VERSION 5.7 ;
  NOWIREEXTENSIONATPIN ON ;
  DIVIDERCHAR "/" ;
  BUSBITCHARS "[]" ;
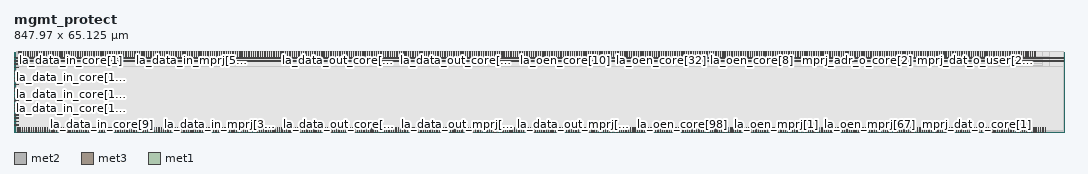
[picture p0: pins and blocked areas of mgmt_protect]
MACRO mgmt_protect
  CLASS BLOCK ;
  FOREIGN mgmt_protect ;
  ORIGIN 0.000 0.000 ;
  SIZE 847.970 BY 65.125 ;
  PIN caravel_clk
    DIRECTION INPUT ;
    PORT
      LAYER met2 ;
        RECT 2.850 0.000 3.130 4.000 ;
    END
  END caravel_clk
  PIN caravel_clk2
    DIRECTION INPUT ;
    PORT
      LAYER met2 ;
        RECT 4.690 0.000 4.970 4.000 ;
    END
  END caravel_clk2
  PIN caravel_rstn
    DIRECTION INPUT ;
    PORT
      LAYER met3 ;
        RECT 0.000 5.480 4.000 6.080 ;
    END
  END caravel_rstn
  PIN la_data_in_core[0]
    DIRECTION OUTPUT TRISTATE ;
    PORT
      LAYER met2 ;
        RECT 3.770 61.000 4.050 65.000 ;
    END
  END la_data_in_core[0]
  PIN la_data_in_core[100]
    DIRECTION OUTPUT TRISTATE ;
    PORT
      LAYER met3 ;
        RECT 0.000 59.880 4.000 60.480 ;
    END
  END la_data_in_core[100]
  PIN la_data_in_core[101]
    DIRECTION OUTPUT TRISTATE ;
    PORT
      LAYER met2 ;
        RECT 5.610 61.000 5.890 65.000 ;
    END
  END la_data_in_core[101]
  PIN la_data_in_core[102]
    DIRECTION OUTPUT TRISTATE ;
    PORT
      LAYER met3 ;
        RECT 0.000 57.160 4.000 57.760 ;
    END
  END la_data_in_core[102]
  PIN la_data_in_core[103]
    DIRECTION OUTPUT TRISTATE ;
    PORT
      LAYER met2 ;
        RECT 7.450 61.000 7.730 65.000 ;
    END
  END la_data_in_core[103]
  PIN la_data_in_core[104]
    DIRECTION OUTPUT TRISTATE ;
    PORT
      LAYER met2 ;
        RECT 9.290 61.000 9.570 65.000 ;
    END
  END la_data_in_core[104]
  PIN la_data_in_core[105]
    DIRECTION OUTPUT TRISTATE ;
    PORT
      LAYER met3 ;
        RECT 0.000 54.440 4.000 55.040 ;
    END
  END la_data_in_core[105]
  PIN la_data_in_core[106]
    DIRECTION OUTPUT TRISTATE ;
    PORT
      LAYER met2 ;
        RECT 11.130 61.000 11.410 65.000 ;
    END
  END la_data_in_core[106]
  PIN la_data_in_core[107]
    DIRECTION OUTPUT TRISTATE ;
    PORT
      LAYER met3 ;
        RECT 0.000 51.720 4.000 52.320 ;
    END
  END la_data_in_core[107]
  PIN la_data_in_core[108]
    DIRECTION OUTPUT TRISTATE ;
    PORT
      LAYER met2 ;
        RECT 12.970 61.000 13.250 65.000 ;
    END
  END la_data_in_core[108]
  PIN la_data_in_core[109]
    DIRECTION OUTPUT TRISTATE ;
    PORT
      LAYER met2 ;
        RECT 14.810 61.000 15.090 65.000 ;
    END
  END la_data_in_core[109]
  PIN la_data_in_core[10]
    DIRECTION OUTPUT TRISTATE ;
    PORT
      LAYER met3 ;
        RECT 0.000 49.000 4.000 49.600 ;
    END
  END la_data_in_core[10]
  PIN la_data_in_core[110]
    DIRECTION OUTPUT TRISTATE ;
    PORT
      LAYER met2 ;
        RECT 16.650 61.000 16.930 65.000 ;
    END
  END la_data_in_core[110]
  PIN la_data_in_core[111]
    DIRECTION OUTPUT TRISTATE ;
    PORT
      LAYER met3 ;
        RECT 0.000 46.280 4.000 46.880 ;
    END
  END la_data_in_core[111]
  PIN la_data_in_core[112]
    DIRECTION OUTPUT TRISTATE ;
    PORT
      LAYER met2 ;
        RECT 18.490 61.000 18.770 65.000 ;
    END
  END la_data_in_core[112]
  PIN la_data_in_core[113]
    DIRECTION OUTPUT TRISTATE ;
    PORT
      LAYER met2 ;
        RECT 20.330 61.000 20.610 65.000 ;
    END
  END la_data_in_core[113]
  PIN la_data_in_core[114]
    DIRECTION OUTPUT TRISTATE ;
    PORT
      LAYER met3 ;
        RECT 0.000 43.560 4.000 44.160 ;
    END
  END la_data_in_core[114]
  PIN la_data_in_core[115]
    DIRECTION OUTPUT TRISTATE ;
    PORT
      LAYER met2 ;
        RECT 22.170 61.000 22.450 65.000 ;
    END
  END la_data_in_core[115]
  PIN la_data_in_core[116]
    DIRECTION OUTPUT TRISTATE ;
    PORT
      LAYER met3 ;
        RECT 0.000 40.840 4.000 41.440 ;
    END
  END la_data_in_core[116]
  PIN la_data_in_core[117]
    DIRECTION OUTPUT TRISTATE ;
    PORT
      LAYER met2 ;
        RECT 24.010 61.000 24.290 65.000 ;
    END
  END la_data_in_core[117]
  PIN la_data_in_core[118]
    DIRECTION OUTPUT TRISTATE ;
    PORT
      LAYER met2 ;
        RECT 25.850 61.000 26.130 65.000 ;
    END
  END la_data_in_core[118]
  PIN la_data_in_core[119]
    DIRECTION OUTPUT TRISTATE ;
    PORT
      LAYER met3 ;
        RECT 0.000 38.120 4.000 38.720 ;
    END
  END la_data_in_core[119]
  PIN la_data_in_core[11]
    DIRECTION OUTPUT TRISTATE ;
    PORT
      LAYER met2 ;
        RECT 27.690 61.000 27.970 65.000 ;
    END
  END la_data_in_core[11]
  PIN la_data_in_core[120]
    DIRECTION OUTPUT TRISTATE ;
    PORT
      LAYER met3 ;
        RECT 0.000 35.400 4.000 36.000 ;
    END
  END la_data_in_core[120]
  PIN la_data_in_core[121]
    DIRECTION OUTPUT TRISTATE ;
    PORT
      LAYER met2 ;
        RECT 29.530 61.000 29.810 65.000 ;
    END
  END la_data_in_core[121]
  PIN la_data_in_core[122]
    DIRECTION OUTPUT TRISTATE ;
    PORT
      LAYER met2 ;
        RECT 31.370 61.000 31.650 65.000 ;
    END
  END la_data_in_core[122]
  PIN la_data_in_core[123]
    DIRECTION OUTPUT TRISTATE ;
    PORT
      LAYER met3 ;
        RECT 0.000 32.680 4.000 33.280 ;
    END
  END la_data_in_core[123]
  PIN la_data_in_core[124]
    DIRECTION OUTPUT TRISTATE ;
    PORT
      LAYER met2 ;
        RECT 33.210 61.000 33.490 65.000 ;
    END
  END la_data_in_core[124]
  PIN la_data_in_core[125]
    DIRECTION OUTPUT TRISTATE ;
    PORT
      LAYER met3 ;
        RECT 0.000 29.960 4.000 30.560 ;
    END
  END la_data_in_core[125]
  PIN la_data_in_core[126]
    DIRECTION OUTPUT TRISTATE ;
    PORT
      LAYER met2 ;
        RECT 35.050 61.000 35.330 65.000 ;
    END
  END la_data_in_core[126]
  PIN la_data_in_core[127]
    DIRECTION OUTPUT TRISTATE ;
    PORT
      LAYER met2 ;
        RECT 36.890 61.000 37.170 65.000 ;
    END
  END la_data_in_core[127]
  PIN la_data_in_core[12]
    DIRECTION OUTPUT TRISTATE ;
    PORT
      LAYER met3 ;
        RECT 0.000 27.240 4.000 27.840 ;
    END
  END la_data_in_core[12]
  PIN la_data_in_core[13]
    DIRECTION OUTPUT TRISTATE ;
    PORT
      LAYER met2 ;
        RECT 38.730 61.000 39.010 65.000 ;
    END
  END la_data_in_core[13]
  PIN la_data_in_core[14]
    DIRECTION OUTPUT TRISTATE ;
    PORT
      LAYER met3 ;
        RECT 0.000 24.520 4.000 25.120 ;
    END
  END la_data_in_core[14]
  PIN la_data_in_core[15]
    DIRECTION OUTPUT TRISTATE ;
    PORT
      LAYER met2 ;
        RECT 40.570 61.000 40.850 65.000 ;
    END
  END la_data_in_core[15]
  PIN la_data_in_core[16]
    DIRECTION OUTPUT TRISTATE ;
    PORT
      LAYER met2 ;
        RECT 42.410 61.000 42.690 65.000 ;
    END
  END la_data_in_core[16]
  PIN la_data_in_core[17]
    DIRECTION OUTPUT TRISTATE ;
    PORT
      LAYER met3 ;
        RECT 0.000 21.800 4.000 22.400 ;
    END
  END la_data_in_core[17]
  PIN la_data_in_core[18]
    DIRECTION OUTPUT TRISTATE ;
    PORT
      LAYER met2 ;
        RECT 44.250 61.000 44.530 65.000 ;
    END
  END la_data_in_core[18]
  PIN la_data_in_core[19]
    DIRECTION OUTPUT TRISTATE ;
    PORT
      LAYER met3 ;
        RECT 0.000 19.080 4.000 19.680 ;
    END
  END la_data_in_core[19]
  PIN la_data_in_core[1]
    DIRECTION OUTPUT TRISTATE ;
    PORT
      LAYER met2 ;
        RECT 46.090 61.000 46.370 65.000 ;
    END
  END la_data_in_core[1]
  PIN la_data_in_core[20]
    DIRECTION OUTPUT TRISTATE ;
    PORT
      LAYER met2 ;
        RECT 47.930 61.000 48.210 65.000 ;
    END
  END la_data_in_core[20]
  PIN la_data_in_core[21]
    DIRECTION OUTPUT TRISTATE ;
    PORT
      LAYER met3 ;
        RECT 0.000 16.360 4.000 16.960 ;
    END
  END la_data_in_core[21]
  PIN la_data_in_core[22]
    DIRECTION OUTPUT TRISTATE ;
    PORT
      LAYER met2 ;
        RECT 49.770 61.000 50.050 65.000 ;
    END
  END la_data_in_core[22]
  PIN la_data_in_core[23]
    DIRECTION OUTPUT TRISTATE ;
    PORT
      LAYER met3 ;
        RECT 0.000 13.640 4.000 14.240 ;
    END
  END la_data_in_core[23]
  PIN la_data_in_core[24]
    DIRECTION OUTPUT TRISTATE ;
    PORT
      LAYER met2 ;
        RECT 51.610 61.000 51.890 65.000 ;
    END
  END la_data_in_core[24]
  PIN la_data_in_core[25]
    DIRECTION OUTPUT TRISTATE ;
    PORT
      LAYER met2 ;
        RECT 53.450 61.000 53.730 65.000 ;
    END
  END la_data_in_core[25]
  PIN la_data_in_core[26]
    DIRECTION OUTPUT TRISTATE ;
    PORT
      LAYER met3 ;
        RECT 0.000 10.920 4.000 11.520 ;
    END
  END la_data_in_core[26]
  PIN la_data_in_core[27]
    DIRECTION OUTPUT TRISTATE ;
    PORT
      LAYER met2 ;
        RECT 55.290 61.000 55.570 65.000 ;
    END
  END la_data_in_core[27]
  PIN la_data_in_core[28]
    DIRECTION OUTPUT TRISTATE ;
    PORT
      LAYER met3 ;
        RECT 0.000 8.200 4.000 8.800 ;
    END
  END la_data_in_core[28]
  PIN la_data_in_core[29]
    DIRECTION OUTPUT TRISTATE ;
    PORT
      LAYER met2 ;
        RECT 57.130 61.000 57.410 65.000 ;
    END
  END la_data_in_core[29]
  PIN la_data_in_core[2]
    DIRECTION OUTPUT TRISTATE ;
    PORT
      LAYER met2 ;
        RECT 58.970 61.000 59.250 65.000 ;
    END
  END la_data_in_core[2]
  PIN la_data_in_core[30]
    DIRECTION OUTPUT TRISTATE ;
    PORT
      LAYER met2 ;
        RECT 60.810 61.000 61.090 65.000 ;
    END
  END la_data_in_core[30]
  PIN la_data_in_core[31]
    DIRECTION OUTPUT TRISTATE ;
    PORT
      LAYER met2 ;
        RECT 62.650 61.000 62.930 65.000 ;
    END
  END la_data_in_core[31]
  PIN la_data_in_core[32]
    DIRECTION OUTPUT TRISTATE ;
    PORT
      LAYER met2 ;
        RECT 64.490 61.000 64.770 65.000 ;
    END
  END la_data_in_core[32]
  PIN la_data_in_core[33]
    DIRECTION OUTPUT TRISTATE ;
    PORT
      LAYER met2 ;
        RECT 66.330 61.000 66.610 65.000 ;
    END
  END la_data_in_core[33]
  PIN la_data_in_core[34]
    DIRECTION OUTPUT TRISTATE ;
    PORT
      LAYER met2 ;
        RECT 68.170 61.000 68.450 65.000 ;
    END
  END la_data_in_core[34]
  PIN la_data_in_core[35]
    DIRECTION OUTPUT TRISTATE ;
    PORT
      LAYER met2 ;
        RECT 70.010 61.000 70.290 65.000 ;
    END
  END la_data_in_core[35]
  PIN la_data_in_core[36]
    DIRECTION OUTPUT TRISTATE ;
    PORT
      LAYER met2 ;
        RECT 6.530 0.000 6.810 4.000 ;
    END
  END la_data_in_core[36]
  PIN la_data_in_core[37]
    DIRECTION OUTPUT TRISTATE ;
    PORT
      LAYER met2 ;
        RECT 71.850 61.000 72.130 65.000 ;
    END
  END la_data_in_core[37]
  PIN la_data_in_core[38]
    DIRECTION OUTPUT TRISTATE ;
    PORT
      LAYER met2 ;
        RECT 8.370 0.000 8.650 4.000 ;
    END
  END la_data_in_core[38]
  PIN la_data_in_core[39]
    DIRECTION OUTPUT TRISTATE ;
    PORT
      LAYER met2 ;
        RECT 73.690 61.000 73.970 65.000 ;
    END
  END la_data_in_core[39]
  PIN la_data_in_core[3]
    DIRECTION OUTPUT TRISTATE ;
    PORT
      LAYER met2 ;
        RECT 10.210 0.000 10.490 4.000 ;
    END
  END la_data_in_core[3]
  PIN la_data_in_core[40]
    DIRECTION OUTPUT TRISTATE ;
    PORT
      LAYER met2 ;
        RECT 75.530 61.000 75.810 65.000 ;
    END
  END la_data_in_core[40]
  PIN la_data_in_core[41]
    DIRECTION OUTPUT TRISTATE ;
    PORT
      LAYER met2 ;
        RECT 12.050 0.000 12.330 4.000 ;
    END
  END la_data_in_core[41]
  PIN la_data_in_core[42]
    DIRECTION OUTPUT TRISTATE ;
    PORT
      LAYER met2 ;
        RECT 77.370 61.000 77.650 65.000 ;
    END
  END la_data_in_core[42]
  PIN la_data_in_core[43]
    DIRECTION OUTPUT TRISTATE ;
    PORT
      LAYER met2 ;
        RECT 13.890 0.000 14.170 4.000 ;
    END
  END la_data_in_core[43]
  PIN la_data_in_core[44]
    DIRECTION OUTPUT TRISTATE ;
    PORT
      LAYER met2 ;
        RECT 79.210 61.000 79.490 65.000 ;
    END
  END la_data_in_core[44]
  PIN la_data_in_core[45]
    DIRECTION OUTPUT TRISTATE ;
    PORT
      LAYER met2 ;
        RECT 15.730 0.000 16.010 4.000 ;
    END
  END la_data_in_core[45]
  PIN la_data_in_core[46]
    DIRECTION OUTPUT TRISTATE ;
    PORT
      LAYER met2 ;
        RECT 81.050 61.000 81.330 65.000 ;
    END
  END la_data_in_core[46]
  PIN la_data_in_core[47]
    DIRECTION OUTPUT TRISTATE ;
    PORT
      LAYER met2 ;
        RECT 17.570 0.000 17.850 4.000 ;
    END
  END la_data_in_core[47]
  PIN la_data_in_core[48]
    DIRECTION OUTPUT TRISTATE ;
    PORT
      LAYER met2 ;
        RECT 82.890 61.000 83.170 65.000 ;
    END
  END la_data_in_core[48]
  PIN la_data_in_core[49]
    DIRECTION OUTPUT TRISTATE ;
    PORT
      LAYER met2 ;
        RECT 19.410 0.000 19.690 4.000 ;
    END
  END la_data_in_core[49]
  PIN la_data_in_core[4]
    DIRECTION OUTPUT TRISTATE ;
    PORT
      LAYER met2 ;
        RECT 84.730 61.000 85.010 65.000 ;
    END
  END la_data_in_core[4]
  PIN la_data_in_core[50]
    DIRECTION OUTPUT TRISTATE ;
    PORT
      LAYER met2 ;
        RECT 21.250 0.000 21.530 4.000 ;
    END
  END la_data_in_core[50]
  PIN la_data_in_core[51]
    DIRECTION OUTPUT TRISTATE ;
    PORT
      LAYER met2 ;
        RECT 86.570 61.000 86.850 65.000 ;
    END
  END la_data_in_core[51]
  PIN la_data_in_core[52]
    DIRECTION OUTPUT TRISTATE ;
    PORT
      LAYER met2 ;
        RECT 23.090 0.000 23.370 4.000 ;
    END
  END la_data_in_core[52]
  PIN la_data_in_core[53]
    DIRECTION OUTPUT TRISTATE ;
    PORT
      LAYER met2 ;
        RECT 88.410 61.000 88.690 65.000 ;
    END
  END la_data_in_core[53]
  PIN la_data_in_core[54]
    DIRECTION OUTPUT TRISTATE ;
    PORT
      LAYER met2 ;
        RECT 24.930 0.000 25.210 4.000 ;
    END
  END la_data_in_core[54]
  PIN la_data_in_core[55]
    DIRECTION OUTPUT TRISTATE ;
    PORT
      LAYER met2 ;
        RECT 90.250 61.000 90.530 65.000 ;
    END
  END la_data_in_core[55]
  PIN la_data_in_core[56]
    DIRECTION OUTPUT TRISTATE ;
    PORT
      LAYER met2 ;
        RECT 26.770 0.000 27.050 4.000 ;
    END
  END la_data_in_core[56]
  PIN la_data_in_core[57]
    DIRECTION OUTPUT TRISTATE ;
    PORT
      LAYER met2 ;
        RECT 92.090 61.000 92.370 65.000 ;
    END
  END la_data_in_core[57]
  PIN la_data_in_core[58]
    DIRECTION OUTPUT TRISTATE ;
    PORT
      LAYER met2 ;
        RECT 28.610 0.000 28.890 4.000 ;
    END
  END la_data_in_core[58]
  PIN la_data_in_core[59]
    DIRECTION OUTPUT TRISTATE ;
    PORT
      LAYER met2 ;
        RECT 93.930 61.000 94.210 65.000 ;
    END
  END la_data_in_core[59]
  PIN la_data_in_core[5]
    DIRECTION OUTPUT TRISTATE ;
    PORT
      LAYER met2 ;
        RECT 30.450 0.000 30.730 4.000 ;
    END
  END la_data_in_core[5]
  PIN la_data_in_core[60]
    DIRECTION OUTPUT TRISTATE ;
    PORT
      LAYER met2 ;
        RECT 95.770 61.000 96.050 65.000 ;
    END
  END la_data_in_core[60]
  PIN la_data_in_core[61]
    DIRECTION OUTPUT TRISTATE ;
    PORT
      LAYER met2 ;
        RECT 32.290 0.000 32.570 4.000 ;
    END
  END la_data_in_core[61]
  PIN la_data_in_core[62]
    DIRECTION OUTPUT TRISTATE ;
    PORT
      LAYER met2 ;
        RECT 97.610 61.000 97.890 65.000 ;
    END
  END la_data_in_core[62]
  PIN la_data_in_core[63]
    DIRECTION OUTPUT TRISTATE ;
    PORT
      LAYER met2 ;
        RECT 34.130 0.000 34.410 4.000 ;
    END
  END la_data_in_core[63]
  PIN la_data_in_core[64]
    DIRECTION OUTPUT TRISTATE ;
    PORT
      LAYER met2 ;
        RECT 99.450 61.000 99.730 65.000 ;
    END
  END la_data_in_core[64]
  PIN la_data_in_core[65]
    DIRECTION OUTPUT TRISTATE ;
    PORT
      LAYER met2 ;
        RECT 35.970 0.000 36.250 4.000 ;
    END
  END la_data_in_core[65]
  PIN la_data_in_core[66]
    DIRECTION OUTPUT TRISTATE ;
    PORT
      LAYER met2 ;
        RECT 101.290 61.000 101.570 65.000 ;
    END
  END la_data_in_core[66]
  PIN la_data_in_core[67]
    DIRECTION OUTPUT TRISTATE ;
    PORT
      LAYER met2 ;
        RECT 37.810 0.000 38.090 4.000 ;
    END
  END la_data_in_core[67]
  PIN la_data_in_core[68]
    DIRECTION OUTPUT TRISTATE ;
    PORT
      LAYER met2 ;
        RECT 103.130 61.000 103.410 65.000 ;
    END
  END la_data_in_core[68]
  PIN la_data_in_core[69]
    DIRECTION OUTPUT TRISTATE ;
    PORT
      LAYER met2 ;
        RECT 39.650 0.000 39.930 4.000 ;
    END
  END la_data_in_core[69]
  PIN la_data_in_core[6]
    DIRECTION OUTPUT TRISTATE ;
    PORT
      LAYER met2 ;
        RECT 104.970 61.000 105.250 65.000 ;
    END
  END la_data_in_core[6]
  PIN la_data_in_core[70]
    DIRECTION OUTPUT TRISTATE ;
    PORT
      LAYER met2 ;
        RECT 41.490 0.000 41.770 4.000 ;
    END
  END la_data_in_core[70]
  PIN la_data_in_core[71]
    DIRECTION OUTPUT TRISTATE ;
    PORT
      LAYER met2 ;
        RECT 106.810 61.000 107.090 65.000 ;
    END
  END la_data_in_core[71]
  PIN la_data_in_core[72]
    DIRECTION OUTPUT TRISTATE ;
    PORT
      LAYER met2 ;
        RECT 43.330 0.000 43.610 4.000 ;
    END
  END la_data_in_core[72]
  PIN la_data_in_core[73]
    DIRECTION OUTPUT TRISTATE ;
    PORT
      LAYER met2 ;
        RECT 108.650 61.000 108.930 65.000 ;
    END
  END la_data_in_core[73]
  PIN la_data_in_core[74]
    DIRECTION OUTPUT TRISTATE ;
    PORT
      LAYER met2 ;
        RECT 45.170 0.000 45.450 4.000 ;
    END
  END la_data_in_core[74]
  PIN la_data_in_core[75]
    DIRECTION OUTPUT TRISTATE ;
    PORT
      LAYER met2 ;
        RECT 110.490 61.000 110.770 65.000 ;
    END
  END la_data_in_core[75]
  PIN la_data_in_core[76]
    DIRECTION OUTPUT TRISTATE ;
    PORT
      LAYER met2 ;
        RECT 47.010 0.000 47.290 4.000 ;
    END
  END la_data_in_core[76]
  PIN la_data_in_core[77]
    DIRECTION OUTPUT TRISTATE ;
    PORT
      LAYER met2 ;
        RECT 112.330 61.000 112.610 65.000 ;
    END
  END la_data_in_core[77]
  PIN la_data_in_core[78]
    DIRECTION OUTPUT TRISTATE ;
    PORT
      LAYER met2 ;
        RECT 48.850 0.000 49.130 4.000 ;
    END
  END la_data_in_core[78]
  PIN la_data_in_core[79]
    DIRECTION OUTPUT TRISTATE ;
    PORT
      LAYER met2 ;
        RECT 114.170 61.000 114.450 65.000 ;
    END
  END la_data_in_core[79]
  PIN la_data_in_core[7]
    DIRECTION OUTPUT TRISTATE ;
    PORT
      LAYER met2 ;
        RECT 50.690 0.000 50.970 4.000 ;
    END
  END la_data_in_core[7]
  PIN la_data_in_core[80]
    DIRECTION OUTPUT TRISTATE ;
    PORT
      LAYER met2 ;
        RECT 116.010 61.000 116.290 65.000 ;
    END
  END la_data_in_core[80]
  PIN la_data_in_core[81]
    DIRECTION OUTPUT TRISTATE ;
    PORT
      LAYER met2 ;
        RECT 52.530 0.000 52.810 4.000 ;
    END
  END la_data_in_core[81]
  PIN la_data_in_core[82]
    DIRECTION OUTPUT TRISTATE ;
    PORT
      LAYER met2 ;
        RECT 117.850 61.000 118.130 65.000 ;
    END
  END la_data_in_core[82]
  PIN la_data_in_core[83]
    DIRECTION OUTPUT TRISTATE ;
    PORT
      LAYER met2 ;
        RECT 54.370 0.000 54.650 4.000 ;
    END
  END la_data_in_core[83]
  PIN la_data_in_core[84]
    DIRECTION OUTPUT TRISTATE ;
    PORT
      LAYER met2 ;
        RECT 119.690 61.000 119.970 65.000 ;
    END
  END la_data_in_core[84]
  PIN la_data_in_core[85]
    DIRECTION OUTPUT TRISTATE ;
    PORT
      LAYER met2 ;
        RECT 56.210 0.000 56.490 4.000 ;
    END
  END la_data_in_core[85]
  PIN la_data_in_core[86]
    DIRECTION OUTPUT TRISTATE ;
    PORT
      LAYER met2 ;
        RECT 121.530 61.000 121.810 65.000 ;
    END
  END la_data_in_core[86]
  PIN la_data_in_core[87]
    DIRECTION OUTPUT TRISTATE ;
    PORT
      LAYER met2 ;
        RECT 58.050 0.000 58.330 4.000 ;
    END
  END la_data_in_core[87]
  PIN la_data_in_core[88]
    DIRECTION OUTPUT TRISTATE ;
    PORT
      LAYER met2 ;
        RECT 123.370 61.000 123.650 65.000 ;
    END
  END la_data_in_core[88]
  PIN la_data_in_core[89]
    DIRECTION OUTPUT TRISTATE ;
    PORT
      LAYER met2 ;
        RECT 59.890 0.000 60.170 4.000 ;
    END
  END la_data_in_core[89]
  PIN la_data_in_core[8]
    DIRECTION OUTPUT TRISTATE ;
    PORT
      LAYER met2 ;
        RECT 125.210 61.000 125.490 65.000 ;
    END
  END la_data_in_core[8]
  PIN la_data_in_core[90]
    DIRECTION OUTPUT TRISTATE ;
    PORT
      LAYER met2 ;
        RECT 61.730 0.000 62.010 4.000 ;
    END
  END la_data_in_core[90]
  PIN la_data_in_core[91]
    DIRECTION OUTPUT TRISTATE ;
    PORT
      LAYER met2 ;
        RECT 127.050 61.000 127.330 65.000 ;
    END
  END la_data_in_core[91]
  PIN la_data_in_core[92]
    DIRECTION OUTPUT TRISTATE ;
    PORT
      LAYER met2 ;
        RECT 63.570 0.000 63.850 4.000 ;
    END
  END la_data_in_core[92]
  PIN la_data_in_core[93]
    DIRECTION OUTPUT TRISTATE ;
    PORT
      LAYER met2 ;
        RECT 128.890 61.000 129.170 65.000 ;
    END
  END la_data_in_core[93]
  PIN la_data_in_core[94]
    DIRECTION OUTPUT TRISTATE ;
    PORT
      LAYER met2 ;
        RECT 65.410 0.000 65.690 4.000 ;
    END
  END la_data_in_core[94]
  PIN la_data_in_core[95]
    DIRECTION OUTPUT TRISTATE ;
    PORT
      LAYER met2 ;
        RECT 130.730 61.000 131.010 65.000 ;
    END
  END la_data_in_core[95]
  PIN la_data_in_core[96]
    DIRECTION OUTPUT TRISTATE ;
    PORT
      LAYER met2 ;
        RECT 67.250 0.000 67.530 4.000 ;
    END
  END la_data_in_core[96]
  PIN la_data_in_core[97]
    DIRECTION OUTPUT TRISTATE ;
    PORT
      LAYER met2 ;
        RECT 132.570 61.000 132.850 65.000 ;
    END
  END la_data_in_core[97]
  PIN la_data_in_core[98]
    DIRECTION OUTPUT TRISTATE ;
    PORT
      LAYER met2 ;
        RECT 69.090 0.000 69.370 4.000 ;
    END
  END la_data_in_core[98]
  PIN la_data_in_core[99]
    DIRECTION OUTPUT TRISTATE ;
    PORT
      LAYER met2 ;
        RECT 134.410 61.000 134.690 65.000 ;
    END
  END la_data_in_core[99]
  PIN la_data_in_core[9]
    DIRECTION OUTPUT TRISTATE ;
    PORT
      LAYER met2 ;
        RECT 70.930 0.000 71.210 4.000 ;
    END
  END la_data_in_core[9]
  PIN la_data_in_mprj[0]
    DIRECTION OUTPUT TRISTATE ;
    PORT
      LAYER met2 ;
        RECT 72.770 0.000 73.050 4.000 ;
    END
  END la_data_in_mprj[0]
  PIN la_data_in_mprj[100]
    DIRECTION OUTPUT TRISTATE ;
    PORT
      LAYER met2 ;
        RECT 74.610 0.000 74.890 4.000 ;
    END
  END la_data_in_mprj[100]
  PIN la_data_in_mprj[101]
    DIRECTION OUTPUT TRISTATE ;
    PORT
      LAYER met2 ;
        RECT 76.450 0.000 76.730 4.000 ;
    END
  END la_data_in_mprj[101]
  PIN la_data_in_mprj[102]
    DIRECTION OUTPUT TRISTATE ;
    PORT
      LAYER met2 ;
        RECT 78.290 0.000 78.570 4.000 ;
    END
  END la_data_in_mprj[102]
  PIN la_data_in_mprj[103]
    DIRECTION OUTPUT TRISTATE ;
    PORT
      LAYER met2 ;
        RECT 80.130 0.000 80.410 4.000 ;
    END
  END la_data_in_mprj[103]
  PIN la_data_in_mprj[104]
    DIRECTION OUTPUT TRISTATE ;
    PORT
      LAYER met2 ;
        RECT 81.970 0.000 82.250 4.000 ;
    END
  END la_data_in_mprj[104]
  PIN la_data_in_mprj[105]
    DIRECTION OUTPUT TRISTATE ;
    PORT
      LAYER met2 ;
        RECT 83.810 0.000 84.090 4.000 ;
    END
  END la_data_in_mprj[105]
  PIN la_data_in_mprj[106]
    DIRECTION OUTPUT TRISTATE ;
    PORT
      LAYER met2 ;
        RECT 85.650 0.000 85.930 4.000 ;
    END
  END la_data_in_mprj[106]
  PIN la_data_in_mprj[107]
    DIRECTION OUTPUT TRISTATE ;
    PORT
      LAYER met2 ;
        RECT 87.490 0.000 87.770 4.000 ;
    END
  END la_data_in_mprj[107]
  PIN la_data_in_mprj[108]
    DIRECTION OUTPUT TRISTATE ;
    PORT
      LAYER met2 ;
        RECT 89.330 0.000 89.610 4.000 ;
    END
  END la_data_in_mprj[108]
  PIN la_data_in_mprj[109]
    DIRECTION OUTPUT TRISTATE ;
    PORT
      LAYER met2 ;
        RECT 91.170 0.000 91.450 4.000 ;
    END
  END la_data_in_mprj[109]
  PIN la_data_in_mprj[10]
    DIRECTION OUTPUT TRISTATE ;
    PORT
      LAYER met2 ;
        RECT 93.010 0.000 93.290 4.000 ;
    END
  END la_data_in_mprj[10]
  PIN la_data_in_mprj[110]
    DIRECTION OUTPUT TRISTATE ;
    PORT
      LAYER met2 ;
        RECT 94.850 0.000 95.130 4.000 ;
    END
  END la_data_in_mprj[110]
  PIN la_data_in_mprj[111]
    DIRECTION OUTPUT TRISTATE ;
    PORT
      LAYER met2 ;
        RECT 96.690 0.000 96.970 4.000 ;
    END
  END la_data_in_mprj[111]
  PIN la_data_in_mprj[112]
    DIRECTION OUTPUT TRISTATE ;
    PORT
      LAYER met2 ;
        RECT 98.530 0.000 98.810 4.000 ;
    END
  END la_data_in_mprj[112]
  PIN la_data_in_mprj[113]
    DIRECTION OUTPUT TRISTATE ;
    PORT
      LAYER met2 ;
        RECT 100.370 0.000 100.650 4.000 ;
    END
  END la_data_in_mprj[113]
  PIN la_data_in_mprj[114]
    DIRECTION OUTPUT TRISTATE ;
    PORT
      LAYER met2 ;
        RECT 102.210 0.000 102.490 4.000 ;
    END
  END la_data_in_mprj[114]
  PIN la_data_in_mprj[115]
    DIRECTION OUTPUT TRISTATE ;
    PORT
      LAYER met2 ;
        RECT 104.050 0.000 104.330 4.000 ;
    END
  END la_data_in_mprj[115]
  PIN la_data_in_mprj[116]
    DIRECTION OUTPUT TRISTATE ;
    PORT
      LAYER met2 ;
        RECT 105.890 0.000 106.170 4.000 ;
    END
  END la_data_in_mprj[116]
  PIN la_data_in_mprj[117]
    DIRECTION OUTPUT TRISTATE ;
    PORT
      LAYER met2 ;
        RECT 107.730 0.000 108.010 4.000 ;
    END
  END la_data_in_mprj[117]
  PIN la_data_in_mprj[118]
    DIRECTION OUTPUT TRISTATE ;
    PORT
      LAYER met2 ;
        RECT 109.570 0.000 109.850 4.000 ;
    END
  END la_data_in_mprj[118]
  PIN la_data_in_mprj[119]
    DIRECTION OUTPUT TRISTATE ;
    PORT
      LAYER met2 ;
        RECT 111.410 0.000 111.690 4.000 ;
    END
  END la_data_in_mprj[119]
  PIN la_data_in_mprj[11]
    DIRECTION OUTPUT TRISTATE ;
    PORT
      LAYER met2 ;
        RECT 113.250 0.000 113.530 4.000 ;
    END
  END la_data_in_mprj[11]
  PIN la_data_in_mprj[120]
    DIRECTION OUTPUT TRISTATE ;
    PORT
      LAYER met2 ;
        RECT 115.090 0.000 115.370 4.000 ;
    END
  END la_data_in_mprj[120]
  PIN la_data_in_mprj[121]
    DIRECTION OUTPUT TRISTATE ;
    PORT
      LAYER met2 ;
        RECT 116.930 0.000 117.210 4.000 ;
    END
  END la_data_in_mprj[121]
  PIN la_data_in_mprj[122]
    DIRECTION OUTPUT TRISTATE ;
    PORT
      LAYER met2 ;
        RECT 118.770 0.000 119.050 4.000 ;
    END
  END la_data_in_mprj[122]
  PIN la_data_in_mprj[123]
    DIRECTION OUTPUT TRISTATE ;
    PORT
      LAYER met2 ;
        RECT 120.610 0.000 120.890 4.000 ;
    END
  END la_data_in_mprj[123]
  PIN la_data_in_mprj[124]
    DIRECTION OUTPUT TRISTATE ;
    PORT
      LAYER met2 ;
        RECT 122.450 0.000 122.730 4.000 ;
    END
  END la_data_in_mprj[124]
  PIN la_data_in_mprj[125]
    DIRECTION OUTPUT TRISTATE ;
    PORT
      LAYER met2 ;
        RECT 124.290 0.000 124.570 4.000 ;
    END
  END la_data_in_mprj[125]
  PIN la_data_in_mprj[126]
    DIRECTION OUTPUT TRISTATE ;
    PORT
      LAYER met2 ;
        RECT 126.130 0.000 126.410 4.000 ;
    END
  END la_data_in_mprj[126]
  PIN la_data_in_mprj[127]
    DIRECTION OUTPUT TRISTATE ;
    PORT
      LAYER met2 ;
        RECT 127.970 0.000 128.250 4.000 ;
    END
  END la_data_in_mprj[127]
  PIN la_data_in_mprj[12]
    DIRECTION OUTPUT TRISTATE ;
    PORT
      LAYER met2 ;
        RECT 129.810 0.000 130.090 4.000 ;
    END
  END la_data_in_mprj[12]
  PIN la_data_in_mprj[13]
    DIRECTION OUTPUT TRISTATE ;
    PORT
      LAYER met2 ;
        RECT 131.650 0.000 131.930 4.000 ;
    END
  END la_data_in_mprj[13]
  PIN la_data_in_mprj[14]
    DIRECTION OUTPUT TRISTATE ;
    PORT
      LAYER met2 ;
        RECT 133.490 0.000 133.770 4.000 ;
    END
  END la_data_in_mprj[14]
  PIN la_data_in_mprj[15]
    DIRECTION OUTPUT TRISTATE ;
    PORT
      LAYER met2 ;
        RECT 135.330 0.000 135.610 4.000 ;
    END
  END la_data_in_mprj[15]
  PIN la_data_in_mprj[16]
    DIRECTION OUTPUT TRISTATE ;
    PORT
      LAYER met2 ;
        RECT 137.170 0.000 137.450 4.000 ;
    END
  END la_data_in_mprj[16]
  PIN la_data_in_mprj[17]
    DIRECTION OUTPUT TRISTATE ;
    PORT
      LAYER met2 ;
        RECT 139.010 0.000 139.290 4.000 ;
    END
  END la_data_in_mprj[17]
  PIN la_data_in_mprj[18]
    DIRECTION OUTPUT TRISTATE ;
    PORT
      LAYER met2 ;
        RECT 140.850 0.000 141.130 4.000 ;
    END
  END la_data_in_mprj[18]
  PIN la_data_in_mprj[19]
    DIRECTION OUTPUT TRISTATE ;
    PORT
      LAYER met2 ;
        RECT 142.690 0.000 142.970 4.000 ;
    END
  END la_data_in_mprj[19]
  PIN la_data_in_mprj[1]
    DIRECTION OUTPUT TRISTATE ;
    PORT
      LAYER met2 ;
        RECT 144.530 0.000 144.810 4.000 ;
    END
  END la_data_in_mprj[1]
  PIN la_data_in_mprj[20]
    DIRECTION OUTPUT TRISTATE ;
    PORT
      LAYER met2 ;
        RECT 146.370 0.000 146.650 4.000 ;
    END
  END la_data_in_mprj[20]
  PIN la_data_in_mprj[21]
    DIRECTION OUTPUT TRISTATE ;
    PORT
      LAYER met2 ;
        RECT 148.210 0.000 148.490 4.000 ;
    END
  END la_data_in_mprj[21]
  PIN la_data_in_mprj[22]
    DIRECTION OUTPUT TRISTATE ;
    PORT
      LAYER met2 ;
        RECT 150.050 0.000 150.330 4.000 ;
    END
  END la_data_in_mprj[22]
  PIN la_data_in_mprj[23]
    DIRECTION OUTPUT TRISTATE ;
    PORT
      LAYER met2 ;
        RECT 151.890 0.000 152.170 4.000 ;
    END
  END la_data_in_mprj[23]
  PIN la_data_in_mprj[24]
    DIRECTION OUTPUT TRISTATE ;
    PORT
      LAYER met2 ;
        RECT 153.730 0.000 154.010 4.000 ;
    END
  END la_data_in_mprj[24]
  PIN la_data_in_mprj[25]
    DIRECTION OUTPUT TRISTATE ;
    PORT
      LAYER met2 ;
        RECT 155.570 0.000 155.850 4.000 ;
    END
  END la_data_in_mprj[25]
  PIN la_data_in_mprj[26]
    DIRECTION OUTPUT TRISTATE ;
    PORT
      LAYER met2 ;
        RECT 157.410 0.000 157.690 4.000 ;
    END
  END la_data_in_mprj[26]
  PIN la_data_in_mprj[27]
    DIRECTION OUTPUT TRISTATE ;
    PORT
      LAYER met2 ;
        RECT 159.250 0.000 159.530 4.000 ;
    END
  END la_data_in_mprj[27]
  PIN la_data_in_mprj[28]
    DIRECTION OUTPUT TRISTATE ;
    PORT
      LAYER met2 ;
        RECT 161.090 0.000 161.370 4.000 ;
    END
  END la_data_in_mprj[28]
  PIN la_data_in_mprj[29]
    DIRECTION OUTPUT TRISTATE ;
    PORT
      LAYER met2 ;
        RECT 162.930 0.000 163.210 4.000 ;
    END
  END la_data_in_mprj[29]
  PIN la_data_in_mprj[2]
    DIRECTION OUTPUT TRISTATE ;
    PORT
      LAYER met2 ;
        RECT 164.770 0.000 165.050 4.000 ;
    END
  END la_data_in_mprj[2]
  PIN la_data_in_mprj[30]
    DIRECTION OUTPUT TRISTATE ;
    PORT
      LAYER met2 ;
        RECT 166.610 0.000 166.890 4.000 ;
    END
  END la_data_in_mprj[30]
  PIN la_data_in_mprj[31]
    DIRECTION OUTPUT TRISTATE ;
    PORT
      LAYER met2 ;
        RECT 168.450 0.000 168.730 4.000 ;
    END
  END la_data_in_mprj[31]
  PIN la_data_in_mprj[32]
    DIRECTION OUTPUT TRISTATE ;
    PORT
      LAYER met2 ;
        RECT 170.290 0.000 170.570 4.000 ;
    END
  END la_data_in_mprj[32]
  PIN la_data_in_mprj[33]
    DIRECTION OUTPUT TRISTATE ;
    PORT
      LAYER met2 ;
        RECT 172.130 0.000 172.410 4.000 ;
    END
  END la_data_in_mprj[33]
  PIN la_data_in_mprj[34]
    DIRECTION OUTPUT TRISTATE ;
    PORT
      LAYER met2 ;
        RECT 173.970 0.000 174.250 4.000 ;
    END
  END la_data_in_mprj[34]
  PIN la_data_in_mprj[35]
    DIRECTION OUTPUT TRISTATE ;
    PORT
      LAYER met2 ;
        RECT 175.810 0.000 176.090 4.000 ;
    END
  END la_data_in_mprj[35]
  PIN la_data_in_mprj[36]
    DIRECTION OUTPUT TRISTATE ;
    PORT
      LAYER met2 ;
        RECT 177.650 0.000 177.930 4.000 ;
    END
  END la_data_in_mprj[36]
  PIN la_data_in_mprj[37]
    DIRECTION OUTPUT TRISTATE ;
    PORT
      LAYER met2 ;
        RECT 179.490 0.000 179.770 4.000 ;
    END
  END la_data_in_mprj[37]
  PIN la_data_in_mprj[38]
    DIRECTION OUTPUT TRISTATE ;
    PORT
      LAYER met2 ;
        RECT 181.330 0.000 181.610 4.000 ;
    END
  END la_data_in_mprj[38]
  PIN la_data_in_mprj[39]
    DIRECTION OUTPUT TRISTATE ;
    PORT
      LAYER met2 ;
        RECT 183.170 0.000 183.450 4.000 ;
    END
  END la_data_in_mprj[39]
  PIN la_data_in_mprj[3]
    DIRECTION OUTPUT TRISTATE ;
    PORT
      LAYER met2 ;
        RECT 185.010 0.000 185.290 4.000 ;
    END
  END la_data_in_mprj[3]
  PIN la_data_in_mprj[40]
    DIRECTION OUTPUT TRISTATE ;
    PORT
      LAYER met2 ;
        RECT 186.850 0.000 187.130 4.000 ;
    END
  END la_data_in_mprj[40]
  PIN la_data_in_mprj[41]
    DIRECTION OUTPUT TRISTATE ;
    PORT
      LAYER met2 ;
        RECT 188.690 0.000 188.970 4.000 ;
    END
  END la_data_in_mprj[41]
  PIN la_data_in_mprj[42]
    DIRECTION OUTPUT TRISTATE ;
    PORT
      LAYER met2 ;
        RECT 190.530 0.000 190.810 4.000 ;
    END
  END la_data_in_mprj[42]
  PIN la_data_in_mprj[43]
    DIRECTION OUTPUT TRISTATE ;
    PORT
      LAYER met2 ;
        RECT 192.370 0.000 192.650 4.000 ;
    END
  END la_data_in_mprj[43]
  PIN la_data_in_mprj[44]
    DIRECTION OUTPUT TRISTATE ;
    PORT
      LAYER met2 ;
        RECT 194.210 0.000 194.490 4.000 ;
    END
  END la_data_in_mprj[44]
  PIN la_data_in_mprj[45]
    DIRECTION OUTPUT TRISTATE ;
    PORT
      LAYER met2 ;
        RECT 196.050 0.000 196.330 4.000 ;
    END
  END la_data_in_mprj[45]
  PIN la_data_in_mprj[46]
    DIRECTION OUTPUT TRISTATE ;
    PORT
      LAYER met2 ;
        RECT 197.890 0.000 198.170 4.000 ;
    END
  END la_data_in_mprj[46]
  PIN la_data_in_mprj[47]
    DIRECTION OUTPUT TRISTATE ;
    PORT
      LAYER met2 ;
        RECT 199.730 0.000 200.010 4.000 ;
    END
  END la_data_in_mprj[47]
  PIN la_data_in_mprj[48]
    DIRECTION OUTPUT TRISTATE ;
    PORT
      LAYER met2 ;
        RECT 136.250 61.000 136.530 65.000 ;
    END
  END la_data_in_mprj[48]
  PIN la_data_in_mprj[49]
    DIRECTION OUTPUT TRISTATE ;
    PORT
      LAYER met2 ;
        RECT 201.570 0.000 201.850 4.000 ;
    END
  END la_data_in_mprj[49]
  PIN la_data_in_mprj[4]
    DIRECTION OUTPUT TRISTATE ;
    PORT
      LAYER met2 ;
        RECT 138.090 61.000 138.370 65.000 ;
    END
  END la_data_in_mprj[4]
  PIN la_data_in_mprj[50]
    DIRECTION OUTPUT TRISTATE ;
    PORT
      LAYER met2 ;
        RECT 203.410 0.000 203.690 4.000 ;
    END
  END la_data_in_mprj[50]
  PIN la_data_in_mprj[51]
    DIRECTION OUTPUT TRISTATE ;
    PORT
      LAYER met2 ;
        RECT 139.930 61.000 140.210 65.000 ;
    END
  END la_data_in_mprj[51]
  PIN la_data_in_mprj[52]
    DIRECTION OUTPUT TRISTATE ;
    PORT
      LAYER met2 ;
        RECT 205.250 0.000 205.530 4.000 ;
    END
  END la_data_in_mprj[52]
  PIN la_data_in_mprj[53]
    DIRECTION OUTPUT TRISTATE ;
    PORT
      LAYER met2 ;
        RECT 141.770 61.000 142.050 65.000 ;
    END
  END la_data_in_mprj[53]
  PIN la_data_in_mprj[54]
    DIRECTION OUTPUT TRISTATE ;
    PORT
      LAYER met2 ;
        RECT 207.090 0.000 207.370 4.000 ;
    END
  END la_data_in_mprj[54]
  PIN la_data_in_mprj[55]
    DIRECTION OUTPUT TRISTATE ;
    PORT
      LAYER met2 ;
        RECT 143.610 61.000 143.890 65.000 ;
    END
  END la_data_in_mprj[55]
  PIN la_data_in_mprj[56]
    DIRECTION OUTPUT TRISTATE ;
    PORT
      LAYER met2 ;
        RECT 208.930 0.000 209.210 4.000 ;
    END
  END la_data_in_mprj[56]
  PIN la_data_in_mprj[57]
    DIRECTION OUTPUT TRISTATE ;
    PORT
      LAYER met2 ;
        RECT 145.450 61.000 145.730 65.000 ;
    END
  END la_data_in_mprj[57]
  PIN la_data_in_mprj[58]
    DIRECTION OUTPUT TRISTATE ;
    PORT
      LAYER met2 ;
        RECT 210.770 0.000 211.050 4.000 ;
    END
  END la_data_in_mprj[58]
  PIN la_data_in_mprj[59]
    DIRECTION OUTPUT TRISTATE ;
    PORT
      LAYER met2 ;
        RECT 147.290 61.000 147.570 65.000 ;
    END
  END la_data_in_mprj[59]
  PIN la_data_in_mprj[5]
    DIRECTION OUTPUT TRISTATE ;
    PORT
      LAYER met2 ;
        RECT 212.610 0.000 212.890 4.000 ;
    END
  END la_data_in_mprj[5]
  PIN la_data_in_mprj[60]
    DIRECTION OUTPUT TRISTATE ;
    PORT
      LAYER met2 ;
        RECT 149.130 61.000 149.410 65.000 ;
    END
  END la_data_in_mprj[60]
  PIN la_data_in_mprj[61]
    DIRECTION OUTPUT TRISTATE ;
    PORT
      LAYER met2 ;
        RECT 214.450 0.000 214.730 4.000 ;
    END
  END la_data_in_mprj[61]
  PIN la_data_in_mprj[62]
    DIRECTION OUTPUT TRISTATE ;
    PORT
      LAYER met2 ;
        RECT 150.970 61.000 151.250 65.000 ;
    END
  END la_data_in_mprj[62]
  PIN la_data_in_mprj[63]
    DIRECTION OUTPUT TRISTATE ;
    PORT
      LAYER met2 ;
        RECT 216.290 0.000 216.570 4.000 ;
    END
  END la_data_in_mprj[63]
  PIN la_data_in_mprj[64]
    DIRECTION OUTPUT TRISTATE ;
    PORT
      LAYER met2 ;
        RECT 152.810 61.000 153.090 65.000 ;
    END
  END la_data_in_mprj[64]
  PIN la_data_in_mprj[65]
    DIRECTION OUTPUT TRISTATE ;
    PORT
      LAYER met2 ;
        RECT 218.130 0.000 218.410 4.000 ;
    END
  END la_data_in_mprj[65]
  PIN la_data_in_mprj[66]
    DIRECTION OUTPUT TRISTATE ;
    PORT
      LAYER met2 ;
        RECT 154.650 61.000 154.930 65.000 ;
    END
  END la_data_in_mprj[66]
  PIN la_data_in_mprj[67]
    DIRECTION OUTPUT TRISTATE ;
    PORT
      LAYER met2 ;
        RECT 219.970 0.000 220.250 4.000 ;
    END
  END la_data_in_mprj[67]
  PIN la_data_in_mprj[68]
    DIRECTION OUTPUT TRISTATE ;
    PORT
      LAYER met2 ;
        RECT 156.490 61.000 156.770 65.000 ;
    END
  END la_data_in_mprj[68]
  PIN la_data_in_mprj[69]
    DIRECTION OUTPUT TRISTATE ;
    PORT
      LAYER met2 ;
        RECT 221.810 0.000 222.090 4.000 ;
    END
  END la_data_in_mprj[69]
  PIN la_data_in_mprj[6]
    DIRECTION OUTPUT TRISTATE ;
    PORT
      LAYER met2 ;
        RECT 158.330 61.000 158.610 65.000 ;
    END
  END la_data_in_mprj[6]
  PIN la_data_in_mprj[70]
    DIRECTION OUTPUT TRISTATE ;
    PORT
      LAYER met2 ;
        RECT 223.650 0.000 223.930 4.000 ;
    END
  END la_data_in_mprj[70]
  PIN la_data_in_mprj[71]
    DIRECTION OUTPUT TRISTATE ;
    PORT
      LAYER met2 ;
        RECT 160.170 61.000 160.450 65.000 ;
    END
  END la_data_in_mprj[71]
  PIN la_data_in_mprj[72]
    DIRECTION OUTPUT TRISTATE ;
    PORT
      LAYER met2 ;
        RECT 225.490 0.000 225.770 4.000 ;
    END
  END la_data_in_mprj[72]
  PIN la_data_in_mprj[73]
    DIRECTION OUTPUT TRISTATE ;
    PORT
      LAYER met2 ;
        RECT 162.010 61.000 162.290 65.000 ;
    END
  END la_data_in_mprj[73]
  PIN la_data_in_mprj[74]
    DIRECTION OUTPUT TRISTATE ;
    PORT
      LAYER met2 ;
        RECT 227.330 0.000 227.610 4.000 ;
    END
  END la_data_in_mprj[74]
  PIN la_data_in_mprj[75]
    DIRECTION OUTPUT TRISTATE ;
    PORT
      LAYER met2 ;
        RECT 163.850 61.000 164.130 65.000 ;
    END
  END la_data_in_mprj[75]
  PIN la_data_in_mprj[76]
    DIRECTION OUTPUT TRISTATE ;
    PORT
      LAYER met2 ;
        RECT 229.170 0.000 229.450 4.000 ;
    END
  END la_data_in_mprj[76]
  PIN la_data_in_mprj[77]
    DIRECTION OUTPUT TRISTATE ;
    PORT
      LAYER met2 ;
        RECT 165.690 61.000 165.970 65.000 ;
    END
  END la_data_in_mprj[77]
  PIN la_data_in_mprj[78]
    DIRECTION OUTPUT TRISTATE ;
    PORT
      LAYER met2 ;
        RECT 231.010 0.000 231.290 4.000 ;
    END
  END la_data_in_mprj[78]
  PIN la_data_in_mprj[79]
    DIRECTION OUTPUT TRISTATE ;
    PORT
      LAYER met2 ;
        RECT 167.530 61.000 167.810 65.000 ;
    END
  END la_data_in_mprj[79]
  PIN la_data_in_mprj[7]
    DIRECTION OUTPUT TRISTATE ;
    PORT
      LAYER met2 ;
        RECT 232.850 0.000 233.130 4.000 ;
    END
  END la_data_in_mprj[7]
  PIN la_data_in_mprj[80]
    DIRECTION OUTPUT TRISTATE ;
    PORT
      LAYER met2 ;
        RECT 169.370 61.000 169.650 65.000 ;
    END
  END la_data_in_mprj[80]
  PIN la_data_in_mprj[81]
    DIRECTION OUTPUT TRISTATE ;
    PORT
      LAYER met2 ;
        RECT 234.690 0.000 234.970 4.000 ;
    END
  END la_data_in_mprj[81]
  PIN la_data_in_mprj[82]
    DIRECTION OUTPUT TRISTATE ;
    PORT
      LAYER met2 ;
        RECT 171.210 61.000 171.490 65.000 ;
    END
  END la_data_in_mprj[82]
  PIN la_data_in_mprj[83]
    DIRECTION OUTPUT TRISTATE ;
    PORT
      LAYER met2 ;
        RECT 236.530 0.000 236.810 4.000 ;
    END
  END la_data_in_mprj[83]
  PIN la_data_in_mprj[84]
    DIRECTION OUTPUT TRISTATE ;
    PORT
      LAYER met2 ;
        RECT 173.050 61.000 173.330 65.000 ;
    END
  END la_data_in_mprj[84]
  PIN la_data_in_mprj[85]
    DIRECTION OUTPUT TRISTATE ;
    PORT
      LAYER met2 ;
        RECT 238.370 0.000 238.650 4.000 ;
    END
  END la_data_in_mprj[85]
  PIN la_data_in_mprj[86]
    DIRECTION OUTPUT TRISTATE ;
    PORT
      LAYER met2 ;
        RECT 174.890 61.000 175.170 65.000 ;
    END
  END la_data_in_mprj[86]
  PIN la_data_in_mprj[87]
    DIRECTION OUTPUT TRISTATE ;
    PORT
      LAYER met2 ;
        RECT 240.210 0.000 240.490 4.000 ;
    END
  END la_data_in_mprj[87]
  PIN la_data_in_mprj[88]
    DIRECTION OUTPUT TRISTATE ;
    PORT
      LAYER met2 ;
        RECT 176.730 61.000 177.010 65.000 ;
    END
  END la_data_in_mprj[88]
  PIN la_data_in_mprj[89]
    DIRECTION OUTPUT TRISTATE ;
    PORT
      LAYER met2 ;
        RECT 242.050 0.000 242.330 4.000 ;
    END
  END la_data_in_mprj[89]
  PIN la_data_in_mprj[8]
    DIRECTION OUTPUT TRISTATE ;
    PORT
      LAYER met2 ;
        RECT 178.570 61.000 178.850 65.000 ;
    END
  END la_data_in_mprj[8]
  PIN la_data_in_mprj[90]
    DIRECTION OUTPUT TRISTATE ;
    PORT
      LAYER met2 ;
        RECT 243.890 0.000 244.170 4.000 ;
    END
  END la_data_in_mprj[90]
  PIN la_data_in_mprj[91]
    DIRECTION OUTPUT TRISTATE ;
    PORT
      LAYER met2 ;
        RECT 180.410 61.000 180.690 65.000 ;
    END
  END la_data_in_mprj[91]
  PIN la_data_in_mprj[92]
    DIRECTION OUTPUT TRISTATE ;
    PORT
      LAYER met2 ;
        RECT 245.730 0.000 246.010 4.000 ;
    END
  END la_data_in_mprj[92]
  PIN la_data_in_mprj[93]
    DIRECTION OUTPUT TRISTATE ;
    PORT
      LAYER met2 ;
        RECT 182.250 61.000 182.530 65.000 ;
    END
  END la_data_in_mprj[93]
  PIN la_data_in_mprj[94]
    DIRECTION OUTPUT TRISTATE ;
    PORT
      LAYER met2 ;
        RECT 247.570 0.000 247.850 4.000 ;
    END
  END la_data_in_mprj[94]
  PIN la_data_in_mprj[95]
    DIRECTION OUTPUT TRISTATE ;
    PORT
      LAYER met2 ;
        RECT 184.090 61.000 184.370 65.000 ;
    END
  END la_data_in_mprj[95]
  PIN la_data_in_mprj[96]
    DIRECTION OUTPUT TRISTATE ;
    PORT
      LAYER met2 ;
        RECT 249.410 0.000 249.690 4.000 ;
    END
  END la_data_in_mprj[96]
  PIN la_data_in_mprj[97]
    DIRECTION OUTPUT TRISTATE ;
    PORT
      LAYER met2 ;
        RECT 185.930 61.000 186.210 65.000 ;
    END
  END la_data_in_mprj[97]
  PIN la_data_in_mprj[98]
    DIRECTION OUTPUT TRISTATE ;
    PORT
      LAYER met2 ;
        RECT 251.250 0.000 251.530 4.000 ;
    END
  END la_data_in_mprj[98]
  PIN la_data_in_mprj[99]
    DIRECTION OUTPUT TRISTATE ;
    PORT
      LAYER met2 ;
        RECT 187.770 61.000 188.050 65.000 ;
    END
  END la_data_in_mprj[99]
  PIN la_data_in_mprj[9]
    DIRECTION OUTPUT TRISTATE ;
    PORT
      LAYER met2 ;
        RECT 253.090 0.000 253.370 4.000 ;
    END
  END la_data_in_mprj[9]
  PIN la_data_out_core[0]
    DIRECTION INPUT ;
    PORT
      LAYER met2 ;
        RECT 189.610 61.000 189.890 65.000 ;
    END
  END la_data_out_core[0]
  PIN la_data_out_core[100]
    DIRECTION INPUT ;
    PORT
      LAYER met2 ;
        RECT 191.450 61.000 191.730 65.000 ;
    END
  END la_data_out_core[100]
  PIN la_data_out_core[101]
    DIRECTION INPUT ;
    PORT
      LAYER met2 ;
        RECT 193.290 61.000 193.570 65.000 ;
    END
  END la_data_out_core[101]
  PIN la_data_out_core[102]
    DIRECTION INPUT ;
    PORT
      LAYER met2 ;
        RECT 195.130 61.000 195.410 65.000 ;
    END
  END la_data_out_core[102]
  PIN la_data_out_core[103]
    DIRECTION INPUT ;
    PORT
      LAYER met2 ;
        RECT 196.970 61.000 197.250 65.000 ;
    END
  END la_data_out_core[103]
  PIN la_data_out_core[104]
    DIRECTION INPUT ;
    PORT
      LAYER met2 ;
        RECT 198.810 61.000 199.090 65.000 ;
    END
  END la_data_out_core[104]
  PIN la_data_out_core[105]
    DIRECTION INPUT ;
    PORT
      LAYER met2 ;
        RECT 200.650 61.000 200.930 65.000 ;
    END
  END la_data_out_core[105]
  PIN la_data_out_core[106]
    DIRECTION INPUT ;
    PORT
      LAYER met2 ;
        RECT 202.490 61.000 202.770 65.000 ;
    END
  END la_data_out_core[106]
  PIN la_data_out_core[107]
    DIRECTION INPUT ;
    PORT
      LAYER met2 ;
        RECT 204.330 61.000 204.610 65.000 ;
    END
  END la_data_out_core[107]
  PIN la_data_out_core[108]
    DIRECTION INPUT ;
    PORT
      LAYER met2 ;
        RECT 206.170 61.000 206.450 65.000 ;
    END
  END la_data_out_core[108]
  PIN la_data_out_core[109]
    DIRECTION INPUT ;
    PORT
      LAYER met2 ;
        RECT 208.010 61.000 208.290 65.000 ;
    END
  END la_data_out_core[109]
  PIN la_data_out_core[10]
    DIRECTION INPUT ;
    PORT
      LAYER met2 ;
        RECT 209.850 61.000 210.130 65.000 ;
    END
  END la_data_out_core[10]
  PIN la_data_out_core[110]
    DIRECTION INPUT ;
    PORT
      LAYER met2 ;
        RECT 211.690 61.000 211.970 65.000 ;
    END
  END la_data_out_core[110]
  PIN la_data_out_core[111]
    DIRECTION INPUT ;
    PORT
      LAYER met2 ;
        RECT 213.530 61.000 213.810 65.000 ;
    END
  END la_data_out_core[111]
  PIN la_data_out_core[112]
    DIRECTION INPUT ;
    PORT
      LAYER met2 ;
        RECT 215.370 61.000 215.650 65.000 ;
    END
  END la_data_out_core[112]
  PIN la_data_out_core[113]
    DIRECTION INPUT ;
    PORT
      LAYER met2 ;
        RECT 217.210 61.000 217.490 65.000 ;
    END
  END la_data_out_core[113]
  PIN la_data_out_core[114]
    DIRECTION INPUT ;
    PORT
      LAYER met2 ;
        RECT 219.050 61.000 219.330 65.000 ;
    END
  END la_data_out_core[114]
  PIN la_data_out_core[115]
    DIRECTION INPUT ;
    PORT
      LAYER met2 ;
        RECT 220.890 61.000 221.170 65.000 ;
    END
  END la_data_out_core[115]
  PIN la_data_out_core[116]
    DIRECTION INPUT ;
    PORT
      LAYER met2 ;
        RECT 222.730 61.000 223.010 65.000 ;
    END
  END la_data_out_core[116]
  PIN la_data_out_core[117]
    DIRECTION INPUT ;
    PORT
      LAYER met2 ;
        RECT 224.570 61.000 224.850 65.000 ;
    END
  END la_data_out_core[117]
  PIN la_data_out_core[118]
    DIRECTION INPUT ;
    PORT
      LAYER met2 ;
        RECT 226.410 61.000 226.690 65.000 ;
    END
  END la_data_out_core[118]
  PIN la_data_out_core[119]
    DIRECTION INPUT ;
    PORT
      LAYER met2 ;
        RECT 228.250 61.000 228.530 65.000 ;
    END
  END la_data_out_core[119]
  PIN la_data_out_core[11]
    DIRECTION INPUT ;
    PORT
      LAYER met2 ;
        RECT 230.090 61.000 230.370 65.000 ;
    END
  END la_data_out_core[11]
  PIN la_data_out_core[120]
    DIRECTION INPUT ;
    PORT
      LAYER met2 ;
        RECT 231.930 61.000 232.210 65.000 ;
    END
  END la_data_out_core[120]
  PIN la_data_out_core[121]
    DIRECTION INPUT ;
    PORT
      LAYER met2 ;
        RECT 233.770 61.000 234.050 65.000 ;
    END
  END la_data_out_core[121]
  PIN la_data_out_core[122]
    DIRECTION INPUT ;
    PORT
      LAYER met2 ;
        RECT 235.610 61.000 235.890 65.000 ;
    END
  END la_data_out_core[122]
  PIN la_data_out_core[123]
    DIRECTION INPUT ;
    PORT
      LAYER met2 ;
        RECT 237.450 61.000 237.730 65.000 ;
    END
  END la_data_out_core[123]
  PIN la_data_out_core[124]
    DIRECTION INPUT ;
    PORT
      LAYER met2 ;
        RECT 239.290 61.000 239.570 65.000 ;
    END
  END la_data_out_core[124]
  PIN la_data_out_core[125]
    DIRECTION INPUT ;
    PORT
      LAYER met2 ;
        RECT 241.130 61.000 241.410 65.000 ;
    END
  END la_data_out_core[125]
  PIN la_data_out_core[126]
    DIRECTION INPUT ;
    PORT
      LAYER met2 ;
        RECT 242.970 61.000 243.250 65.000 ;
    END
  END la_data_out_core[126]
  PIN la_data_out_core[127]
    DIRECTION INPUT ;
    PORT
      LAYER met2 ;
        RECT 244.810 61.000 245.090 65.000 ;
    END
  END la_data_out_core[127]
  PIN la_data_out_core[12]
    DIRECTION INPUT ;
    PORT
      LAYER met2 ;
        RECT 246.650 61.000 246.930 65.000 ;
    END
  END la_data_out_core[12]
  PIN la_data_out_core[13]
    DIRECTION INPUT ;
    PORT
      LAYER met2 ;
        RECT 248.490 61.000 248.770 65.000 ;
    END
  END la_data_out_core[13]
  PIN la_data_out_core[14]
    DIRECTION INPUT ;
    PORT
      LAYER met2 ;
        RECT 250.330 61.000 250.610 65.000 ;
    END
  END la_data_out_core[14]
  PIN la_data_out_core[15]
    DIRECTION INPUT ;
    PORT
      LAYER met2 ;
        RECT 252.170 61.000 252.450 65.000 ;
    END
  END la_data_out_core[15]
  PIN la_data_out_core[16]
    DIRECTION INPUT ;
    PORT
      LAYER met2 ;
        RECT 254.010 61.000 254.290 65.000 ;
    END
  END la_data_out_core[16]
  PIN la_data_out_core[17]
    DIRECTION INPUT ;
    PORT
      LAYER met2 ;
        RECT 255.850 61.000 256.130 65.000 ;
    END
  END la_data_out_core[17]
  PIN la_data_out_core[18]
    DIRECTION INPUT ;
    PORT
      LAYER met2 ;
        RECT 257.690 61.000 257.970 65.000 ;
    END
  END la_data_out_core[18]
  PIN la_data_out_core[19]
    DIRECTION INPUT ;
    PORT
      LAYER met2 ;
        RECT 259.530 61.000 259.810 65.000 ;
    END
  END la_data_out_core[19]
  PIN la_data_out_core[1]
    DIRECTION INPUT ;
    PORT
      LAYER met2 ;
        RECT 261.370 61.000 261.650 65.000 ;
    END
  END la_data_out_core[1]
  PIN la_data_out_core[20]
    DIRECTION INPUT ;
    PORT
      LAYER met2 ;
        RECT 263.210 61.000 263.490 65.000 ;
    END
  END la_data_out_core[20]
  PIN la_data_out_core[21]
    DIRECTION INPUT ;
    PORT
      LAYER met2 ;
        RECT 265.050 61.000 265.330 65.000 ;
    END
  END la_data_out_core[21]
  PIN la_data_out_core[22]
    DIRECTION INPUT ;
    PORT
      LAYER met2 ;
        RECT 266.890 61.000 267.170 65.000 ;
    END
  END la_data_out_core[22]
  PIN la_data_out_core[23]
    DIRECTION INPUT ;
    PORT
      LAYER met2 ;
        RECT 268.730 61.000 269.010 65.000 ;
    END
  END la_data_out_core[23]
  PIN la_data_out_core[24]
    DIRECTION INPUT ;
    PORT
      LAYER met2 ;
        RECT 270.570 61.000 270.850 65.000 ;
    END
  END la_data_out_core[24]
  PIN la_data_out_core[25]
    DIRECTION INPUT ;
    PORT
      LAYER met2 ;
        RECT 272.410 61.000 272.690 65.000 ;
    END
  END la_data_out_core[25]
  PIN la_data_out_core[26]
    DIRECTION INPUT ;
    PORT
      LAYER met2 ;
        RECT 274.250 61.000 274.530 65.000 ;
    END
  END la_data_out_core[26]
  PIN la_data_out_core[27]
    DIRECTION INPUT ;
    PORT
      LAYER met2 ;
        RECT 276.090 61.000 276.370 65.000 ;
    END
  END la_data_out_core[27]
  PIN la_data_out_core[28]
    DIRECTION INPUT ;
    PORT
      LAYER met2 ;
        RECT 277.930 61.000 278.210 65.000 ;
    END
  END la_data_out_core[28]
  PIN la_data_out_core[29]
    DIRECTION INPUT ;
    PORT
      LAYER met2 ;
        RECT 279.770 61.000 280.050 65.000 ;
    END
  END la_data_out_core[29]
  PIN la_data_out_core[2]
    DIRECTION INPUT ;
    PORT
      LAYER met2 ;
        RECT 281.610 61.000 281.890 65.000 ;
    END
  END la_data_out_core[2]
  PIN la_data_out_core[30]
    DIRECTION INPUT ;
    PORT
      LAYER met2 ;
        RECT 283.450 61.000 283.730 65.000 ;
    END
  END la_data_out_core[30]
  PIN la_data_out_core[31]
    DIRECTION INPUT ;
    PORT
      LAYER met2 ;
        RECT 285.290 61.000 285.570 65.000 ;
    END
  END la_data_out_core[31]
  PIN la_data_out_core[32]
    DIRECTION INPUT ;
    PORT
      LAYER met2 ;
        RECT 287.130 61.000 287.410 65.000 ;
    END
  END la_data_out_core[32]
  PIN la_data_out_core[33]
    DIRECTION INPUT ;
    PORT
      LAYER met2 ;
        RECT 288.970 61.000 289.250 65.000 ;
    END
  END la_data_out_core[33]
  PIN la_data_out_core[34]
    DIRECTION INPUT ;
    PORT
      LAYER met2 ;
        RECT 290.810 61.000 291.090 65.000 ;
    END
  END la_data_out_core[34]
  PIN la_data_out_core[35]
    DIRECTION INPUT ;
    PORT
      LAYER met2 ;
        RECT 292.650 61.000 292.930 65.000 ;
    END
  END la_data_out_core[35]
  PIN la_data_out_core[36]
    DIRECTION INPUT ;
    PORT
      LAYER met2 ;
        RECT 294.490 61.000 294.770 65.000 ;
    END
  END la_data_out_core[36]
  PIN la_data_out_core[37]
    DIRECTION INPUT ;
    PORT
      LAYER met2 ;
        RECT 296.330 61.000 296.610 65.000 ;
    END
  END la_data_out_core[37]
  PIN la_data_out_core[38]
    DIRECTION INPUT ;
    PORT
      LAYER met2 ;
        RECT 298.170 61.000 298.450 65.000 ;
    END
  END la_data_out_core[38]
  PIN la_data_out_core[39]
    DIRECTION INPUT ;
    PORT
      LAYER met2 ;
        RECT 300.010 61.000 300.290 65.000 ;
    END
  END la_data_out_core[39]
  PIN la_data_out_core[3]
    DIRECTION INPUT ;
    PORT
      LAYER met2 ;
        RECT 301.850 61.000 302.130 65.000 ;
    END
  END la_data_out_core[3]
  PIN la_data_out_core[40]
    DIRECTION INPUT ;
    PORT
      LAYER met2 ;
        RECT 303.690 61.000 303.970 65.000 ;
    END
  END la_data_out_core[40]
  PIN la_data_out_core[41]
    DIRECTION INPUT ;
    PORT
      LAYER met2 ;
        RECT 305.530 61.000 305.810 65.000 ;
    END
  END la_data_out_core[41]
  PIN la_data_out_core[42]
    DIRECTION INPUT ;
    PORT
      LAYER met2 ;
        RECT 307.370 61.000 307.650 65.000 ;
    END
  END la_data_out_core[42]
  PIN la_data_out_core[43]
    DIRECTION INPUT ;
    PORT
      LAYER met2 ;
        RECT 309.210 61.000 309.490 65.000 ;
    END
  END la_data_out_core[43]
  PIN la_data_out_core[44]
    DIRECTION INPUT ;
    PORT
      LAYER met2 ;
        RECT 311.050 61.000 311.330 65.000 ;
    END
  END la_data_out_core[44]
  PIN la_data_out_core[45]
    DIRECTION INPUT ;
    PORT
      LAYER met2 ;
        RECT 312.890 61.000 313.170 65.000 ;
    END
  END la_data_out_core[45]
  PIN la_data_out_core[46]
    DIRECTION INPUT ;
    PORT
      LAYER met2 ;
        RECT 314.730 61.000 315.010 65.000 ;
    END
  END la_data_out_core[46]
  PIN la_data_out_core[47]
    DIRECTION INPUT ;
    PORT
      LAYER met2 ;
        RECT 316.570 61.000 316.850 65.000 ;
    END
  END la_data_out_core[47]
  PIN la_data_out_core[48]
    DIRECTION INPUT ;
    PORT
      LAYER met2 ;
        RECT 318.410 61.000 318.690 65.000 ;
    END
  END la_data_out_core[48]
  PIN la_data_out_core[49]
    DIRECTION INPUT ;
    PORT
      LAYER met2 ;
        RECT 254.930 0.000 255.210 4.000 ;
    END
  END la_data_out_core[49]
  PIN la_data_out_core[4]
    DIRECTION INPUT ;
    PORT
      LAYER met2 ;
        RECT 320.250 61.000 320.530 65.000 ;
    END
  END la_data_out_core[4]
  PIN la_data_out_core[50]
    DIRECTION INPUT ;
    PORT
      LAYER met2 ;
        RECT 256.770 0.000 257.050 4.000 ;
    END
  END la_data_out_core[50]
  PIN la_data_out_core[51]
    DIRECTION INPUT ;
    PORT
      LAYER met2 ;
        RECT 322.090 61.000 322.370 65.000 ;
    END
  END la_data_out_core[51]
  PIN la_data_out_core[52]
    DIRECTION INPUT ;
    PORT
      LAYER met2 ;
        RECT 258.610 0.000 258.890 4.000 ;
    END
  END la_data_out_core[52]
  PIN la_data_out_core[53]
    DIRECTION INPUT ;
    PORT
      LAYER met2 ;
        RECT 323.930 61.000 324.210 65.000 ;
    END
  END la_data_out_core[53]
  PIN la_data_out_core[54]
    DIRECTION INPUT ;
    PORT
      LAYER met2 ;
        RECT 260.450 0.000 260.730 4.000 ;
    END
  END la_data_out_core[54]
  PIN la_data_out_core[55]
    DIRECTION INPUT ;
    PORT
      LAYER met2 ;
        RECT 325.770 61.000 326.050 65.000 ;
    END
  END la_data_out_core[55]
  PIN la_data_out_core[56]
    DIRECTION INPUT ;
    PORT
      LAYER met2 ;
        RECT 262.290 0.000 262.570 4.000 ;
    END
  END la_data_out_core[56]
  PIN la_data_out_core[57]
    DIRECTION INPUT ;
    PORT
      LAYER met2 ;
        RECT 327.610 61.000 327.890 65.000 ;
    END
  END la_data_out_core[57]
  PIN la_data_out_core[58]
    DIRECTION INPUT ;
    PORT
      LAYER met2 ;
        RECT 264.130 0.000 264.410 4.000 ;
    END
  END la_data_out_core[58]
  PIN la_data_out_core[59]
    DIRECTION INPUT ;
    PORT
      LAYER met2 ;
        RECT 329.450 61.000 329.730 65.000 ;
    END
  END la_data_out_core[59]
  PIN la_data_out_core[5]
    DIRECTION INPUT ;
    PORT
      LAYER met2 ;
        RECT 265.970 0.000 266.250 4.000 ;
    END
  END la_data_out_core[5]
  PIN la_data_out_core[60]
    DIRECTION INPUT ;
    PORT
      LAYER met2 ;
        RECT 331.290 61.000 331.570 65.000 ;
    END
  END la_data_out_core[60]
  PIN la_data_out_core[61]
    DIRECTION INPUT ;
    PORT
      LAYER met2 ;
        RECT 267.810 0.000 268.090 4.000 ;
    END
  END la_data_out_core[61]
  PIN la_data_out_core[62]
    DIRECTION INPUT ;
    PORT
      LAYER met2 ;
        RECT 333.130 61.000 333.410 65.000 ;
    END
  END la_data_out_core[62]
  PIN la_data_out_core[63]
    DIRECTION INPUT ;
    PORT
      LAYER met2 ;
        RECT 269.650 0.000 269.930 4.000 ;
    END
  END la_data_out_core[63]
  PIN la_data_out_core[64]
    DIRECTION INPUT ;
    PORT
      LAYER met2 ;
        RECT 334.970 61.000 335.250 65.000 ;
    END
  END la_data_out_core[64]
  PIN la_data_out_core[65]
    DIRECTION INPUT ;
    PORT
      LAYER met2 ;
        RECT 271.490 0.000 271.770 4.000 ;
    END
  END la_data_out_core[65]
  PIN la_data_out_core[66]
    DIRECTION INPUT ;
    PORT
      LAYER met2 ;
        RECT 336.810 61.000 337.090 65.000 ;
    END
  END la_data_out_core[66]
  PIN la_data_out_core[67]
    DIRECTION INPUT ;
    PORT
      LAYER met2 ;
        RECT 273.330 0.000 273.610 4.000 ;
    END
  END la_data_out_core[67]
  PIN la_data_out_core[68]
    DIRECTION INPUT ;
    PORT
      LAYER met2 ;
        RECT 338.650 61.000 338.930 65.000 ;
    END
  END la_data_out_core[68]
  PIN la_data_out_core[69]
    DIRECTION INPUT ;
    PORT
      LAYER met2 ;
        RECT 275.170 0.000 275.450 4.000 ;
    END
  END la_data_out_core[69]
  PIN la_data_out_core[6]
    DIRECTION INPUT ;
    PORT
      LAYER met2 ;
        RECT 340.490 61.000 340.770 65.000 ;
    END
  END la_data_out_core[6]
  PIN la_data_out_core[70]
    DIRECTION INPUT ;
    PORT
      LAYER met2 ;
        RECT 277.010 0.000 277.290 4.000 ;
    END
  END la_data_out_core[70]
  PIN la_data_out_core[71]
    DIRECTION INPUT ;
    PORT
      LAYER met2 ;
        RECT 342.330 61.000 342.610 65.000 ;
    END
  END la_data_out_core[71]
  PIN la_data_out_core[72]
    DIRECTION INPUT ;
    PORT
      LAYER met2 ;
        RECT 278.850 0.000 279.130 4.000 ;
    END
  END la_data_out_core[72]
  PIN la_data_out_core[73]
    DIRECTION INPUT ;
    PORT
      LAYER met2 ;
        RECT 344.170 61.000 344.450 65.000 ;
    END
  END la_data_out_core[73]
  PIN la_data_out_core[74]
    DIRECTION INPUT ;
    PORT
      LAYER met2 ;
        RECT 280.690 0.000 280.970 4.000 ;
    END
  END la_data_out_core[74]
  PIN la_data_out_core[75]
    DIRECTION INPUT ;
    PORT
      LAYER met2 ;
        RECT 346.010 61.000 346.290 65.000 ;
    END
  END la_data_out_core[75]
  PIN la_data_out_core[76]
    DIRECTION INPUT ;
    PORT
      LAYER met2 ;
        RECT 282.530 0.000 282.810 4.000 ;
    END
  END la_data_out_core[76]
  PIN la_data_out_core[77]
    DIRECTION INPUT ;
    PORT
      LAYER met2 ;
        RECT 347.850 61.000 348.130 65.000 ;
    END
  END la_data_out_core[77]
  PIN la_data_out_core[78]
    DIRECTION INPUT ;
    PORT
      LAYER met2 ;
        RECT 284.370 0.000 284.650 4.000 ;
    END
  END la_data_out_core[78]
  PIN la_data_out_core[79]
    DIRECTION INPUT ;
    PORT
      LAYER met2 ;
        RECT 349.690 61.000 349.970 65.000 ;
    END
  END la_data_out_core[79]
  PIN la_data_out_core[7]
    DIRECTION INPUT ;
    PORT
      LAYER met2 ;
        RECT 286.210 0.000 286.490 4.000 ;
    END
  END la_data_out_core[7]
  PIN la_data_out_core[80]
    DIRECTION INPUT ;
    PORT
      LAYER met2 ;
        RECT 351.530 61.000 351.810 65.000 ;
    END
  END la_data_out_core[80]
  PIN la_data_out_core[81]
    DIRECTION INPUT ;
    PORT
      LAYER met2 ;
        RECT 288.050 0.000 288.330 4.000 ;
    END
  END la_data_out_core[81]
  PIN la_data_out_core[82]
    DIRECTION INPUT ;
    PORT
      LAYER met2 ;
        RECT 353.370 61.000 353.650 65.000 ;
    END
  END la_data_out_core[82]
  PIN la_data_out_core[83]
    DIRECTION INPUT ;
    PORT
      LAYER met2 ;
        RECT 289.890 0.000 290.170 4.000 ;
    END
  END la_data_out_core[83]
  PIN la_data_out_core[84]
    DIRECTION INPUT ;
    PORT
      LAYER met2 ;
        RECT 355.210 61.000 355.490 65.000 ;
    END
  END la_data_out_core[84]
  PIN la_data_out_core[85]
    DIRECTION INPUT ;
    PORT
      LAYER met2 ;
        RECT 291.730 0.000 292.010 4.000 ;
    END
  END la_data_out_core[85]
  PIN la_data_out_core[86]
    DIRECTION INPUT ;
    PORT
      LAYER met2 ;
        RECT 357.050 61.000 357.330 65.000 ;
    END
  END la_data_out_core[86]
  PIN la_data_out_core[87]
    DIRECTION INPUT ;
    PORT
      LAYER met2 ;
        RECT 293.570 0.000 293.850 4.000 ;
    END
  END la_data_out_core[87]
  PIN la_data_out_core[88]
    DIRECTION INPUT ;
    PORT
      LAYER met2 ;
        RECT 358.890 61.000 359.170 65.000 ;
    END
  END la_data_out_core[88]
  PIN la_data_out_core[89]
    DIRECTION INPUT ;
    PORT
      LAYER met2 ;
        RECT 295.410 0.000 295.690 4.000 ;
    END
  END la_data_out_core[89]
  PIN la_data_out_core[8]
    DIRECTION INPUT ;
    PORT
      LAYER met2 ;
        RECT 360.730 61.000 361.010 65.000 ;
    END
  END la_data_out_core[8]
  PIN la_data_out_core[90]
    DIRECTION INPUT ;
    PORT
      LAYER met2 ;
        RECT 297.250 0.000 297.530 4.000 ;
    END
  END la_data_out_core[90]
  PIN la_data_out_core[91]
    DIRECTION INPUT ;
    PORT
      LAYER met2 ;
        RECT 362.570 61.000 362.850 65.000 ;
    END
  END la_data_out_core[91]
  PIN la_data_out_core[92]
    DIRECTION INPUT ;
    PORT
      LAYER met2 ;
        RECT 299.090 0.000 299.370 4.000 ;
    END
  END la_data_out_core[92]
  PIN la_data_out_core[93]
    DIRECTION INPUT ;
    PORT
      LAYER met2 ;
        RECT 364.410 61.000 364.690 65.000 ;
    END
  END la_data_out_core[93]
  PIN la_data_out_core[94]
    DIRECTION INPUT ;
    PORT
      LAYER met2 ;
        RECT 300.930 0.000 301.210 4.000 ;
    END
  END la_data_out_core[94]
  PIN la_data_out_core[95]
    DIRECTION INPUT ;
    PORT
      LAYER met2 ;
        RECT 366.250 61.000 366.530 65.000 ;
    END
  END la_data_out_core[95]
  PIN la_data_out_core[96]
    DIRECTION INPUT ;
    PORT
      LAYER met2 ;
        RECT 302.770 0.000 303.050 4.000 ;
    END
  END la_data_out_core[96]
  PIN la_data_out_core[97]
    DIRECTION INPUT ;
    PORT
      LAYER met2 ;
        RECT 368.090 61.000 368.370 65.000 ;
    END
  END la_data_out_core[97]
  PIN la_data_out_core[98]
    DIRECTION INPUT ;
    PORT
      LAYER met2 ;
        RECT 304.610 0.000 304.890 4.000 ;
    END
  END la_data_out_core[98]
  PIN la_data_out_core[99]
    DIRECTION INPUT ;
    PORT
      LAYER met2 ;
        RECT 369.930 61.000 370.210 65.000 ;
    END
  END la_data_out_core[99]
  PIN la_data_out_core[9]
    DIRECTION INPUT ;
    PORT
      LAYER met2 ;
        RECT 306.450 0.000 306.730 4.000 ;
    END
  END la_data_out_core[9]
  PIN la_data_out_mprj[0]
    DIRECTION INPUT ;
    PORT
      LAYER met2 ;
        RECT 308.290 0.000 308.570 4.000 ;
    END
  END la_data_out_mprj[0]
  PIN la_data_out_mprj[100]
    DIRECTION INPUT ;
    PORT
      LAYER met2 ;
        RECT 310.130 0.000 310.410 4.000 ;
    END
  END la_data_out_mprj[100]
  PIN la_data_out_mprj[101]
    DIRECTION INPUT ;
    PORT
      LAYER met2 ;
        RECT 311.970 0.000 312.250 4.000 ;
    END
  END la_data_out_mprj[101]
  PIN la_data_out_mprj[102]
    DIRECTION INPUT ;
    PORT
      LAYER met2 ;
        RECT 313.810 0.000 314.090 4.000 ;
    END
  END la_data_out_mprj[102]
  PIN la_data_out_mprj[103]
    DIRECTION INPUT ;
    PORT
      LAYER met2 ;
        RECT 315.650 0.000 315.930 4.000 ;
    END
  END la_data_out_mprj[103]
  PIN la_data_out_mprj[104]
    DIRECTION INPUT ;
    PORT
      LAYER met2 ;
        RECT 317.490 0.000 317.770 4.000 ;
    END
  END la_data_out_mprj[104]
  PIN la_data_out_mprj[105]
    DIRECTION INPUT ;
    PORT
      LAYER met2 ;
        RECT 319.330 0.000 319.610 4.000 ;
    END
  END la_data_out_mprj[105]
  PIN la_data_out_mprj[106]
    DIRECTION INPUT ;
    PORT
      LAYER met2 ;
        RECT 321.170 0.000 321.450 4.000 ;
    END
  END la_data_out_mprj[106]
  PIN la_data_out_mprj[107]
    DIRECTION INPUT ;
    PORT
      LAYER met2 ;
        RECT 323.010 0.000 323.290 4.000 ;
    END
  END la_data_out_mprj[107]
  PIN la_data_out_mprj[108]
    DIRECTION INPUT ;
    PORT
      LAYER met2 ;
        RECT 324.850 0.000 325.130 4.000 ;
    END
  END la_data_out_mprj[108]
  PIN la_data_out_mprj[109]
    DIRECTION INPUT ;
    PORT
      LAYER met2 ;
        RECT 326.690 0.000 326.970 4.000 ;
    END
  END la_data_out_mprj[109]
  PIN la_data_out_mprj[10]
    DIRECTION INPUT ;
    PORT
      LAYER met2 ;
        RECT 328.530 0.000 328.810 4.000 ;
    END
  END la_data_out_mprj[10]
  PIN la_data_out_mprj[110]
    DIRECTION INPUT ;
    PORT
      LAYER met2 ;
        RECT 330.370 0.000 330.650 4.000 ;
    END
  END la_data_out_mprj[110]
  PIN la_data_out_mprj[111]
    DIRECTION INPUT ;
    PORT
      LAYER met2 ;
        RECT 332.210 0.000 332.490 4.000 ;
    END
  END la_data_out_mprj[111]
  PIN la_data_out_mprj[112]
    DIRECTION INPUT ;
    PORT
      LAYER met2 ;
        RECT 334.050 0.000 334.330 4.000 ;
    END
  END la_data_out_mprj[112]
  PIN la_data_out_mprj[113]
    DIRECTION INPUT ;
    PORT
      LAYER met2 ;
        RECT 335.890 0.000 336.170 4.000 ;
    END
  END la_data_out_mprj[113]
  PIN la_data_out_mprj[114]
    DIRECTION INPUT ;
    PORT
      LAYER met2 ;
        RECT 337.730 0.000 338.010 4.000 ;
    END
  END la_data_out_mprj[114]
  PIN la_data_out_mprj[115]
    DIRECTION INPUT ;
    PORT
      LAYER met2 ;
        RECT 339.570 0.000 339.850 4.000 ;
    END
  END la_data_out_mprj[115]
  PIN la_data_out_mprj[116]
    DIRECTION INPUT ;
    PORT
      LAYER met2 ;
        RECT 341.410 0.000 341.690 4.000 ;
    END
  END la_data_out_mprj[116]
  PIN la_data_out_mprj[117]
    DIRECTION INPUT ;
    PORT
      LAYER met2 ;
        RECT 343.250 0.000 343.530 4.000 ;
    END
  END la_data_out_mprj[117]
  PIN la_data_out_mprj[118]
    DIRECTION INPUT ;
    PORT
      LAYER met2 ;
        RECT 345.090 0.000 345.370 4.000 ;
    END
  END la_data_out_mprj[118]
  PIN la_data_out_mprj[119]
    DIRECTION INPUT ;
    PORT
      LAYER met2 ;
        RECT 346.930 0.000 347.210 4.000 ;
    END
  END la_data_out_mprj[119]
  PIN la_data_out_mprj[11]
    DIRECTION INPUT ;
    PORT
      LAYER met2 ;
        RECT 348.770 0.000 349.050 4.000 ;
    END
  END la_data_out_mprj[11]
  PIN la_data_out_mprj[120]
    DIRECTION INPUT ;
    PORT
      LAYER met2 ;
        RECT 350.610 0.000 350.890 4.000 ;
    END
  END la_data_out_mprj[120]
  PIN la_data_out_mprj[121]
    DIRECTION INPUT ;
    PORT
      LAYER met2 ;
        RECT 352.450 0.000 352.730 4.000 ;
    END
  END la_data_out_mprj[121]
  PIN la_data_out_mprj[122]
    DIRECTION INPUT ;
    PORT
      LAYER met2 ;
        RECT 354.290 0.000 354.570 4.000 ;
    END
  END la_data_out_mprj[122]
  PIN la_data_out_mprj[123]
    DIRECTION INPUT ;
    PORT
      LAYER met2 ;
        RECT 356.130 0.000 356.410 4.000 ;
    END
  END la_data_out_mprj[123]
  PIN la_data_out_mprj[124]
    DIRECTION INPUT ;
    PORT
      LAYER met2 ;
        RECT 357.970 0.000 358.250 4.000 ;
    END
  END la_data_out_mprj[124]
  PIN la_data_out_mprj[125]
    DIRECTION INPUT ;
    PORT
      LAYER met2 ;
        RECT 359.810 0.000 360.090 4.000 ;
    END
  END la_data_out_mprj[125]
  PIN la_data_out_mprj[126]
    DIRECTION INPUT ;
    PORT
      LAYER met2 ;
        RECT 361.650 0.000 361.930 4.000 ;
    END
  END la_data_out_mprj[126]
  PIN la_data_out_mprj[127]
    DIRECTION INPUT ;
    PORT
      LAYER met2 ;
        RECT 363.490 0.000 363.770 4.000 ;
    END
  END la_data_out_mprj[127]
  PIN la_data_out_mprj[12]
    DIRECTION INPUT ;
    PORT
      LAYER met2 ;
        RECT 365.330 0.000 365.610 4.000 ;
    END
  END la_data_out_mprj[12]
  PIN la_data_out_mprj[13]
    DIRECTION INPUT ;
    PORT
      LAYER met2 ;
        RECT 367.170 0.000 367.450 4.000 ;
    END
  END la_data_out_mprj[13]
  PIN la_data_out_mprj[14]
    DIRECTION INPUT ;
    PORT
      LAYER met2 ;
        RECT 369.010 0.000 369.290 4.000 ;
    END
  END la_data_out_mprj[14]
  PIN la_data_out_mprj[15]
    DIRECTION INPUT ;
    PORT
      LAYER met2 ;
        RECT 370.850 0.000 371.130 4.000 ;
    END
  END la_data_out_mprj[15]
  PIN la_data_out_mprj[16]
    DIRECTION INPUT ;
    PORT
      LAYER met2 ;
        RECT 372.690 0.000 372.970 4.000 ;
    END
  END la_data_out_mprj[16]
  PIN la_data_out_mprj[17]
    DIRECTION INPUT ;
    PORT
      LAYER met2 ;
        RECT 374.530 0.000 374.810 4.000 ;
    END
  END la_data_out_mprj[17]
  PIN la_data_out_mprj[18]
    DIRECTION INPUT ;
    PORT
      LAYER met2 ;
        RECT 376.370 0.000 376.650 4.000 ;
    END
  END la_data_out_mprj[18]
  PIN la_data_out_mprj[19]
    DIRECTION INPUT ;
    PORT
      LAYER met2 ;
        RECT 378.210 0.000 378.490 4.000 ;
    END
  END la_data_out_mprj[19]
  PIN la_data_out_mprj[1]
    DIRECTION INPUT ;
    PORT
      LAYER met2 ;
        RECT 380.050 0.000 380.330 4.000 ;
    END
  END la_data_out_mprj[1]
  PIN la_data_out_mprj[20]
    DIRECTION INPUT ;
    PORT
      LAYER met2 ;
        RECT 381.890 0.000 382.170 4.000 ;
    END
  END la_data_out_mprj[20]
  PIN la_data_out_mprj[21]
    DIRECTION INPUT ;
    PORT
      LAYER met2 ;
        RECT 383.730 0.000 384.010 4.000 ;
    END
  END la_data_out_mprj[21]
  PIN la_data_out_mprj[22]
    DIRECTION INPUT ;
    PORT
      LAYER met2 ;
        RECT 385.570 0.000 385.850 4.000 ;
    END
  END la_data_out_mprj[22]
  PIN la_data_out_mprj[23]
    DIRECTION INPUT ;
    PORT
      LAYER met2 ;
        RECT 387.410 0.000 387.690 4.000 ;
    END
  END la_data_out_mprj[23]
  PIN la_data_out_mprj[24]
    DIRECTION INPUT ;
    PORT
      LAYER met2 ;
        RECT 389.250 0.000 389.530 4.000 ;
    END
  END la_data_out_mprj[24]
  PIN la_data_out_mprj[25]
    DIRECTION INPUT ;
    PORT
      LAYER met2 ;
        RECT 391.090 0.000 391.370 4.000 ;
    END
  END la_data_out_mprj[25]
  PIN la_data_out_mprj[26]
    DIRECTION INPUT ;
    PORT
      LAYER met2 ;
        RECT 392.930 0.000 393.210 4.000 ;
    END
  END la_data_out_mprj[26]
  PIN la_data_out_mprj[27]
    DIRECTION INPUT ;
    PORT
      LAYER met2 ;
        RECT 394.770 0.000 395.050 4.000 ;
    END
  END la_data_out_mprj[27]
  PIN la_data_out_mprj[28]
    DIRECTION INPUT ;
    PORT
      LAYER met2 ;
        RECT 396.610 0.000 396.890 4.000 ;
    END
  END la_data_out_mprj[28]
  PIN la_data_out_mprj[29]
    DIRECTION INPUT ;
    PORT
      LAYER met2 ;
        RECT 398.450 0.000 398.730 4.000 ;
    END
  END la_data_out_mprj[29]
  PIN la_data_out_mprj[2]
    DIRECTION INPUT ;
    PORT
      LAYER met2 ;
        RECT 400.290 0.000 400.570 4.000 ;
    END
  END la_data_out_mprj[2]
  PIN la_data_out_mprj[30]
    DIRECTION INPUT ;
    PORT
      LAYER met2 ;
        RECT 402.130 0.000 402.410 4.000 ;
    END
  END la_data_out_mprj[30]
  PIN la_data_out_mprj[31]
    DIRECTION INPUT ;
    PORT
      LAYER met2 ;
        RECT 403.970 0.000 404.250 4.000 ;
    END
  END la_data_out_mprj[31]
  PIN la_data_out_mprj[32]
    DIRECTION INPUT ;
    PORT
      LAYER met2 ;
        RECT 405.810 0.000 406.090 4.000 ;
    END
  END la_data_out_mprj[32]
  PIN la_data_out_mprj[33]
    DIRECTION INPUT ;
    PORT
      LAYER met2 ;
        RECT 407.650 0.000 407.930 4.000 ;
    END
  END la_data_out_mprj[33]
  PIN la_data_out_mprj[34]
    DIRECTION INPUT ;
    PORT
      LAYER met2 ;
        RECT 409.490 0.000 409.770 4.000 ;
    END
  END la_data_out_mprj[34]
  PIN la_data_out_mprj[35]
    DIRECTION INPUT ;
    PORT
      LAYER met2 ;
        RECT 411.330 0.000 411.610 4.000 ;
    END
  END la_data_out_mprj[35]
  PIN la_data_out_mprj[36]
    DIRECTION INPUT ;
    PORT
      LAYER met2 ;
        RECT 413.170 0.000 413.450 4.000 ;
    END
  END la_data_out_mprj[36]
  PIN la_data_out_mprj[37]
    DIRECTION INPUT ;
    PORT
      LAYER met2 ;
        RECT 415.010 0.000 415.290 4.000 ;
    END
  END la_data_out_mprj[37]
  PIN la_data_out_mprj[38]
    DIRECTION INPUT ;
    PORT
      LAYER met2 ;
        RECT 416.850 0.000 417.130 4.000 ;
    END
  END la_data_out_mprj[38]
  PIN la_data_out_mprj[39]
    DIRECTION INPUT ;
    PORT
      LAYER met2 ;
        RECT 418.690 0.000 418.970 4.000 ;
    END
  END la_data_out_mprj[39]
  PIN la_data_out_mprj[3]
    DIRECTION INPUT ;
    PORT
      LAYER met2 ;
        RECT 420.530 0.000 420.810 4.000 ;
    END
  END la_data_out_mprj[3]
  PIN la_data_out_mprj[40]
    DIRECTION INPUT ;
    PORT
      LAYER met2 ;
        RECT 422.370 0.000 422.650 4.000 ;
    END
  END la_data_out_mprj[40]
  PIN la_data_out_mprj[41]
    DIRECTION INPUT ;
    PORT
      LAYER met2 ;
        RECT 424.210 0.000 424.490 4.000 ;
    END
  END la_data_out_mprj[41]
  PIN la_data_out_mprj[42]
    DIRECTION INPUT ;
    PORT
      LAYER met2 ;
        RECT 426.050 0.000 426.330 4.000 ;
    END
  END la_data_out_mprj[42]
  PIN la_data_out_mprj[43]
    DIRECTION INPUT ;
    PORT
      LAYER met2 ;
        RECT 427.890 0.000 428.170 4.000 ;
    END
  END la_data_out_mprj[43]
  PIN la_data_out_mprj[44]
    DIRECTION INPUT ;
    PORT
      LAYER met2 ;
        RECT 429.730 0.000 430.010 4.000 ;
    END
  END la_data_out_mprj[44]
  PIN la_data_out_mprj[45]
    DIRECTION INPUT ;
    PORT
      LAYER met2 ;
        RECT 431.570 0.000 431.850 4.000 ;
    END
  END la_data_out_mprj[45]
  PIN la_data_out_mprj[46]
    DIRECTION INPUT ;
    PORT
      LAYER met2 ;
        RECT 433.410 0.000 433.690 4.000 ;
    END
  END la_data_out_mprj[46]
  PIN la_data_out_mprj[47]
    DIRECTION INPUT ;
    PORT
      LAYER met2 ;
        RECT 435.250 0.000 435.530 4.000 ;
    END
  END la_data_out_mprj[47]
  PIN la_data_out_mprj[48]
    DIRECTION INPUT ;
    PORT
      LAYER met2 ;
        RECT 371.770 61.000 372.050 65.000 ;
    END
  END la_data_out_mprj[48]
  PIN la_data_out_mprj[49]
    DIRECTION INPUT ;
    PORT
      LAYER met2 ;
        RECT 437.090 0.000 437.370 4.000 ;
    END
  END la_data_out_mprj[49]
  PIN la_data_out_mprj[4]
    DIRECTION INPUT ;
    PORT
      LAYER met2 ;
        RECT 373.610 61.000 373.890 65.000 ;
    END
  END la_data_out_mprj[4]
  PIN la_data_out_mprj[50]
    DIRECTION INPUT ;
    PORT
      LAYER met2 ;
        RECT 438.930 0.000 439.210 4.000 ;
    END
  END la_data_out_mprj[50]
  PIN la_data_out_mprj[51]
    DIRECTION INPUT ;
    PORT
      LAYER met2 ;
        RECT 375.450 61.000 375.730 65.000 ;
    END
  END la_data_out_mprj[51]
  PIN la_data_out_mprj[52]
    DIRECTION INPUT ;
    PORT
      LAYER met2 ;
        RECT 440.770 0.000 441.050 4.000 ;
    END
  END la_data_out_mprj[52]
  PIN la_data_out_mprj[53]
    DIRECTION INPUT ;
    PORT
      LAYER met2 ;
        RECT 377.290 61.000 377.570 65.000 ;
    END
  END la_data_out_mprj[53]
  PIN la_data_out_mprj[54]
    DIRECTION INPUT ;
    PORT
      LAYER met2 ;
        RECT 442.610 0.000 442.890 4.000 ;
    END
  END la_data_out_mprj[54]
  PIN la_data_out_mprj[55]
    DIRECTION INPUT ;
    PORT
      LAYER met2 ;
        RECT 379.130 61.000 379.410 65.000 ;
    END
  END la_data_out_mprj[55]
  PIN la_data_out_mprj[56]
    DIRECTION INPUT ;
    PORT
      LAYER met2 ;
        RECT 444.450 0.000 444.730 4.000 ;
    END
  END la_data_out_mprj[56]
  PIN la_data_out_mprj[57]
    DIRECTION INPUT ;
    PORT
      LAYER met2 ;
        RECT 380.970 61.000 381.250 65.000 ;
    END
  END la_data_out_mprj[57]
  PIN la_data_out_mprj[58]
    DIRECTION INPUT ;
    PORT
      LAYER met2 ;
        RECT 446.290 0.000 446.570 4.000 ;
    END
  END la_data_out_mprj[58]
  PIN la_data_out_mprj[59]
    DIRECTION INPUT ;
    PORT
      LAYER met2 ;
        RECT 382.810 61.000 383.090 65.000 ;
    END
  END la_data_out_mprj[59]
  PIN la_data_out_mprj[5]
    DIRECTION INPUT ;
    PORT
      LAYER met2 ;
        RECT 448.130 0.000 448.410 4.000 ;
    END
  END la_data_out_mprj[5]
  PIN la_data_out_mprj[60]
    DIRECTION INPUT ;
    PORT
      LAYER met2 ;
        RECT 384.650 61.000 384.930 65.000 ;
    END
  END la_data_out_mprj[60]
  PIN la_data_out_mprj[61]
    DIRECTION INPUT ;
    PORT
      LAYER met2 ;
        RECT 449.970 0.000 450.250 4.000 ;
    END
  END la_data_out_mprj[61]
  PIN la_data_out_mprj[62]
    DIRECTION INPUT ;
    PORT
      LAYER met2 ;
        RECT 386.490 61.000 386.770 65.000 ;
    END
  END la_data_out_mprj[62]
  PIN la_data_out_mprj[63]
    DIRECTION INPUT ;
    PORT
      LAYER met2 ;
        RECT 451.810 0.000 452.090 4.000 ;
    END
  END la_data_out_mprj[63]
  PIN la_data_out_mprj[64]
    DIRECTION INPUT ;
    PORT
      LAYER met2 ;
        RECT 388.330 61.000 388.610 65.000 ;
    END
  END la_data_out_mprj[64]
  PIN la_data_out_mprj[65]
    DIRECTION INPUT ;
    PORT
      LAYER met2 ;
        RECT 453.650 0.000 453.930 4.000 ;
    END
  END la_data_out_mprj[65]
  PIN la_data_out_mprj[66]
    DIRECTION INPUT ;
    PORT
      LAYER met2 ;
        RECT 390.170 61.000 390.450 65.000 ;
    END
  END la_data_out_mprj[66]
  PIN la_data_out_mprj[67]
    DIRECTION INPUT ;
    PORT
      LAYER met2 ;
        RECT 455.490 0.000 455.770 4.000 ;
    END
  END la_data_out_mprj[67]
  PIN la_data_out_mprj[68]
    DIRECTION INPUT ;
    PORT
      LAYER met2 ;
        RECT 392.010 61.000 392.290 65.000 ;
    END
  END la_data_out_mprj[68]
  PIN la_data_out_mprj[69]
    DIRECTION INPUT ;
    PORT
      LAYER met2 ;
        RECT 457.330 0.000 457.610 4.000 ;
    END
  END la_data_out_mprj[69]
  PIN la_data_out_mprj[6]
    DIRECTION INPUT ;
    PORT
      LAYER met2 ;
        RECT 393.850 61.000 394.130 65.000 ;
    END
  END la_data_out_mprj[6]
  PIN la_data_out_mprj[70]
    DIRECTION INPUT ;
    PORT
      LAYER met2 ;
        RECT 459.170 0.000 459.450 4.000 ;
    END
  END la_data_out_mprj[70]
  PIN la_data_out_mprj[71]
    DIRECTION INPUT ;
    PORT
      LAYER met2 ;
        RECT 395.690 61.000 395.970 65.000 ;
    END
  END la_data_out_mprj[71]
  PIN la_data_out_mprj[72]
    DIRECTION INPUT ;
    PORT
      LAYER met2 ;
        RECT 461.010 0.000 461.290 4.000 ;
    END
  END la_data_out_mprj[72]
  PIN la_data_out_mprj[73]
    DIRECTION INPUT ;
    PORT
      LAYER met2 ;
        RECT 397.530 61.000 397.810 65.000 ;
    END
  END la_data_out_mprj[73]
  PIN la_data_out_mprj[74]
    DIRECTION INPUT ;
    PORT
      LAYER met2 ;
        RECT 462.850 0.000 463.130 4.000 ;
    END
  END la_data_out_mprj[74]
  PIN la_data_out_mprj[75]
    DIRECTION INPUT ;
    PORT
      LAYER met2 ;
        RECT 399.370 61.000 399.650 65.000 ;
    END
  END la_data_out_mprj[75]
  PIN la_data_out_mprj[76]
    DIRECTION INPUT ;
    PORT
      LAYER met2 ;
        RECT 464.690 0.000 464.970 4.000 ;
    END
  END la_data_out_mprj[76]
  PIN la_data_out_mprj[77]
    DIRECTION INPUT ;
    PORT
      LAYER met2 ;
        RECT 401.210 61.000 401.490 65.000 ;
    END
  END la_data_out_mprj[77]
  PIN la_data_out_mprj[78]
    DIRECTION INPUT ;
    PORT
      LAYER met2 ;
        RECT 466.530 0.000 466.810 4.000 ;
    END
  END la_data_out_mprj[78]
  PIN la_data_out_mprj[79]
    DIRECTION INPUT ;
    PORT
      LAYER met2 ;
        RECT 403.050 61.000 403.330 65.000 ;
    END
  END la_data_out_mprj[79]
  PIN la_data_out_mprj[7]
    DIRECTION INPUT ;
    PORT
      LAYER met2 ;
        RECT 468.370 0.000 468.650 4.000 ;
    END
  END la_data_out_mprj[7]
  PIN la_data_out_mprj[80]
    DIRECTION INPUT ;
    PORT
      LAYER met2 ;
        RECT 404.890 61.000 405.170 65.000 ;
    END
  END la_data_out_mprj[80]
  PIN la_data_out_mprj[81]
    DIRECTION INPUT ;
    PORT
      LAYER met2 ;
        RECT 470.210 0.000 470.490 4.000 ;
    END
  END la_data_out_mprj[81]
  PIN la_data_out_mprj[82]
    DIRECTION INPUT ;
    PORT
      LAYER met2 ;
        RECT 406.730 61.000 407.010 65.000 ;
    END
  END la_data_out_mprj[82]
  PIN la_data_out_mprj[83]
    DIRECTION INPUT ;
    PORT
      LAYER met2 ;
        RECT 472.050 0.000 472.330 4.000 ;
    END
  END la_data_out_mprj[83]
  PIN la_data_out_mprj[84]
    DIRECTION INPUT ;
    PORT
      LAYER met2 ;
        RECT 408.570 61.000 408.850 65.000 ;
    END
  END la_data_out_mprj[84]
  PIN la_data_out_mprj[85]
    DIRECTION INPUT ;
    PORT
      LAYER met2 ;
        RECT 473.890 0.000 474.170 4.000 ;
    END
  END la_data_out_mprj[85]
  PIN la_data_out_mprj[86]
    DIRECTION INPUT ;
    PORT
      LAYER met2 ;
        RECT 410.410 61.000 410.690 65.000 ;
    END
  END la_data_out_mprj[86]
  PIN la_data_out_mprj[87]
    DIRECTION INPUT ;
    PORT
      LAYER met2 ;
        RECT 475.730 0.000 476.010 4.000 ;
    END
  END la_data_out_mprj[87]
  PIN la_data_out_mprj[88]
    DIRECTION INPUT ;
    PORT
      LAYER met2 ;
        RECT 412.250 61.000 412.530 65.000 ;
    END
  END la_data_out_mprj[88]
  PIN la_data_out_mprj[89]
    DIRECTION INPUT ;
    PORT
      LAYER met2 ;
        RECT 477.570 0.000 477.850 4.000 ;
    END
  END la_data_out_mprj[89]
  PIN la_data_out_mprj[8]
    DIRECTION INPUT ;
    PORT
      LAYER met2 ;
        RECT 414.090 61.000 414.370 65.000 ;
    END
  END la_data_out_mprj[8]
  PIN la_data_out_mprj[90]
    DIRECTION INPUT ;
    PORT
      LAYER met2 ;
        RECT 479.410 0.000 479.690 4.000 ;
    END
  END la_data_out_mprj[90]
  PIN la_data_out_mprj[91]
    DIRECTION INPUT ;
    PORT
      LAYER met2 ;
        RECT 415.930 61.000 416.210 65.000 ;
    END
  END la_data_out_mprj[91]
  PIN la_data_out_mprj[92]
    DIRECTION INPUT ;
    PORT
      LAYER met2 ;
        RECT 481.250 0.000 481.530 4.000 ;
    END
  END la_data_out_mprj[92]
  PIN la_data_out_mprj[93]
    DIRECTION INPUT ;
    PORT
      LAYER met2 ;
        RECT 417.770 61.000 418.050 65.000 ;
    END
  END la_data_out_mprj[93]
  PIN la_data_out_mprj[94]
    DIRECTION INPUT ;
    PORT
      LAYER met2 ;
        RECT 483.090 0.000 483.370 4.000 ;
    END
  END la_data_out_mprj[94]
  PIN la_data_out_mprj[95]
    DIRECTION INPUT ;
    PORT
      LAYER met2 ;
        RECT 419.610 61.000 419.890 65.000 ;
    END
  END la_data_out_mprj[95]
  PIN la_data_out_mprj[96]
    DIRECTION INPUT ;
    PORT
      LAYER met2 ;
        RECT 484.930 0.000 485.210 4.000 ;
    END
  END la_data_out_mprj[96]
  PIN la_data_out_mprj[97]
    DIRECTION INPUT ;
    PORT
      LAYER met2 ;
        RECT 421.450 61.000 421.730 65.000 ;
    END
  END la_data_out_mprj[97]
  PIN la_data_out_mprj[98]
    DIRECTION INPUT ;
    PORT
      LAYER met2 ;
        RECT 486.770 0.000 487.050 4.000 ;
    END
  END la_data_out_mprj[98]
  PIN la_data_out_mprj[99]
    DIRECTION INPUT ;
    PORT
      LAYER met2 ;
        RECT 423.290 61.000 423.570 65.000 ;
    END
  END la_data_out_mprj[99]
  PIN la_data_out_mprj[9]
    DIRECTION INPUT ;
    PORT
      LAYER met2 ;
        RECT 488.610 0.000 488.890 4.000 ;
    END
  END la_data_out_mprj[9]
  PIN la_oen_core[0]
    DIRECTION OUTPUT TRISTATE ;
    PORT
      LAYER met2 ;
        RECT 425.130 61.000 425.410 65.000 ;
    END
  END la_oen_core[0]
  PIN la_oen_core[100]
    DIRECTION OUTPUT TRISTATE ;
    PORT
      LAYER met2 ;
        RECT 426.970 61.000 427.250 65.000 ;
    END
  END la_oen_core[100]
  PIN la_oen_core[101]
    DIRECTION OUTPUT TRISTATE ;
    PORT
      LAYER met2 ;
        RECT 428.810 61.000 429.090 65.000 ;
    END
  END la_oen_core[101]
  PIN la_oen_core[102]
    DIRECTION OUTPUT TRISTATE ;
    PORT
      LAYER met2 ;
        RECT 430.650 61.000 430.930 65.000 ;
    END
  END la_oen_core[102]
  PIN la_oen_core[103]
    DIRECTION OUTPUT TRISTATE ;
    PORT
      LAYER met2 ;
        RECT 432.490 61.000 432.770 65.000 ;
    END
  END la_oen_core[103]
  PIN la_oen_core[104]
    DIRECTION OUTPUT TRISTATE ;
    PORT
      LAYER met2 ;
        RECT 434.330 61.000 434.610 65.000 ;
    END
  END la_oen_core[104]
  PIN la_oen_core[105]
    DIRECTION OUTPUT TRISTATE ;
    PORT
      LAYER met2 ;
        RECT 436.170 61.000 436.450 65.000 ;
    END
  END la_oen_core[105]
  PIN la_oen_core[106]
    DIRECTION OUTPUT TRISTATE ;
    PORT
      LAYER met2 ;
        RECT 438.010 61.000 438.290 65.000 ;
    END
  END la_oen_core[106]
  PIN la_oen_core[107]
    DIRECTION OUTPUT TRISTATE ;
    PORT
      LAYER met2 ;
        RECT 439.850 61.000 440.130 65.000 ;
    END
  END la_oen_core[107]
  PIN la_oen_core[108]
    DIRECTION OUTPUT TRISTATE ;
    PORT
      LAYER met2 ;
        RECT 441.690 61.000 441.970 65.000 ;
    END
  END la_oen_core[108]
  PIN la_oen_core[109]
    DIRECTION OUTPUT TRISTATE ;
    PORT
      LAYER met2 ;
        RECT 443.530 61.000 443.810 65.000 ;
    END
  END la_oen_core[109]
  PIN la_oen_core[10]
    DIRECTION OUTPUT TRISTATE ;
    PORT
      LAYER met2 ;
        RECT 445.370 61.000 445.650 65.000 ;
    END
  END la_oen_core[10]
  PIN la_oen_core[110]
    DIRECTION OUTPUT TRISTATE ;
    PORT
      LAYER met2 ;
        RECT 447.210 61.000 447.490 65.000 ;
    END
  END la_oen_core[110]
  PIN la_oen_core[111]
    DIRECTION OUTPUT TRISTATE ;
    PORT
      LAYER met2 ;
        RECT 449.050 61.000 449.330 65.000 ;
    END
  END la_oen_core[111]
  PIN la_oen_core[112]
    DIRECTION OUTPUT TRISTATE ;
    PORT
      LAYER met2 ;
        RECT 450.890 61.000 451.170 65.000 ;
    END
  END la_oen_core[112]
  PIN la_oen_core[113]
    DIRECTION OUTPUT TRISTATE ;
    PORT
      LAYER met2 ;
        RECT 452.730 61.000 453.010 65.000 ;
    END
  END la_oen_core[113]
  PIN la_oen_core[114]
    DIRECTION OUTPUT TRISTATE ;
    PORT
      LAYER met2 ;
        RECT 454.570 61.000 454.850 65.000 ;
    END
  END la_oen_core[114]
  PIN la_oen_core[115]
    DIRECTION OUTPUT TRISTATE ;
    PORT
      LAYER met2 ;
        RECT 456.410 61.000 456.690 65.000 ;
    END
  END la_oen_core[115]
  PIN la_oen_core[116]
    DIRECTION OUTPUT TRISTATE ;
    PORT
      LAYER met2 ;
        RECT 458.250 61.000 458.530 65.000 ;
    END
  END la_oen_core[116]
  PIN la_oen_core[117]
    DIRECTION OUTPUT TRISTATE ;
    PORT
      LAYER met2 ;
        RECT 460.090 61.000 460.370 65.000 ;
    END
  END la_oen_core[117]
  PIN la_oen_core[118]
    DIRECTION OUTPUT TRISTATE ;
    PORT
      LAYER met2 ;
        RECT 461.930 61.000 462.210 65.000 ;
    END
  END la_oen_core[118]
  PIN la_oen_core[119]
    DIRECTION OUTPUT TRISTATE ;
    PORT
      LAYER met2 ;
        RECT 463.770 61.000 464.050 65.000 ;
    END
  END la_oen_core[119]
  PIN la_oen_core[11]
    DIRECTION OUTPUT TRISTATE ;
    PORT
      LAYER met2 ;
        RECT 465.610 61.000 465.890 65.000 ;
    END
  END la_oen_core[11]
  PIN la_oen_core[120]
    DIRECTION OUTPUT TRISTATE ;
    PORT
      LAYER met2 ;
        RECT 467.450 61.000 467.730 65.000 ;
    END
  END la_oen_core[120]
  PIN la_oen_core[121]
    DIRECTION OUTPUT TRISTATE ;
    PORT
      LAYER met2 ;
        RECT 469.290 61.000 469.570 65.000 ;
    END
  END la_oen_core[121]
  PIN la_oen_core[122]
    DIRECTION OUTPUT TRISTATE ;
    PORT
      LAYER met2 ;
        RECT 471.130 61.000 471.410 65.000 ;
    END
  END la_oen_core[122]
  PIN la_oen_core[123]
    DIRECTION OUTPUT TRISTATE ;
    PORT
      LAYER met2 ;
        RECT 472.970 61.000 473.250 65.000 ;
    END
  END la_oen_core[123]
  PIN la_oen_core[124]
    DIRECTION OUTPUT TRISTATE ;
    PORT
      LAYER met2 ;
        RECT 474.810 61.000 475.090 65.000 ;
    END
  END la_oen_core[124]
  PIN la_oen_core[125]
    DIRECTION OUTPUT TRISTATE ;
    PORT
      LAYER met2 ;
        RECT 476.650 61.000 476.930 65.000 ;
    END
  END la_oen_core[125]
  PIN la_oen_core[126]
    DIRECTION OUTPUT TRISTATE ;
    PORT
      LAYER met2 ;
        RECT 478.490 61.000 478.770 65.000 ;
    END
  END la_oen_core[126]
  PIN la_oen_core[127]
    DIRECTION OUTPUT TRISTATE ;
    PORT
      LAYER met2 ;
        RECT 480.330 61.000 480.610 65.000 ;
    END
  END la_oen_core[127]
  PIN la_oen_core[12]
    DIRECTION OUTPUT TRISTATE ;
    PORT
      LAYER met2 ;
        RECT 482.170 61.000 482.450 65.000 ;
    END
  END la_oen_core[12]
  PIN la_oen_core[13]
    DIRECTION OUTPUT TRISTATE ;
    PORT
      LAYER met2 ;
        RECT 484.010 61.000 484.290 65.000 ;
    END
  END la_oen_core[13]
  PIN la_oen_core[14]
    DIRECTION OUTPUT TRISTATE ;
    PORT
      LAYER met2 ;
        RECT 485.850 61.000 486.130 65.000 ;
    END
  END la_oen_core[14]
  PIN la_oen_core[15]
    DIRECTION OUTPUT TRISTATE ;
    PORT
      LAYER met2 ;
        RECT 487.690 61.000 487.970 65.000 ;
    END
  END la_oen_core[15]
  PIN la_oen_core[16]
    DIRECTION OUTPUT TRISTATE ;
    PORT
      LAYER met2 ;
        RECT 489.530 61.000 489.810 65.000 ;
    END
  END la_oen_core[16]
  PIN la_oen_core[17]
    DIRECTION OUTPUT TRISTATE ;
    PORT
      LAYER met2 ;
        RECT 491.370 61.000 491.650 65.000 ;
    END
  END la_oen_core[17]
  PIN la_oen_core[18]
    DIRECTION OUTPUT TRISTATE ;
    PORT
      LAYER met2 ;
        RECT 493.210 61.000 493.490 65.000 ;
    END
  END la_oen_core[18]
  PIN la_oen_core[19]
    DIRECTION OUTPUT TRISTATE ;
    PORT
      LAYER met2 ;
        RECT 495.050 61.000 495.330 65.000 ;
    END
  END la_oen_core[19]
  PIN la_oen_core[1]
    DIRECTION OUTPUT TRISTATE ;
    PORT
      LAYER met2 ;
        RECT 496.890 61.000 497.170 65.000 ;
    END
  END la_oen_core[1]
  PIN la_oen_core[20]
    DIRECTION OUTPUT TRISTATE ;
    PORT
      LAYER met2 ;
        RECT 498.730 61.000 499.010 65.000 ;
    END
  END la_oen_core[20]
  PIN la_oen_core[21]
    DIRECTION OUTPUT TRISTATE ;
    PORT
      LAYER met2 ;
        RECT 500.570 61.000 500.850 65.000 ;
    END
  END la_oen_core[21]
  PIN la_oen_core[22]
    DIRECTION OUTPUT TRISTATE ;
    PORT
      LAYER met2 ;
        RECT 502.410 61.000 502.690 65.000 ;
    END
  END la_oen_core[22]
  PIN la_oen_core[23]
    DIRECTION OUTPUT TRISTATE ;
    PORT
      LAYER met2 ;
        RECT 504.250 61.000 504.530 65.000 ;
    END
  END la_oen_core[23]
  PIN la_oen_core[24]
    DIRECTION OUTPUT TRISTATE ;
    PORT
      LAYER met2 ;
        RECT 506.090 61.000 506.370 65.000 ;
    END
  END la_oen_core[24]
  PIN la_oen_core[25]
    DIRECTION OUTPUT TRISTATE ;
    PORT
      LAYER met2 ;
        RECT 507.930 61.000 508.210 65.000 ;
    END
  END la_oen_core[25]
  PIN la_oen_core[26]
    DIRECTION OUTPUT TRISTATE ;
    PORT
      LAYER met2 ;
        RECT 509.770 61.000 510.050 65.000 ;
    END
  END la_oen_core[26]
  PIN la_oen_core[27]
    DIRECTION OUTPUT TRISTATE ;
    PORT
      LAYER met2 ;
        RECT 511.610 61.000 511.890 65.000 ;
    END
  END la_oen_core[27]
  PIN la_oen_core[28]
    DIRECTION OUTPUT TRISTATE ;
    PORT
      LAYER met2 ;
        RECT 513.450 61.000 513.730 65.000 ;
    END
  END la_oen_core[28]
  PIN la_oen_core[29]
    DIRECTION OUTPUT TRISTATE ;
    PORT
      LAYER met2 ;
        RECT 515.290 61.000 515.570 65.000 ;
    END
  END la_oen_core[29]
  PIN la_oen_core[2]
    DIRECTION OUTPUT TRISTATE ;
    PORT
      LAYER met2 ;
        RECT 517.130 61.000 517.410 65.000 ;
    END
  END la_oen_core[2]
  PIN la_oen_core[30]
    DIRECTION OUTPUT TRISTATE ;
    PORT
      LAYER met2 ;
        RECT 518.970 61.000 519.250 65.000 ;
    END
  END la_oen_core[30]
  PIN la_oen_core[31]
    DIRECTION OUTPUT TRISTATE ;
    PORT
      LAYER met2 ;
        RECT 520.810 61.000 521.090 65.000 ;
    END
  END la_oen_core[31]
  PIN la_oen_core[32]
    DIRECTION OUTPUT TRISTATE ;
    PORT
      LAYER met2 ;
        RECT 522.650 61.000 522.930 65.000 ;
    END
  END la_oen_core[32]
  PIN la_oen_core[33]
    DIRECTION OUTPUT TRISTATE ;
    PORT
      LAYER met2 ;
        RECT 524.490 61.000 524.770 65.000 ;
    END
  END la_oen_core[33]
  PIN la_oen_core[34]
    DIRECTION OUTPUT TRISTATE ;
    PORT
      LAYER met2 ;
        RECT 526.330 61.000 526.610 65.000 ;
    END
  END la_oen_core[34]
  PIN la_oen_core[35]
    DIRECTION OUTPUT TRISTATE ;
    PORT
      LAYER met2 ;
        RECT 528.170 61.000 528.450 65.000 ;
    END
  END la_oen_core[35]
  PIN la_oen_core[36]
    DIRECTION OUTPUT TRISTATE ;
    PORT
      LAYER met2 ;
        RECT 530.010 61.000 530.290 65.000 ;
    END
  END la_oen_core[36]
  PIN la_oen_core[37]
    DIRECTION OUTPUT TRISTATE ;
    PORT
      LAYER met2 ;
        RECT 531.850 61.000 532.130 65.000 ;
    END
  END la_oen_core[37]
  PIN la_oen_core[38]
    DIRECTION OUTPUT TRISTATE ;
    PORT
      LAYER met2 ;
        RECT 533.690 61.000 533.970 65.000 ;
    END
  END la_oen_core[38]
  PIN la_oen_core[39]
    DIRECTION OUTPUT TRISTATE ;
    PORT
      LAYER met2 ;
        RECT 535.530 61.000 535.810 65.000 ;
    END
  END la_oen_core[39]
  PIN la_oen_core[3]
    DIRECTION OUTPUT TRISTATE ;
    PORT
      LAYER met2 ;
        RECT 537.370 61.000 537.650 65.000 ;
    END
  END la_oen_core[3]
  PIN la_oen_core[40]
    DIRECTION OUTPUT TRISTATE ;
    PORT
      LAYER met2 ;
        RECT 539.210 61.000 539.490 65.000 ;
    END
  END la_oen_core[40]
  PIN la_oen_core[41]
    DIRECTION OUTPUT TRISTATE ;
    PORT
      LAYER met2 ;
        RECT 541.050 61.000 541.330 65.000 ;
    END
  END la_oen_core[41]
  PIN la_oen_core[42]
    DIRECTION OUTPUT TRISTATE ;
    PORT
      LAYER met2 ;
        RECT 542.890 61.000 543.170 65.000 ;
    END
  END la_oen_core[42]
  PIN la_oen_core[43]
    DIRECTION OUTPUT TRISTATE ;
    PORT
      LAYER met2 ;
        RECT 544.730 61.000 545.010 65.000 ;
    END
  END la_oen_core[43]
  PIN la_oen_core[44]
    DIRECTION OUTPUT TRISTATE ;
    PORT
      LAYER met2 ;
        RECT 546.570 61.000 546.850 65.000 ;
    END
  END la_oen_core[44]
  PIN la_oen_core[45]
    DIRECTION OUTPUT TRISTATE ;
    PORT
      LAYER met2 ;
        RECT 548.410 61.000 548.690 65.000 ;
    END
  END la_oen_core[45]
  PIN la_oen_core[46]
    DIRECTION OUTPUT TRISTATE ;
    PORT
      LAYER met2 ;
        RECT 550.250 61.000 550.530 65.000 ;
    END
  END la_oen_core[46]
  PIN la_oen_core[47]
    DIRECTION OUTPUT TRISTATE ;
    PORT
      LAYER met2 ;
        RECT 552.090 61.000 552.370 65.000 ;
    END
  END la_oen_core[47]
  PIN la_oen_core[48]
    DIRECTION OUTPUT TRISTATE ;
    PORT
      LAYER met2 ;
        RECT 553.930 61.000 554.210 65.000 ;
    END
  END la_oen_core[48]
  PIN la_oen_core[49]
    DIRECTION OUTPUT TRISTATE ;
    PORT
      LAYER met2 ;
        RECT 490.450 0.000 490.730 4.000 ;
    END
  END la_oen_core[49]
  PIN la_oen_core[4]
    DIRECTION OUTPUT TRISTATE ;
    PORT
      LAYER met2 ;
        RECT 555.770 61.000 556.050 65.000 ;
    END
  END la_oen_core[4]
  PIN la_oen_core[50]
    DIRECTION OUTPUT TRISTATE ;
    PORT
      LAYER met2 ;
        RECT 492.290 0.000 492.570 4.000 ;
    END
  END la_oen_core[50]
  PIN la_oen_core[51]
    DIRECTION OUTPUT TRISTATE ;
    PORT
      LAYER met2 ;
        RECT 557.610 61.000 557.890 65.000 ;
    END
  END la_oen_core[51]
  PIN la_oen_core[52]
    DIRECTION OUTPUT TRISTATE ;
    PORT
      LAYER met2 ;
        RECT 494.130 0.000 494.410 4.000 ;
    END
  END la_oen_core[52]
  PIN la_oen_core[53]
    DIRECTION OUTPUT TRISTATE ;
    PORT
      LAYER met2 ;
        RECT 559.450 61.000 559.730 65.000 ;
    END
  END la_oen_core[53]
  PIN la_oen_core[54]
    DIRECTION OUTPUT TRISTATE ;
    PORT
      LAYER met2 ;
        RECT 495.970 0.000 496.250 4.000 ;
    END
  END la_oen_core[54]
  PIN la_oen_core[55]
    DIRECTION OUTPUT TRISTATE ;
    PORT
      LAYER met2 ;
        RECT 561.290 61.000 561.570 65.000 ;
    END
  END la_oen_core[55]
  PIN la_oen_core[56]
    DIRECTION OUTPUT TRISTATE ;
    PORT
      LAYER met2 ;
        RECT 497.810 0.000 498.090 4.000 ;
    END
  END la_oen_core[56]
  PIN la_oen_core[57]
    DIRECTION OUTPUT TRISTATE ;
    PORT
      LAYER met2 ;
        RECT 563.130 61.000 563.410 65.000 ;
    END
  END la_oen_core[57]
  PIN la_oen_core[58]
    DIRECTION OUTPUT TRISTATE ;
    PORT
      LAYER met2 ;
        RECT 499.650 0.000 499.930 4.000 ;
    END
  END la_oen_core[58]
  PIN la_oen_core[59]
    DIRECTION OUTPUT TRISTATE ;
    PORT
      LAYER met2 ;
        RECT 564.970 61.000 565.250 65.000 ;
    END
  END la_oen_core[59]
  PIN la_oen_core[5]
    DIRECTION OUTPUT TRISTATE ;
    PORT
      LAYER met2 ;
        RECT 501.490 0.000 501.770 4.000 ;
    END
  END la_oen_core[5]
  PIN la_oen_core[60]
    DIRECTION OUTPUT TRISTATE ;
    PORT
      LAYER met2 ;
        RECT 566.810 61.000 567.090 65.000 ;
    END
  END la_oen_core[60]
  PIN la_oen_core[61]
    DIRECTION OUTPUT TRISTATE ;
    PORT
      LAYER met2 ;
        RECT 503.330 0.000 503.610 4.000 ;
    END
  END la_oen_core[61]
  PIN la_oen_core[62]
    DIRECTION OUTPUT TRISTATE ;
    PORT
      LAYER met2 ;
        RECT 568.650 61.000 568.930 65.000 ;
    END
  END la_oen_core[62]
  PIN la_oen_core[63]
    DIRECTION OUTPUT TRISTATE ;
    PORT
      LAYER met2 ;
        RECT 505.170 0.000 505.450 4.000 ;
    END
  END la_oen_core[63]
  PIN la_oen_core[64]
    DIRECTION OUTPUT TRISTATE ;
    PORT
      LAYER met2 ;
        RECT 570.490 61.000 570.770 65.000 ;
    END
  END la_oen_core[64]
  PIN la_oen_core[65]
    DIRECTION OUTPUT TRISTATE ;
    PORT
      LAYER met2 ;
        RECT 507.010 0.000 507.290 4.000 ;
    END
  END la_oen_core[65]
  PIN la_oen_core[66]
    DIRECTION OUTPUT TRISTATE ;
    PORT
      LAYER met2 ;
        RECT 572.330 61.000 572.610 65.000 ;
    END
  END la_oen_core[66]
  PIN la_oen_core[67]
    DIRECTION OUTPUT TRISTATE ;
    PORT
      LAYER met2 ;
        RECT 508.850 0.000 509.130 4.000 ;
    END
  END la_oen_core[67]
  PIN la_oen_core[68]
    DIRECTION OUTPUT TRISTATE ;
    PORT
      LAYER met2 ;
        RECT 574.170 61.000 574.450 65.000 ;
    END
  END la_oen_core[68]
  PIN la_oen_core[69]
    DIRECTION OUTPUT TRISTATE ;
    PORT
      LAYER met2 ;
        RECT 510.690 0.000 510.970 4.000 ;
    END
  END la_oen_core[69]
  PIN la_oen_core[6]
    DIRECTION OUTPUT TRISTATE ;
    PORT
      LAYER met2 ;
        RECT 576.010 61.000 576.290 65.000 ;
    END
  END la_oen_core[6]
  PIN la_oen_core[70]
    DIRECTION OUTPUT TRISTATE ;
    PORT
      LAYER met2 ;
        RECT 512.530 0.000 512.810 4.000 ;
    END
  END la_oen_core[70]
  PIN la_oen_core[71]
    DIRECTION OUTPUT TRISTATE ;
    PORT
      LAYER met2 ;
        RECT 577.850 61.000 578.130 65.000 ;
    END
  END la_oen_core[71]
  PIN la_oen_core[72]
    DIRECTION OUTPUT TRISTATE ;
    PORT
      LAYER met2 ;
        RECT 514.370 0.000 514.650 4.000 ;
    END
  END la_oen_core[72]
  PIN la_oen_core[73]
    DIRECTION OUTPUT TRISTATE ;
    PORT
      LAYER met2 ;
        RECT 579.690 61.000 579.970 65.000 ;
    END
  END la_oen_core[73]
  PIN la_oen_core[74]
    DIRECTION OUTPUT TRISTATE ;
    PORT
      LAYER met2 ;
        RECT 516.210 0.000 516.490 4.000 ;
    END
  END la_oen_core[74]
  PIN la_oen_core[75]
    DIRECTION OUTPUT TRISTATE ;
    PORT
      LAYER met2 ;
        RECT 581.530 61.000 581.810 65.000 ;
    END
  END la_oen_core[75]
  PIN la_oen_core[76]
    DIRECTION OUTPUT TRISTATE ;
    PORT
      LAYER met2 ;
        RECT 518.050 0.000 518.330 4.000 ;
    END
  END la_oen_core[76]
  PIN la_oen_core[77]
    DIRECTION OUTPUT TRISTATE ;
    PORT
      LAYER met2 ;
        RECT 583.370 61.000 583.650 65.000 ;
    END
  END la_oen_core[77]
  PIN la_oen_core[78]
    DIRECTION OUTPUT TRISTATE ;
    PORT
      LAYER met2 ;
        RECT 519.890 0.000 520.170 4.000 ;
    END
  END la_oen_core[78]
  PIN la_oen_core[79]
    DIRECTION OUTPUT TRISTATE ;
    PORT
      LAYER met2 ;
        RECT 585.210 61.000 585.490 65.000 ;
    END
  END la_oen_core[79]
  PIN la_oen_core[7]
    DIRECTION OUTPUT TRISTATE ;
    PORT
      LAYER met2 ;
        RECT 521.730 0.000 522.010 4.000 ;
    END
  END la_oen_core[7]
  PIN la_oen_core[80]
    DIRECTION OUTPUT TRISTATE ;
    PORT
      LAYER met2 ;
        RECT 587.050 61.000 587.330 65.000 ;
    END
  END la_oen_core[80]
  PIN la_oen_core[81]
    DIRECTION OUTPUT TRISTATE ;
    PORT
      LAYER met2 ;
        RECT 523.570 0.000 523.850 4.000 ;
    END
  END la_oen_core[81]
  PIN la_oen_core[82]
    DIRECTION OUTPUT TRISTATE ;
    PORT
      LAYER met2 ;
        RECT 588.890 61.000 589.170 65.000 ;
    END
  END la_oen_core[82]
  PIN la_oen_core[83]
    DIRECTION OUTPUT TRISTATE ;
    PORT
      LAYER met2 ;
        RECT 525.410 0.000 525.690 4.000 ;
    END
  END la_oen_core[83]
  PIN la_oen_core[84]
    DIRECTION OUTPUT TRISTATE ;
    PORT
      LAYER met2 ;
        RECT 590.730 61.000 591.010 65.000 ;
    END
  END la_oen_core[84]
  PIN la_oen_core[85]
    DIRECTION OUTPUT TRISTATE ;
    PORT
      LAYER met2 ;
        RECT 527.250 0.000 527.530 4.000 ;
    END
  END la_oen_core[85]
  PIN la_oen_core[86]
    DIRECTION OUTPUT TRISTATE ;
    PORT
      LAYER met2 ;
        RECT 592.570 61.000 592.850 65.000 ;
    END
  END la_oen_core[86]
  PIN la_oen_core[87]
    DIRECTION OUTPUT TRISTATE ;
    PORT
      LAYER met2 ;
        RECT 529.090 0.000 529.370 4.000 ;
    END
  END la_oen_core[87]
  PIN la_oen_core[88]
    DIRECTION OUTPUT TRISTATE ;
    PORT
      LAYER met2 ;
        RECT 594.410 61.000 594.690 65.000 ;
    END
  END la_oen_core[88]
  PIN la_oen_core[89]
    DIRECTION OUTPUT TRISTATE ;
    PORT
      LAYER met2 ;
        RECT 530.930 0.000 531.210 4.000 ;
    END
  END la_oen_core[89]
  PIN la_oen_core[8]
    DIRECTION OUTPUT TRISTATE ;
    PORT
      LAYER met2 ;
        RECT 596.250 61.000 596.530 65.000 ;
    END
  END la_oen_core[8]
  PIN la_oen_core[90]
    DIRECTION OUTPUT TRISTATE ;
    PORT
      LAYER met2 ;
        RECT 532.770 0.000 533.050 4.000 ;
    END
  END la_oen_core[90]
  PIN la_oen_core[91]
    DIRECTION OUTPUT TRISTATE ;
    PORT
      LAYER met2 ;
        RECT 598.090 61.000 598.370 65.000 ;
    END
  END la_oen_core[91]
  PIN la_oen_core[92]
    DIRECTION OUTPUT TRISTATE ;
    PORT
      LAYER met2 ;
        RECT 534.610 0.000 534.890 4.000 ;
    END
  END la_oen_core[92]
  PIN la_oen_core[93]
    DIRECTION OUTPUT TRISTATE ;
    PORT
      LAYER met2 ;
        RECT 599.930 61.000 600.210 65.000 ;
    END
  END la_oen_core[93]
  PIN la_oen_core[94]
    DIRECTION OUTPUT TRISTATE ;
    PORT
      LAYER met2 ;
        RECT 536.450 0.000 536.730 4.000 ;
    END
  END la_oen_core[94]
  PIN la_oen_core[95]
    DIRECTION OUTPUT TRISTATE ;
    PORT
      LAYER met2 ;
        RECT 601.770 61.000 602.050 65.000 ;
    END
  END la_oen_core[95]
  PIN la_oen_core[96]
    DIRECTION OUTPUT TRISTATE ;
    PORT
      LAYER met2 ;
        RECT 538.290 0.000 538.570 4.000 ;
    END
  END la_oen_core[96]
  PIN la_oen_core[97]
    DIRECTION OUTPUT TRISTATE ;
    PORT
      LAYER met2 ;
        RECT 603.610 61.000 603.890 65.000 ;
    END
  END la_oen_core[97]
  PIN la_oen_core[98]
    DIRECTION OUTPUT TRISTATE ;
    PORT
      LAYER met2 ;
        RECT 540.130 0.000 540.410 4.000 ;
    END
  END la_oen_core[98]
  PIN la_oen_core[99]
    DIRECTION OUTPUT TRISTATE ;
    PORT
      LAYER met2 ;
        RECT 605.450 61.000 605.730 65.000 ;
    END
  END la_oen_core[99]
  PIN la_oen_core[9]
    DIRECTION OUTPUT TRISTATE ;
    PORT
      LAYER met2 ;
        RECT 541.970 0.000 542.250 4.000 ;
    END
  END la_oen_core[9]
  PIN la_oen_mprj[0]
    DIRECTION INPUT ;
    PORT
      LAYER met2 ;
        RECT 543.810 0.000 544.090 4.000 ;
    END
  END la_oen_mprj[0]
  PIN la_oen_mprj[100]
    DIRECTION INPUT ;
    PORT
      LAYER met2 ;
        RECT 545.650 0.000 545.930 4.000 ;
    END
  END la_oen_mprj[100]
  PIN la_oen_mprj[101]
    DIRECTION INPUT ;
    PORT
      LAYER met2 ;
        RECT 547.490 0.000 547.770 4.000 ;
    END
  END la_oen_mprj[101]
  PIN la_oen_mprj[102]
    DIRECTION INPUT ;
    PORT
      LAYER met2 ;
        RECT 549.330 0.000 549.610 4.000 ;
    END
  END la_oen_mprj[102]
  PIN la_oen_mprj[103]
    DIRECTION INPUT ;
    PORT
      LAYER met2 ;
        RECT 551.170 0.000 551.450 4.000 ;
    END
  END la_oen_mprj[103]
  PIN la_oen_mprj[104]
    DIRECTION INPUT ;
    PORT
      LAYER met2 ;
        RECT 553.010 0.000 553.290 4.000 ;
    END
  END la_oen_mprj[104]
  PIN la_oen_mprj[105]
    DIRECTION INPUT ;
    PORT
      LAYER met2 ;
        RECT 554.850 0.000 555.130 4.000 ;
    END
  END la_oen_mprj[105]
  PIN la_oen_mprj[106]
    DIRECTION INPUT ;
    PORT
      LAYER met2 ;
        RECT 556.690 0.000 556.970 4.000 ;
    END
  END la_oen_mprj[106]
  PIN la_oen_mprj[107]
    DIRECTION INPUT ;
    PORT
      LAYER met2 ;
        RECT 558.530 0.000 558.810 4.000 ;
    END
  END la_oen_mprj[107]
  PIN la_oen_mprj[108]
    DIRECTION INPUT ;
    PORT
      LAYER met2 ;
        RECT 560.370 0.000 560.650 4.000 ;
    END
  END la_oen_mprj[108]
  PIN la_oen_mprj[109]
    DIRECTION INPUT ;
    PORT
      LAYER met2 ;
        RECT 562.210 0.000 562.490 4.000 ;
    END
  END la_oen_mprj[109]
  PIN la_oen_mprj[10]
    DIRECTION INPUT ;
    PORT
      LAYER met2 ;
        RECT 564.050 0.000 564.330 4.000 ;
    END
  END la_oen_mprj[10]
  PIN la_oen_mprj[110]
    DIRECTION INPUT ;
    PORT
      LAYER met2 ;
        RECT 565.890 0.000 566.170 4.000 ;
    END
  END la_oen_mprj[110]
  PIN la_oen_mprj[111]
    DIRECTION INPUT ;
    PORT
      LAYER met2 ;
        RECT 567.730 0.000 568.010 4.000 ;
    END
  END la_oen_mprj[111]
  PIN la_oen_mprj[112]
    DIRECTION INPUT ;
    PORT
      LAYER met2 ;
        RECT 569.570 0.000 569.850 4.000 ;
    END
  END la_oen_mprj[112]
  PIN la_oen_mprj[113]
    DIRECTION INPUT ;
    PORT
      LAYER met2 ;
        RECT 571.410 0.000 571.690 4.000 ;
    END
  END la_oen_mprj[113]
  PIN la_oen_mprj[114]
    DIRECTION INPUT ;
    PORT
      LAYER met2 ;
        RECT 573.250 0.000 573.530 4.000 ;
    END
  END la_oen_mprj[114]
  PIN la_oen_mprj[115]
    DIRECTION INPUT ;
    PORT
      LAYER met2 ;
        RECT 575.090 0.000 575.370 4.000 ;
    END
  END la_oen_mprj[115]
  PIN la_oen_mprj[116]
    DIRECTION INPUT ;
    PORT
      LAYER met2 ;
        RECT 576.930 0.000 577.210 4.000 ;
    END
  END la_oen_mprj[116]
  PIN la_oen_mprj[117]
    DIRECTION INPUT ;
    PORT
      LAYER met2 ;
        RECT 578.770 0.000 579.050 4.000 ;
    END
  END la_oen_mprj[117]
  PIN la_oen_mprj[118]
    DIRECTION INPUT ;
    PORT
      LAYER met2 ;
        RECT 580.610 0.000 580.890 4.000 ;
    END
  END la_oen_mprj[118]
  PIN la_oen_mprj[119]
    DIRECTION INPUT ;
    PORT
      LAYER met2 ;
        RECT 582.450 0.000 582.730 4.000 ;
    END
  END la_oen_mprj[119]
  PIN la_oen_mprj[11]
    DIRECTION INPUT ;
    PORT
      LAYER met2 ;
        RECT 584.290 0.000 584.570 4.000 ;
    END
  END la_oen_mprj[11]
  PIN la_oen_mprj[120]
    DIRECTION INPUT ;
    PORT
      LAYER met2 ;
        RECT 586.130 0.000 586.410 4.000 ;
    END
  END la_oen_mprj[120]
  PIN la_oen_mprj[121]
    DIRECTION INPUT ;
    PORT
      LAYER met2 ;
        RECT 587.970 0.000 588.250 4.000 ;
    END
  END la_oen_mprj[121]
  PIN la_oen_mprj[122]
    DIRECTION INPUT ;
    PORT
      LAYER met2 ;
        RECT 589.810 0.000 590.090 4.000 ;
    END
  END la_oen_mprj[122]
  PIN la_oen_mprj[123]
    DIRECTION INPUT ;
    PORT
      LAYER met2 ;
        RECT 591.650 0.000 591.930 4.000 ;
    END
  END la_oen_mprj[123]
  PIN la_oen_mprj[124]
    DIRECTION INPUT ;
    PORT
      LAYER met2 ;
        RECT 593.490 0.000 593.770 4.000 ;
    END
  END la_oen_mprj[124]
  PIN la_oen_mprj[125]
    DIRECTION INPUT ;
    PORT
      LAYER met2 ;
        RECT 595.330 0.000 595.610 4.000 ;
    END
  END la_oen_mprj[125]
  PIN la_oen_mprj[126]
    DIRECTION INPUT ;
    PORT
      LAYER met2 ;
        RECT 597.170 0.000 597.450 4.000 ;
    END
  END la_oen_mprj[126]
  PIN la_oen_mprj[127]
    DIRECTION INPUT ;
    PORT
      LAYER met2 ;
        RECT 599.010 0.000 599.290 4.000 ;
    END
  END la_oen_mprj[127]
  PIN la_oen_mprj[12]
    DIRECTION INPUT ;
    PORT
      LAYER met2 ;
        RECT 600.850 0.000 601.130 4.000 ;
    END
  END la_oen_mprj[12]
  PIN la_oen_mprj[13]
    DIRECTION INPUT ;
    PORT
      LAYER met2 ;
        RECT 602.690 0.000 602.970 4.000 ;
    END
  END la_oen_mprj[13]
  PIN la_oen_mprj[14]
    DIRECTION INPUT ;
    PORT
      LAYER met2 ;
        RECT 604.530 0.000 604.810 4.000 ;
    END
  END la_oen_mprj[14]
  PIN la_oen_mprj[15]
    DIRECTION INPUT ;
    PORT
      LAYER met2 ;
        RECT 606.370 0.000 606.650 4.000 ;
    END
  END la_oen_mprj[15]
  PIN la_oen_mprj[16]
    DIRECTION INPUT ;
    PORT
      LAYER met2 ;
        RECT 608.210 0.000 608.490 4.000 ;
    END
  END la_oen_mprj[16]
  PIN la_oen_mprj[17]
    DIRECTION INPUT ;
    PORT
      LAYER met2 ;
        RECT 610.050 0.000 610.330 4.000 ;
    END
  END la_oen_mprj[17]
  PIN la_oen_mprj[18]
    DIRECTION INPUT ;
    PORT
      LAYER met2 ;
        RECT 611.890 0.000 612.170 4.000 ;
    END
  END la_oen_mprj[18]
  PIN la_oen_mprj[19]
    DIRECTION INPUT ;
    PORT
      LAYER met2 ;
        RECT 613.730 0.000 614.010 4.000 ;
    END
  END la_oen_mprj[19]
  PIN la_oen_mprj[1]
    DIRECTION INPUT ;
    PORT
      LAYER met2 ;
        RECT 615.570 0.000 615.850 4.000 ;
    END
  END la_oen_mprj[1]
  PIN la_oen_mprj[20]
    DIRECTION INPUT ;
    PORT
      LAYER met2 ;
        RECT 617.410 0.000 617.690 4.000 ;
    END
  END la_oen_mprj[20]
  PIN la_oen_mprj[21]
    DIRECTION INPUT ;
    PORT
      LAYER met2 ;
        RECT 619.250 0.000 619.530 4.000 ;
    END
  END la_oen_mprj[21]
  PIN la_oen_mprj[22]
    DIRECTION INPUT ;
    PORT
      LAYER met2 ;
        RECT 621.090 0.000 621.370 4.000 ;
    END
  END la_oen_mprj[22]
  PIN la_oen_mprj[23]
    DIRECTION INPUT ;
    PORT
      LAYER met2 ;
        RECT 622.930 0.000 623.210 4.000 ;
    END
  END la_oen_mprj[23]
  PIN la_oen_mprj[24]
    DIRECTION INPUT ;
    PORT
      LAYER met2 ;
        RECT 624.770 0.000 625.050 4.000 ;
    END
  END la_oen_mprj[24]
  PIN la_oen_mprj[25]
    DIRECTION INPUT ;
    PORT
      LAYER met2 ;
        RECT 626.610 0.000 626.890 4.000 ;
    END
  END la_oen_mprj[25]
  PIN la_oen_mprj[26]
    DIRECTION INPUT ;
    PORT
      LAYER met2 ;
        RECT 628.450 0.000 628.730 4.000 ;
    END
  END la_oen_mprj[26]
  PIN la_oen_mprj[27]
    DIRECTION INPUT ;
    PORT
      LAYER met2 ;
        RECT 630.290 0.000 630.570 4.000 ;
    END
  END la_oen_mprj[27]
  PIN la_oen_mprj[28]
    DIRECTION INPUT ;
    PORT
      LAYER met2 ;
        RECT 632.130 0.000 632.410 4.000 ;
    END
  END la_oen_mprj[28]
  PIN la_oen_mprj[29]
    DIRECTION INPUT ;
    PORT
      LAYER met2 ;
        RECT 633.970 0.000 634.250 4.000 ;
    END
  END la_oen_mprj[29]
  PIN la_oen_mprj[2]
    DIRECTION INPUT ;
    PORT
      LAYER met2 ;
        RECT 635.810 0.000 636.090 4.000 ;
    END
  END la_oen_mprj[2]
  PIN la_oen_mprj[30]
    DIRECTION INPUT ;
    PORT
      LAYER met2 ;
        RECT 637.650 0.000 637.930 4.000 ;
    END
  END la_oen_mprj[30]
  PIN la_oen_mprj[31]
    DIRECTION INPUT ;
    PORT
      LAYER met2 ;
        RECT 639.490 0.000 639.770 4.000 ;
    END
  END la_oen_mprj[31]
  PIN la_oen_mprj[32]
    DIRECTION INPUT ;
    PORT
      LAYER met2 ;
        RECT 641.330 0.000 641.610 4.000 ;
    END
  END la_oen_mprj[32]
  PIN la_oen_mprj[33]
    DIRECTION INPUT ;
    PORT
      LAYER met2 ;
        RECT 643.170 0.000 643.450 4.000 ;
    END
  END la_oen_mprj[33]
  PIN la_oen_mprj[34]
    DIRECTION INPUT ;
    PORT
      LAYER met2 ;
        RECT 645.010 0.000 645.290 4.000 ;
    END
  END la_oen_mprj[34]
  PIN la_oen_mprj[35]
    DIRECTION INPUT ;
    PORT
      LAYER met2 ;
        RECT 646.850 0.000 647.130 4.000 ;
    END
  END la_oen_mprj[35]
  PIN la_oen_mprj[36]
    DIRECTION INPUT ;
    PORT
      LAYER met2 ;
        RECT 648.690 0.000 648.970 4.000 ;
    END
  END la_oen_mprj[36]
  PIN la_oen_mprj[37]
    DIRECTION INPUT ;
    PORT
      LAYER met2 ;
        RECT 650.530 0.000 650.810 4.000 ;
    END
  END la_oen_mprj[37]
  PIN la_oen_mprj[38]
    DIRECTION INPUT ;
    PORT
      LAYER met2 ;
        RECT 652.370 0.000 652.650 4.000 ;
    END
  END la_oen_mprj[38]
  PIN la_oen_mprj[39]
    DIRECTION INPUT ;
    PORT
      LAYER met2 ;
        RECT 654.210 0.000 654.490 4.000 ;
    END
  END la_oen_mprj[39]
  PIN la_oen_mprj[3]
    DIRECTION INPUT ;
    PORT
      LAYER met2 ;
        RECT 656.050 0.000 656.330 4.000 ;
    END
  END la_oen_mprj[3]
  PIN la_oen_mprj[40]
    DIRECTION INPUT ;
    PORT
      LAYER met2 ;
        RECT 657.890 0.000 658.170 4.000 ;
    END
  END la_oen_mprj[40]
  PIN la_oen_mprj[41]
    DIRECTION INPUT ;
    PORT
      LAYER met2 ;
        RECT 659.730 0.000 660.010 4.000 ;
    END
  END la_oen_mprj[41]
  PIN la_oen_mprj[42]
    DIRECTION INPUT ;
    PORT
      LAYER met2 ;
        RECT 661.570 0.000 661.850 4.000 ;
    END
  END la_oen_mprj[42]
  PIN la_oen_mprj[43]
    DIRECTION INPUT ;
    PORT
      LAYER met2 ;
        RECT 663.410 0.000 663.690 4.000 ;
    END
  END la_oen_mprj[43]
  PIN la_oen_mprj[44]
    DIRECTION INPUT ;
    PORT
      LAYER met2 ;
        RECT 665.250 0.000 665.530 4.000 ;
    END
  END la_oen_mprj[44]
  PIN la_oen_mprj[45]
    DIRECTION INPUT ;
    PORT
      LAYER met2 ;
        RECT 667.090 0.000 667.370 4.000 ;
    END
  END la_oen_mprj[45]
  PIN la_oen_mprj[46]
    DIRECTION INPUT ;
    PORT
      LAYER met2 ;
        RECT 668.930 0.000 669.210 4.000 ;
    END
  END la_oen_mprj[46]
  PIN la_oen_mprj[47]
    DIRECTION INPUT ;
    PORT
      LAYER met2 ;
        RECT 670.770 0.000 671.050 4.000 ;
    END
  END la_oen_mprj[47]
  PIN la_oen_mprj[48]
    DIRECTION INPUT ;
    PORT
      LAYER met2 ;
        RECT 607.290 61.000 607.570 65.000 ;
    END
  END la_oen_mprj[48]
  PIN la_oen_mprj[49]
    DIRECTION INPUT ;
    PORT
      LAYER met2 ;
        RECT 672.610 0.000 672.890 4.000 ;
    END
  END la_oen_mprj[49]
  PIN la_oen_mprj[4]
    DIRECTION INPUT ;
    PORT
      LAYER met2 ;
        RECT 609.130 61.000 609.410 65.000 ;
    END
  END la_oen_mprj[4]
  PIN la_oen_mprj[50]
    DIRECTION INPUT ;
    PORT
      LAYER met2 ;
        RECT 674.450 0.000 674.730 4.000 ;
    END
  END la_oen_mprj[50]
  PIN la_oen_mprj[51]
    DIRECTION INPUT ;
    PORT
      LAYER met2 ;
        RECT 610.970 61.000 611.250 65.000 ;
    END
  END la_oen_mprj[51]
  PIN la_oen_mprj[52]
    DIRECTION INPUT ;
    PORT
      LAYER met2 ;
        RECT 676.290 0.000 676.570 4.000 ;
    END
  END la_oen_mprj[52]
  PIN la_oen_mprj[53]
    DIRECTION INPUT ;
    PORT
      LAYER met2 ;
        RECT 612.810 61.000 613.090 65.000 ;
    END
  END la_oen_mprj[53]
  PIN la_oen_mprj[54]
    DIRECTION INPUT ;
    PORT
      LAYER met2 ;
        RECT 678.130 0.000 678.410 4.000 ;
    END
  END la_oen_mprj[54]
  PIN la_oen_mprj[55]
    DIRECTION INPUT ;
    PORT
      LAYER met2 ;
        RECT 614.650 61.000 614.930 65.000 ;
    END
  END la_oen_mprj[55]
  PIN la_oen_mprj[56]
    DIRECTION INPUT ;
    PORT
      LAYER met2 ;
        RECT 679.970 0.000 680.250 4.000 ;
    END
  END la_oen_mprj[56]
  PIN la_oen_mprj[57]
    DIRECTION INPUT ;
    PORT
      LAYER met2 ;
        RECT 616.490 61.000 616.770 65.000 ;
    END
  END la_oen_mprj[57]
  PIN la_oen_mprj[58]
    DIRECTION INPUT ;
    PORT
      LAYER met2 ;
        RECT 681.810 0.000 682.090 4.000 ;
    END
  END la_oen_mprj[58]
  PIN la_oen_mprj[59]
    DIRECTION INPUT ;
    PORT
      LAYER met2 ;
        RECT 618.330 61.000 618.610 65.000 ;
    END
  END la_oen_mprj[59]
  PIN la_oen_mprj[5]
    DIRECTION INPUT ;
    PORT
      LAYER met2 ;
        RECT 683.650 0.000 683.930 4.000 ;
    END
  END la_oen_mprj[5]
  PIN la_oen_mprj[60]
    DIRECTION INPUT ;
    PORT
      LAYER met2 ;
        RECT 620.170 61.000 620.450 65.000 ;
    END
  END la_oen_mprj[60]
  PIN la_oen_mprj[61]
    DIRECTION INPUT ;
    PORT
      LAYER met2 ;
        RECT 685.490 0.000 685.770 4.000 ;
    END
  END la_oen_mprj[61]
  PIN la_oen_mprj[62]
    DIRECTION INPUT ;
    PORT
      LAYER met2 ;
        RECT 622.010 61.000 622.290 65.000 ;
    END
  END la_oen_mprj[62]
  PIN la_oen_mprj[63]
    DIRECTION INPUT ;
    PORT
      LAYER met2 ;
        RECT 687.330 0.000 687.610 4.000 ;
    END
  END la_oen_mprj[63]
  PIN la_oen_mprj[64]
    DIRECTION INPUT ;
    PORT
      LAYER met2 ;
        RECT 623.850 61.000 624.130 65.000 ;
    END
  END la_oen_mprj[64]
  PIN la_oen_mprj[65]
    DIRECTION INPUT ;
    PORT
      LAYER met2 ;
        RECT 689.170 0.000 689.450 4.000 ;
    END
  END la_oen_mprj[65]
  PIN la_oen_mprj[66]
    DIRECTION INPUT ;
    PORT
      LAYER met2 ;
        RECT 625.690 61.000 625.970 65.000 ;
    END
  END la_oen_mprj[66]
  PIN la_oen_mprj[67]
    DIRECTION INPUT ;
    PORT
      LAYER met2 ;
        RECT 691.010 0.000 691.290 4.000 ;
    END
  END la_oen_mprj[67]
  PIN la_oen_mprj[68]
    DIRECTION INPUT ;
    PORT
      LAYER met2 ;
        RECT 627.530 61.000 627.810 65.000 ;
    END
  END la_oen_mprj[68]
  PIN la_oen_mprj[69]
    DIRECTION INPUT ;
    PORT
      LAYER met2 ;
        RECT 692.850 0.000 693.130 4.000 ;
    END
  END la_oen_mprj[69]
  PIN la_oen_mprj[6]
    DIRECTION INPUT ;
    PORT
      LAYER met2 ;
        RECT 629.370 61.000 629.650 65.000 ;
    END
  END la_oen_mprj[6]
  PIN la_oen_mprj[70]
    DIRECTION INPUT ;
    PORT
      LAYER met2 ;
        RECT 694.690 0.000 694.970 4.000 ;
    END
  END la_oen_mprj[70]
  PIN la_oen_mprj[71]
    DIRECTION INPUT ;
    PORT
      LAYER met2 ;
        RECT 631.210 61.000 631.490 65.000 ;
    END
  END la_oen_mprj[71]
  PIN la_oen_mprj[72]
    DIRECTION INPUT ;
    PORT
      LAYER met2 ;
        RECT 696.530 0.000 696.810 4.000 ;
    END
  END la_oen_mprj[72]
  PIN la_oen_mprj[73]
    DIRECTION INPUT ;
    PORT
      LAYER met2 ;
        RECT 633.050 61.000 633.330 65.000 ;
    END
  END la_oen_mprj[73]
  PIN la_oen_mprj[74]
    DIRECTION INPUT ;
    PORT
      LAYER met2 ;
        RECT 698.370 0.000 698.650 4.000 ;
    END
  END la_oen_mprj[74]
  PIN la_oen_mprj[75]
    DIRECTION INPUT ;
    PORT
      LAYER met2 ;
        RECT 634.890 61.000 635.170 65.000 ;
    END
  END la_oen_mprj[75]
  PIN la_oen_mprj[76]
    DIRECTION INPUT ;
    PORT
      LAYER met2 ;
        RECT 700.210 0.000 700.490 4.000 ;
    END
  END la_oen_mprj[76]
  PIN la_oen_mprj[77]
    DIRECTION INPUT ;
    PORT
      LAYER met2 ;
        RECT 636.730 61.000 637.010 65.000 ;
    END
  END la_oen_mprj[77]
  PIN la_oen_mprj[78]
    DIRECTION INPUT ;
    PORT
      LAYER met2 ;
        RECT 702.050 0.000 702.330 4.000 ;
    END
  END la_oen_mprj[78]
  PIN la_oen_mprj[79]
    DIRECTION INPUT ;
    PORT
      LAYER met2 ;
        RECT 638.570 61.000 638.850 65.000 ;
    END
  END la_oen_mprj[79]
  PIN la_oen_mprj[7]
    DIRECTION INPUT ;
    PORT
      LAYER met2 ;
        RECT 703.890 0.000 704.170 4.000 ;
    END
  END la_oen_mprj[7]
  PIN la_oen_mprj[80]
    DIRECTION INPUT ;
    PORT
      LAYER met2 ;
        RECT 640.410 61.000 640.690 65.000 ;
    END
  END la_oen_mprj[80]
  PIN la_oen_mprj[81]
    DIRECTION INPUT ;
    PORT
      LAYER met2 ;
        RECT 705.730 0.000 706.010 4.000 ;
    END
  END la_oen_mprj[81]
  PIN la_oen_mprj[82]
    DIRECTION INPUT ;
    PORT
      LAYER met2 ;
        RECT 642.250 61.000 642.530 65.000 ;
    END
  END la_oen_mprj[82]
  PIN la_oen_mprj[83]
    DIRECTION INPUT ;
    PORT
      LAYER met2 ;
        RECT 707.570 0.000 707.850 4.000 ;
    END
  END la_oen_mprj[83]
  PIN la_oen_mprj[84]
    DIRECTION INPUT ;
    PORT
      LAYER met2 ;
        RECT 644.090 61.000 644.370 65.000 ;
    END
  END la_oen_mprj[84]
  PIN la_oen_mprj[85]
    DIRECTION INPUT ;
    PORT
      LAYER met2 ;
        RECT 709.410 0.000 709.690 4.000 ;
    END
  END la_oen_mprj[85]
  PIN la_oen_mprj[86]
    DIRECTION INPUT ;
    PORT
      LAYER met2 ;
        RECT 645.930 61.000 646.210 65.000 ;
    END
  END la_oen_mprj[86]
  PIN la_oen_mprj[87]
    DIRECTION INPUT ;
    PORT
      LAYER met2 ;
        RECT 711.250 0.000 711.530 4.000 ;
    END
  END la_oen_mprj[87]
  PIN la_oen_mprj[88]
    DIRECTION INPUT ;
    PORT
      LAYER met2 ;
        RECT 647.770 61.000 648.050 65.000 ;
    END
  END la_oen_mprj[88]
  PIN la_oen_mprj[89]
    DIRECTION INPUT ;
    PORT
      LAYER met2 ;
        RECT 713.090 0.000 713.370 4.000 ;
    END
  END la_oen_mprj[89]
  PIN la_oen_mprj[8]
    DIRECTION INPUT ;
    PORT
      LAYER met2 ;
        RECT 649.610 61.000 649.890 65.000 ;
    END
  END la_oen_mprj[8]
  PIN la_oen_mprj[90]
    DIRECTION INPUT ;
    PORT
      LAYER met2 ;
        RECT 714.930 0.000 715.210 4.000 ;
    END
  END la_oen_mprj[90]
  PIN la_oen_mprj[91]
    DIRECTION INPUT ;
    PORT
      LAYER met2 ;
        RECT 651.450 61.000 651.730 65.000 ;
    END
  END la_oen_mprj[91]
  PIN la_oen_mprj[92]
    DIRECTION INPUT ;
    PORT
      LAYER met2 ;
        RECT 716.770 0.000 717.050 4.000 ;
    END
  END la_oen_mprj[92]
  PIN la_oen_mprj[93]
    DIRECTION INPUT ;
    PORT
      LAYER met2 ;
        RECT 653.290 61.000 653.570 65.000 ;
    END
  END la_oen_mprj[93]
  PIN la_oen_mprj[94]
    DIRECTION INPUT ;
    PORT
      LAYER met2 ;
        RECT 718.610 0.000 718.890 4.000 ;
    END
  END la_oen_mprj[94]
  PIN la_oen_mprj[95]
    DIRECTION INPUT ;
    PORT
      LAYER met2 ;
        RECT 655.130 61.000 655.410 65.000 ;
    END
  END la_oen_mprj[95]
  PIN la_oen_mprj[96]
    DIRECTION INPUT ;
    PORT
      LAYER met2 ;
        RECT 720.450 0.000 720.730 4.000 ;
    END
  END la_oen_mprj[96]
  PIN la_oen_mprj[97]
    DIRECTION INPUT ;
    PORT
      LAYER met2 ;
        RECT 656.970 61.000 657.250 65.000 ;
    END
  END la_oen_mprj[97]
  PIN la_oen_mprj[98]
    DIRECTION INPUT ;
    PORT
      LAYER met2 ;
        RECT 722.290 0.000 722.570 4.000 ;
    END
  END la_oen_mprj[98]
  PIN la_oen_mprj[99]
    DIRECTION INPUT ;
    PORT
      LAYER met2 ;
        RECT 658.810 61.000 659.090 65.000 ;
    END
  END la_oen_mprj[99]
  PIN la_oen_mprj[9]
    DIRECTION INPUT ;
    PORT
      LAYER met2 ;
        RECT 724.130 0.000 724.410 4.000 ;
    END
  END la_oen_mprj[9]
  PIN mprj_adr_o_core[0]
    DIRECTION INPUT ;
    PORT
      LAYER met2 ;
        RECT 660.650 61.000 660.930 65.000 ;
    END
  END mprj_adr_o_core[0]
  PIN mprj_adr_o_core[10]
    DIRECTION INPUT ;
    PORT
      LAYER met2 ;
        RECT 725.970 0.000 726.250 4.000 ;
    END
  END mprj_adr_o_core[10]
  PIN mprj_adr_o_core[11]
    DIRECTION INPUT ;
    PORT
      LAYER met2 ;
        RECT 662.490 61.000 662.770 65.000 ;
    END
  END mprj_adr_o_core[11]
  PIN mprj_adr_o_core[12]
    DIRECTION INPUT ;
    PORT
      LAYER met2 ;
        RECT 727.810 0.000 728.090 4.000 ;
    END
  END mprj_adr_o_core[12]
  PIN mprj_adr_o_core[13]
    DIRECTION INPUT ;
    PORT
      LAYER met2 ;
        RECT 664.330 61.000 664.610 65.000 ;
    END
  END mprj_adr_o_core[13]
  PIN mprj_adr_o_core[14]
    DIRECTION INPUT ;
    PORT
      LAYER met2 ;
        RECT 729.650 0.000 729.930 4.000 ;
    END
  END mprj_adr_o_core[14]
  PIN mprj_adr_o_core[15]
    DIRECTION INPUT ;
    PORT
      LAYER met2 ;
        RECT 666.170 61.000 666.450 65.000 ;
    END
  END mprj_adr_o_core[15]
  PIN mprj_adr_o_core[16]
    DIRECTION INPUT ;
    PORT
      LAYER met2 ;
        RECT 731.490 0.000 731.770 4.000 ;
    END
  END mprj_adr_o_core[16]
  PIN mprj_adr_o_core[17]
    DIRECTION INPUT ;
    PORT
      LAYER met2 ;
        RECT 668.010 61.000 668.290 65.000 ;
    END
  END mprj_adr_o_core[17]
  PIN mprj_adr_o_core[18]
    DIRECTION INPUT ;
    PORT
      LAYER met2 ;
        RECT 733.330 0.000 733.610 4.000 ;
    END
  END mprj_adr_o_core[18]
  PIN mprj_adr_o_core[19]
    DIRECTION INPUT ;
    PORT
      LAYER met2 ;
        RECT 669.850 61.000 670.130 65.000 ;
    END
  END mprj_adr_o_core[19]
  PIN mprj_adr_o_core[1]
    DIRECTION INPUT ;
    PORT
      LAYER met2 ;
        RECT 735.170 0.000 735.450 4.000 ;
    END
  END mprj_adr_o_core[1]
  PIN mprj_adr_o_core[20]
    DIRECTION INPUT ;
    PORT
      LAYER met2 ;
        RECT 671.690 61.000 671.970 65.000 ;
    END
  END mprj_adr_o_core[20]
  PIN mprj_adr_o_core[21]
    DIRECTION INPUT ;
    PORT
      LAYER met2 ;
        RECT 737.010 0.000 737.290 4.000 ;
    END
  END mprj_adr_o_core[21]
  PIN mprj_adr_o_core[22]
    DIRECTION INPUT ;
    PORT
      LAYER met2 ;
        RECT 673.530 61.000 673.810 65.000 ;
    END
  END mprj_adr_o_core[22]
  PIN mprj_adr_o_core[23]
    DIRECTION INPUT ;
    PORT
      LAYER met2 ;
        RECT 738.850 0.000 739.130 4.000 ;
    END
  END mprj_adr_o_core[23]
  PIN mprj_adr_o_core[24]
    DIRECTION INPUT ;
    PORT
      LAYER met2 ;
        RECT 675.370 61.000 675.650 65.000 ;
    END
  END mprj_adr_o_core[24]
  PIN mprj_adr_o_core[25]
    DIRECTION INPUT ;
    PORT
      LAYER met2 ;
        RECT 740.690 0.000 740.970 4.000 ;
    END
  END mprj_adr_o_core[25]
  PIN mprj_adr_o_core[26]
    DIRECTION INPUT ;
    PORT
      LAYER met2 ;
        RECT 677.210 61.000 677.490 65.000 ;
    END
  END mprj_adr_o_core[26]
  PIN mprj_adr_o_core[27]
    DIRECTION INPUT ;
    PORT
      LAYER met2 ;
        RECT 742.530 0.000 742.810 4.000 ;
    END
  END mprj_adr_o_core[27]
  PIN mprj_adr_o_core[28]
    DIRECTION INPUT ;
    PORT
      LAYER met2 ;
        RECT 679.050 61.000 679.330 65.000 ;
    END
  END mprj_adr_o_core[28]
  PIN mprj_adr_o_core[29]
    DIRECTION INPUT ;
    PORT
      LAYER met2 ;
        RECT 744.370 0.000 744.650 4.000 ;
    END
  END mprj_adr_o_core[29]
  PIN mprj_adr_o_core[2]
    DIRECTION INPUT ;
    PORT
      LAYER met2 ;
        RECT 680.890 61.000 681.170 65.000 ;
    END
  END mprj_adr_o_core[2]
  PIN mprj_adr_o_core[30]
    DIRECTION INPUT ;
    PORT
      LAYER met2 ;
        RECT 746.210 0.000 746.490 4.000 ;
    END
  END mprj_adr_o_core[30]
  PIN mprj_adr_o_core[31]
    DIRECTION INPUT ;
    PORT
      LAYER met2 ;
        RECT 682.730 61.000 683.010 65.000 ;
    END
  END mprj_adr_o_core[31]
  PIN mprj_adr_o_core[3]
    DIRECTION INPUT ;
    PORT
      LAYER met2 ;
        RECT 748.050 0.000 748.330 4.000 ;
    END
  END mprj_adr_o_core[3]
  PIN mprj_adr_o_core[4]
    DIRECTION INPUT ;
    PORT
      LAYER met2 ;
        RECT 684.570 61.000 684.850 65.000 ;
    END
  END mprj_adr_o_core[4]
  PIN mprj_adr_o_core[5]
    DIRECTION INPUT ;
    PORT
      LAYER met2 ;
        RECT 749.890 0.000 750.170 4.000 ;
    END
  END mprj_adr_o_core[5]
  PIN mprj_adr_o_core[6]
    DIRECTION INPUT ;
    PORT
      LAYER met2 ;
        RECT 686.410 61.000 686.690 65.000 ;
    END
  END mprj_adr_o_core[6]
  PIN mprj_adr_o_core[7]
    DIRECTION INPUT ;
    PORT
      LAYER met2 ;
        RECT 751.730 0.000 752.010 4.000 ;
    END
  END mprj_adr_o_core[7]
  PIN mprj_adr_o_core[8]
    DIRECTION INPUT ;
    PORT
      LAYER met2 ;
        RECT 688.250 61.000 688.530 65.000 ;
    END
  END mprj_adr_o_core[8]
  PIN mprj_adr_o_core[9]
    DIRECTION INPUT ;
    PORT
      LAYER met2 ;
        RECT 753.570 0.000 753.850 4.000 ;
    END
  END mprj_adr_o_core[9]
  PIN mprj_adr_o_user[0]
    DIRECTION OUTPUT TRISTATE ;
    PORT
      LAYER met2 ;
        RECT 690.090 61.000 690.370 65.000 ;
    END
  END mprj_adr_o_user[0]
  PIN mprj_adr_o_user[10]
    DIRECTION OUTPUT TRISTATE ;
    PORT
      LAYER met2 ;
        RECT 691.930 61.000 692.210 65.000 ;
    END
  END mprj_adr_o_user[10]
  PIN mprj_adr_o_user[11]
    DIRECTION OUTPUT TRISTATE ;
    PORT
      LAYER met2 ;
        RECT 693.770 61.000 694.050 65.000 ;
    END
  END mprj_adr_o_user[11]
  PIN mprj_adr_o_user[12]
    DIRECTION OUTPUT TRISTATE ;
    PORT
      LAYER met2 ;
        RECT 695.610 61.000 695.890 65.000 ;
    END
  END mprj_adr_o_user[12]
  PIN mprj_adr_o_user[13]
    DIRECTION OUTPUT TRISTATE ;
    PORT
      LAYER met2 ;
        RECT 697.450 61.000 697.730 65.000 ;
    END
  END mprj_adr_o_user[13]
  PIN mprj_adr_o_user[14]
    DIRECTION OUTPUT TRISTATE ;
    PORT
      LAYER met2 ;
        RECT 699.290 61.000 699.570 65.000 ;
    END
  END mprj_adr_o_user[14]
  PIN mprj_adr_o_user[15]
    DIRECTION OUTPUT TRISTATE ;
    PORT
      LAYER met2 ;
        RECT 701.130 61.000 701.410 65.000 ;
    END
  END mprj_adr_o_user[15]
  PIN mprj_adr_o_user[16]
    DIRECTION OUTPUT TRISTATE ;
    PORT
      LAYER met2 ;
        RECT 702.970 61.000 703.250 65.000 ;
    END
  END mprj_adr_o_user[16]
  PIN mprj_adr_o_user[17]
    DIRECTION OUTPUT TRISTATE ;
    PORT
      LAYER met2 ;
        RECT 704.810 61.000 705.090 65.000 ;
    END
  END mprj_adr_o_user[17]
  PIN mprj_adr_o_user[18]
    DIRECTION OUTPUT TRISTATE ;
    PORT
      LAYER met2 ;
        RECT 706.650 61.000 706.930 65.000 ;
    END
  END mprj_adr_o_user[18]
  PIN mprj_adr_o_user[19]
    DIRECTION OUTPUT TRISTATE ;
    PORT
      LAYER met2 ;
        RECT 708.490 61.000 708.770 65.000 ;
    END
  END mprj_adr_o_user[19]
  PIN mprj_adr_o_user[1]
    DIRECTION OUTPUT TRISTATE ;
    PORT
      LAYER met2 ;
        RECT 710.330 61.000 710.610 65.000 ;
    END
  END mprj_adr_o_user[1]
  PIN mprj_adr_o_user[20]
    DIRECTION OUTPUT TRISTATE ;
    PORT
      LAYER met2 ;
        RECT 712.170 61.000 712.450 65.000 ;
    END
  END mprj_adr_o_user[20]
  PIN mprj_adr_o_user[21]
    DIRECTION OUTPUT TRISTATE ;
    PORT
      LAYER met2 ;
        RECT 714.010 61.000 714.290 65.000 ;
    END
  END mprj_adr_o_user[21]
  PIN mprj_adr_o_user[22]
    DIRECTION OUTPUT TRISTATE ;
    PORT
      LAYER met2 ;
        RECT 715.850 61.000 716.130 65.000 ;
    END
  END mprj_adr_o_user[22]
  PIN mprj_adr_o_user[23]
    DIRECTION OUTPUT TRISTATE ;
    PORT
      LAYER met2 ;
        RECT 717.690 61.000 717.970 65.000 ;
    END
  END mprj_adr_o_user[23]
  PIN mprj_adr_o_user[24]
    DIRECTION OUTPUT TRISTATE ;
    PORT
      LAYER met2 ;
        RECT 719.530 61.000 719.810 65.000 ;
    END
  END mprj_adr_o_user[24]
  PIN mprj_adr_o_user[25]
    DIRECTION OUTPUT TRISTATE ;
    PORT
      LAYER met2 ;
        RECT 721.370 61.000 721.650 65.000 ;
    END
  END mprj_adr_o_user[25]
  PIN mprj_adr_o_user[26]
    DIRECTION OUTPUT TRISTATE ;
    PORT
      LAYER met2 ;
        RECT 723.210 61.000 723.490 65.000 ;
    END
  END mprj_adr_o_user[26]
  PIN mprj_adr_o_user[27]
    DIRECTION OUTPUT TRISTATE ;
    PORT
      LAYER met2 ;
        RECT 725.050 61.000 725.330 65.000 ;
    END
  END mprj_adr_o_user[27]
  PIN mprj_adr_o_user[28]
    DIRECTION OUTPUT TRISTATE ;
    PORT
      LAYER met2 ;
        RECT 726.890 61.000 727.170 65.000 ;
    END
  END mprj_adr_o_user[28]
  PIN mprj_adr_o_user[29]
    DIRECTION OUTPUT TRISTATE ;
    PORT
      LAYER met2 ;
        RECT 728.730 61.000 729.010 65.000 ;
    END
  END mprj_adr_o_user[29]
  PIN mprj_adr_o_user[2]
    DIRECTION OUTPUT TRISTATE ;
    PORT
      LAYER met2 ;
        RECT 730.570 61.000 730.850 65.000 ;
    END
  END mprj_adr_o_user[2]
  PIN mprj_adr_o_user[30]
    DIRECTION OUTPUT TRISTATE ;
    PORT
      LAYER met2 ;
        RECT 732.410 61.000 732.690 65.000 ;
    END
  END mprj_adr_o_user[30]
  PIN mprj_adr_o_user[31]
    DIRECTION OUTPUT TRISTATE ;
    PORT
      LAYER met2 ;
        RECT 734.250 61.000 734.530 65.000 ;
    END
  END mprj_adr_o_user[31]
  PIN mprj_adr_o_user[3]
    DIRECTION OUTPUT TRISTATE ;
    PORT
      LAYER met2 ;
        RECT 736.090 61.000 736.370 65.000 ;
    END
  END mprj_adr_o_user[3]
  PIN mprj_adr_o_user[4]
    DIRECTION OUTPUT TRISTATE ;
    PORT
      LAYER met2 ;
        RECT 737.930 61.000 738.210 65.000 ;
    END
  END mprj_adr_o_user[4]
  PIN mprj_adr_o_user[5]
    DIRECTION OUTPUT TRISTATE ;
    PORT
      LAYER met2 ;
        RECT 739.770 61.000 740.050 65.000 ;
    END
  END mprj_adr_o_user[5]
  PIN mprj_adr_o_user[6]
    DIRECTION OUTPUT TRISTATE ;
    PORT
      LAYER met2 ;
        RECT 741.610 61.000 741.890 65.000 ;
    END
  END mprj_adr_o_user[6]
  PIN mprj_adr_o_user[7]
    DIRECTION OUTPUT TRISTATE ;
    PORT
      LAYER met2 ;
        RECT 743.450 61.000 743.730 65.000 ;
    END
  END mprj_adr_o_user[7]
  PIN mprj_adr_o_user[8]
    DIRECTION OUTPUT TRISTATE ;
    PORT
      LAYER met2 ;
        RECT 745.290 61.000 745.570 65.000 ;
    END
  END mprj_adr_o_user[8]
  PIN mprj_adr_o_user[9]
    DIRECTION OUTPUT TRISTATE ;
    PORT
      LAYER met2 ;
        RECT 747.130 61.000 747.410 65.000 ;
    END
  END mprj_adr_o_user[9]
  PIN mprj_cyc_o_core
    DIRECTION INPUT ;
    PORT
      LAYER met2 ;
        RECT 755.410 0.000 755.690 4.000 ;
    END
  END mprj_cyc_o_core
  PIN mprj_cyc_o_user
    DIRECTION OUTPUT TRISTATE ;
    PORT
      LAYER met2 ;
        RECT 748.970 61.000 749.250 65.000 ;
    END
  END mprj_cyc_o_user
  PIN mprj_dat_o_core[0]
    DIRECTION INPUT ;
    PORT
      LAYER met2 ;
        RECT 757.250 0.000 757.530 4.000 ;
    END
  END mprj_dat_o_core[0]
  PIN mprj_dat_o_core[10]
    DIRECTION INPUT ;
    PORT
      LAYER met2 ;
        RECT 759.090 0.000 759.370 4.000 ;
    END
  END mprj_dat_o_core[10]
  PIN mprj_dat_o_core[11]
    DIRECTION INPUT ;
    PORT
      LAYER met2 ;
        RECT 760.930 0.000 761.210 4.000 ;
    END
  END mprj_dat_o_core[11]
  PIN mprj_dat_o_core[12]
    DIRECTION INPUT ;
    PORT
      LAYER met2 ;
        RECT 762.770 0.000 763.050 4.000 ;
    END
  END mprj_dat_o_core[12]
  PIN mprj_dat_o_core[13]
    DIRECTION INPUT ;
    PORT
      LAYER met2 ;
        RECT 764.610 0.000 764.890 4.000 ;
    END
  END mprj_dat_o_core[13]
  PIN mprj_dat_o_core[14]
    DIRECTION INPUT ;
    PORT
      LAYER met2 ;
        RECT 766.450 0.000 766.730 4.000 ;
    END
  END mprj_dat_o_core[14]
  PIN mprj_dat_o_core[15]
    DIRECTION INPUT ;
    PORT
      LAYER met2 ;
        RECT 768.290 0.000 768.570 4.000 ;
    END
  END mprj_dat_o_core[15]
  PIN mprj_dat_o_core[16]
    DIRECTION INPUT ;
    PORT
      LAYER met2 ;
        RECT 770.130 0.000 770.410 4.000 ;
    END
  END mprj_dat_o_core[16]
  PIN mprj_dat_o_core[17]
    DIRECTION INPUT ;
    PORT
      LAYER met2 ;
        RECT 771.970 0.000 772.250 4.000 ;
    END
  END mprj_dat_o_core[17]
  PIN mprj_dat_o_core[18]
    DIRECTION INPUT ;
    PORT
      LAYER met2 ;
        RECT 773.810 0.000 774.090 4.000 ;
    END
  END mprj_dat_o_core[18]
  PIN mprj_dat_o_core[19]
    DIRECTION INPUT ;
    PORT
      LAYER met2 ;
        RECT 775.650 0.000 775.930 4.000 ;
    END
  END mprj_dat_o_core[19]
  PIN mprj_dat_o_core[1]
    DIRECTION INPUT ;
    PORT
      LAYER met2 ;
        RECT 777.490 0.000 777.770 4.000 ;
    END
  END mprj_dat_o_core[1]
  PIN mprj_dat_o_core[20]
    DIRECTION INPUT ;
    PORT
      LAYER met2 ;
        RECT 779.330 0.000 779.610 4.000 ;
    END
  END mprj_dat_o_core[20]
  PIN mprj_dat_o_core[21]
    DIRECTION INPUT ;
    PORT
      LAYER met2 ;
        RECT 781.170 0.000 781.450 4.000 ;
    END
  END mprj_dat_o_core[21]
  PIN mprj_dat_o_core[22]
    DIRECTION INPUT ;
    PORT
      LAYER met2 ;
        RECT 783.010 0.000 783.290 4.000 ;
    END
  END mprj_dat_o_core[22]
  PIN mprj_dat_o_core[23]
    DIRECTION INPUT ;
    PORT
      LAYER met2 ;
        RECT 784.850 0.000 785.130 4.000 ;
    END
  END mprj_dat_o_core[23]
  PIN mprj_dat_o_core[24]
    DIRECTION INPUT ;
    PORT
      LAYER met2 ;
        RECT 786.690 0.000 786.970 4.000 ;
    END
  END mprj_dat_o_core[24]
  PIN mprj_dat_o_core[25]
    DIRECTION INPUT ;
    PORT
      LAYER met2 ;
        RECT 788.530 0.000 788.810 4.000 ;
    END
  END mprj_dat_o_core[25]
  PIN mprj_dat_o_core[26]
    DIRECTION INPUT ;
    PORT
      LAYER met2 ;
        RECT 790.370 0.000 790.650 4.000 ;
    END
  END mprj_dat_o_core[26]
  PIN mprj_dat_o_core[27]
    DIRECTION INPUT ;
    PORT
      LAYER met2 ;
        RECT 792.210 0.000 792.490 4.000 ;
    END
  END mprj_dat_o_core[27]
  PIN mprj_dat_o_core[28]
    DIRECTION INPUT ;
    PORT
      LAYER met2 ;
        RECT 794.050 0.000 794.330 4.000 ;
    END
  END mprj_dat_o_core[28]
  PIN mprj_dat_o_core[29]
    DIRECTION INPUT ;
    PORT
      LAYER met2 ;
        RECT 795.890 0.000 796.170 4.000 ;
    END
  END mprj_dat_o_core[29]
  PIN mprj_dat_o_core[2]
    DIRECTION INPUT ;
    PORT
      LAYER met2 ;
        RECT 797.730 0.000 798.010 4.000 ;
    END
  END mprj_dat_o_core[2]
  PIN mprj_dat_o_core[30]
    DIRECTION INPUT ;
    PORT
      LAYER met2 ;
        RECT 799.570 0.000 799.850 4.000 ;
    END
  END mprj_dat_o_core[30]
  PIN mprj_dat_o_core[31]
    DIRECTION INPUT ;
    PORT
      LAYER met2 ;
        RECT 801.410 0.000 801.690 4.000 ;
    END
  END mprj_dat_o_core[31]
  PIN mprj_dat_o_core[3]
    DIRECTION INPUT ;
    PORT
      LAYER met2 ;
        RECT 803.250 0.000 803.530 4.000 ;
    END
  END mprj_dat_o_core[3]
  PIN mprj_dat_o_core[4]
    DIRECTION INPUT ;
    PORT
      LAYER met2 ;
        RECT 805.090 0.000 805.370 4.000 ;
    END
  END mprj_dat_o_core[4]
  PIN mprj_dat_o_core[5]
    DIRECTION INPUT ;
    PORT
      LAYER met2 ;
        RECT 806.930 0.000 807.210 4.000 ;
    END
  END mprj_dat_o_core[5]
  PIN mprj_dat_o_core[6]
    DIRECTION INPUT ;
    PORT
      LAYER met2 ;
        RECT 808.770 0.000 809.050 4.000 ;
    END
  END mprj_dat_o_core[6]
  PIN mprj_dat_o_core[7]
    DIRECTION INPUT ;
    PORT
      LAYER met2 ;
        RECT 810.610 0.000 810.890 4.000 ;
    END
  END mprj_dat_o_core[7]
  PIN mprj_dat_o_core[8]
    DIRECTION INPUT ;
    PORT
      LAYER met2 ;
        RECT 812.450 0.000 812.730 4.000 ;
    END
  END mprj_dat_o_core[8]
  PIN mprj_dat_o_core[9]
    DIRECTION INPUT ;
    PORT
      LAYER met2 ;
        RECT 814.290 0.000 814.570 4.000 ;
    END
  END mprj_dat_o_core[9]
  PIN mprj_dat_o_user[0]
    DIRECTION OUTPUT TRISTATE ;
    PORT
      LAYER met2 ;
        RECT 750.810 61.000 751.090 65.000 ;
    END
  END mprj_dat_o_user[0]
  PIN mprj_dat_o_user[10]
    DIRECTION OUTPUT TRISTATE ;
    PORT
      LAYER met2 ;
        RECT 752.650 61.000 752.930 65.000 ;
    END
  END mprj_dat_o_user[10]
  PIN mprj_dat_o_user[11]
    DIRECTION OUTPUT TRISTATE ;
    PORT
      LAYER met2 ;
        RECT 754.490 61.000 754.770 65.000 ;
    END
  END mprj_dat_o_user[11]
  PIN mprj_dat_o_user[12]
    DIRECTION OUTPUT TRISTATE ;
    PORT
      LAYER met2 ;
        RECT 756.330 61.000 756.610 65.000 ;
    END
  END mprj_dat_o_user[12]
  PIN mprj_dat_o_user[13]
    DIRECTION OUTPUT TRISTATE ;
    PORT
      LAYER met2 ;
        RECT 758.170 61.000 758.450 65.000 ;
    END
  END mprj_dat_o_user[13]
  PIN mprj_dat_o_user[14]
    DIRECTION OUTPUT TRISTATE ;
    PORT
      LAYER met2 ;
        RECT 760.010 61.000 760.290 65.000 ;
    END
  END mprj_dat_o_user[14]
  PIN mprj_dat_o_user[15]
    DIRECTION OUTPUT TRISTATE ;
    PORT
      LAYER met2 ;
        RECT 761.850 61.000 762.130 65.000 ;
    END
  END mprj_dat_o_user[15]
  PIN mprj_dat_o_user[16]
    DIRECTION OUTPUT TRISTATE ;
    PORT
      LAYER met2 ;
        RECT 763.690 61.000 763.970 65.000 ;
    END
  END mprj_dat_o_user[16]
  PIN mprj_dat_o_user[17]
    DIRECTION OUTPUT TRISTATE ;
    PORT
      LAYER met2 ;
        RECT 765.530 61.000 765.810 65.000 ;
    END
  END mprj_dat_o_user[17]
  PIN mprj_dat_o_user[18]
    DIRECTION OUTPUT TRISTATE ;
    PORT
      LAYER met2 ;
        RECT 767.370 61.000 767.650 65.000 ;
    END
  END mprj_dat_o_user[18]
  PIN mprj_dat_o_user[19]
    DIRECTION OUTPUT TRISTATE ;
    PORT
      LAYER met2 ;
        RECT 769.210 61.000 769.490 65.000 ;
    END
  END mprj_dat_o_user[19]
  PIN mprj_dat_o_user[1]
    DIRECTION OUTPUT TRISTATE ;
    PORT
      LAYER met2 ;
        RECT 771.050 61.000 771.330 65.000 ;
    END
  END mprj_dat_o_user[1]
  PIN mprj_dat_o_user[20]
    DIRECTION OUTPUT TRISTATE ;
    PORT
      LAYER met2 ;
        RECT 772.890 61.000 773.170 65.000 ;
    END
  END mprj_dat_o_user[20]
  PIN mprj_dat_o_user[21]
    DIRECTION OUTPUT TRISTATE ;
    PORT
      LAYER met2 ;
        RECT 774.730 61.000 775.010 65.000 ;
    END
  END mprj_dat_o_user[21]
  PIN mprj_dat_o_user[22]
    DIRECTION OUTPUT TRISTATE ;
    PORT
      LAYER met2 ;
        RECT 776.570 61.000 776.850 65.000 ;
    END
  END mprj_dat_o_user[22]
  PIN mprj_dat_o_user[23]
    DIRECTION OUTPUT TRISTATE ;
    PORT
      LAYER met2 ;
        RECT 778.410 61.000 778.690 65.000 ;
    END
  END mprj_dat_o_user[23]
  PIN mprj_dat_o_user[24]
    DIRECTION OUTPUT TRISTATE ;
    PORT
      LAYER met2 ;
        RECT 780.250 61.000 780.530 65.000 ;
    END
  END mprj_dat_o_user[24]
  PIN mprj_dat_o_user[25]
    DIRECTION OUTPUT TRISTATE ;
    PORT
      LAYER met2 ;
        RECT 782.090 61.000 782.370 65.000 ;
    END
  END mprj_dat_o_user[25]
  PIN mprj_dat_o_user[26]
    DIRECTION OUTPUT TRISTATE ;
    PORT
      LAYER met2 ;
        RECT 783.930 61.000 784.210 65.000 ;
    END
  END mprj_dat_o_user[26]
  PIN mprj_dat_o_user[27]
    DIRECTION OUTPUT TRISTATE ;
    PORT
      LAYER met2 ;
        RECT 785.770 61.000 786.050 65.000 ;
    END
  END mprj_dat_o_user[27]
  PIN mprj_dat_o_user[28]
    DIRECTION OUTPUT TRISTATE ;
    PORT
      LAYER met2 ;
        RECT 787.610 61.000 787.890 65.000 ;
    END
  END mprj_dat_o_user[28]
  PIN mprj_dat_o_user[29]
    DIRECTION OUTPUT TRISTATE ;
    PORT
      LAYER met2 ;
        RECT 789.450 61.000 789.730 65.000 ;
    END
  END mprj_dat_o_user[29]
  PIN mprj_dat_o_user[2]
    DIRECTION OUTPUT TRISTATE ;
    PORT
      LAYER met2 ;
        RECT 791.290 61.000 791.570 65.000 ;
    END
  END mprj_dat_o_user[2]
  PIN mprj_dat_o_user[30]
    DIRECTION OUTPUT TRISTATE ;
    PORT
      LAYER met2 ;
        RECT 793.130 61.000 793.410 65.000 ;
    END
  END mprj_dat_o_user[30]
  PIN mprj_dat_o_user[31]
    DIRECTION OUTPUT TRISTATE ;
    PORT
      LAYER met2 ;
        RECT 794.970 61.000 795.250 65.000 ;
    END
  END mprj_dat_o_user[31]
  PIN mprj_dat_o_user[3]
    DIRECTION OUTPUT TRISTATE ;
    PORT
      LAYER met2 ;
        RECT 796.810 61.000 797.090 65.000 ;
    END
  END mprj_dat_o_user[3]
  PIN mprj_dat_o_user[4]
    DIRECTION OUTPUT TRISTATE ;
    PORT
      LAYER met2 ;
        RECT 798.650 61.000 798.930 65.000 ;
    END
  END mprj_dat_o_user[4]
  PIN mprj_dat_o_user[5]
    DIRECTION OUTPUT TRISTATE ;
    PORT
      LAYER met2 ;
        RECT 800.490 61.000 800.770 65.000 ;
    END
  END mprj_dat_o_user[5]
  PIN mprj_dat_o_user[6]
    DIRECTION OUTPUT TRISTATE ;
    PORT
      LAYER met2 ;
        RECT 802.330 61.000 802.610 65.000 ;
    END
  END mprj_dat_o_user[6]
  PIN mprj_dat_o_user[7]
    DIRECTION OUTPUT TRISTATE ;
    PORT
      LAYER met2 ;
        RECT 804.170 61.000 804.450 65.000 ;
    END
  END mprj_dat_o_user[7]
  PIN mprj_dat_o_user[8]
    DIRECTION OUTPUT TRISTATE ;
    PORT
      LAYER met2 ;
        RECT 806.010 61.000 806.290 65.000 ;
    END
  END mprj_dat_o_user[8]
  PIN mprj_dat_o_user[9]
    DIRECTION OUTPUT TRISTATE ;
    PORT
      LAYER met2 ;
        RECT 807.850 61.000 808.130 65.000 ;
    END
  END mprj_dat_o_user[9]
  PIN mprj_sel_o_core[0]
    DIRECTION INPUT ;
    PORT
      LAYER met2 ;
        RECT 816.130 0.000 816.410 4.000 ;
    END
  END mprj_sel_o_core[0]
  PIN mprj_sel_o_core[1]
    DIRECTION INPUT ;
    PORT
      LAYER met2 ;
        RECT 817.970 0.000 818.250 4.000 ;
    END
  END mprj_sel_o_core[1]
  PIN mprj_sel_o_core[2]
    DIRECTION INPUT ;
    PORT
      LAYER met2 ;
        RECT 819.810 0.000 820.090 4.000 ;
    END
  END mprj_sel_o_core[2]
  PIN mprj_sel_o_core[3]
    DIRECTION INPUT ;
    PORT
      LAYER met2 ;
        RECT 821.650 0.000 821.930 4.000 ;
    END
  END mprj_sel_o_core[3]
  PIN mprj_sel_o_user[0]
    DIRECTION OUTPUT TRISTATE ;
    PORT
      LAYER met2 ;
        RECT 809.690 61.000 809.970 65.000 ;
    END
  END mprj_sel_o_user[0]
  PIN mprj_sel_o_user[1]
    DIRECTION OUTPUT TRISTATE ;
    PORT
      LAYER met2 ;
        RECT 811.530 61.000 811.810 65.000 ;
    END
  END mprj_sel_o_user[1]
  PIN mprj_sel_o_user[2]
    DIRECTION OUTPUT TRISTATE ;
    PORT
      LAYER met2 ;
        RECT 813.370 61.000 813.650 65.000 ;
    END
  END mprj_sel_o_user[2]
  PIN mprj_sel_o_user[3]
    DIRECTION OUTPUT TRISTATE ;
    PORT
      LAYER met2 ;
        RECT 815.210 61.000 815.490 65.000 ;
    END
  END mprj_sel_o_user[3]
  PIN mprj_stb_o_core
    DIRECTION INPUT ;
    PORT
      LAYER met2 ;
        RECT 823.490 0.000 823.770 4.000 ;
    END
  END mprj_stb_o_core
  PIN mprj_stb_o_user
    DIRECTION OUTPUT TRISTATE ;
    PORT
      LAYER met2 ;
        RECT 817.050 61.000 817.330 65.000 ;
    END
  END mprj_stb_o_user
  PIN mprj_we_o_core
    DIRECTION INPUT ;
    PORT
      LAYER met2 ;
        RECT 825.330 0.000 825.610 4.000 ;
    END
  END mprj_we_o_core
  PIN mprj_we_o_user
    DIRECTION OUTPUT TRISTATE ;
    PORT
      LAYER met2 ;
        RECT 818.890 61.000 819.170 65.000 ;
    END
  END mprj_we_o_user
  PIN user1_vcc_powergood
    DIRECTION OUTPUT TRISTATE ;
    PORT
      LAYER met2 ;
        RECT 827.170 0.000 827.450 4.000 ;
    END
  END user1_vcc_powergood
  PIN user1_vdd_powergood
    DIRECTION OUTPUT TRISTATE ;
    PORT
      LAYER met2 ;
        RECT 829.010 0.000 829.290 4.000 ;
    END
  END user1_vdd_powergood
  PIN user2_vcc_powergood
    DIRECTION OUTPUT TRISTATE ;
    PORT
      LAYER met2 ;
        RECT 830.850 0.000 831.130 4.000 ;
    END
  END user2_vcc_powergood
  PIN user2_vdd_powergood
    DIRECTION OUTPUT TRISTATE ;
    PORT
      LAYER met2 ;
        RECT 832.690 0.000 832.970 4.000 ;
    END
  END user2_vdd_powergood
  PIN user_clock
    DIRECTION OUTPUT TRISTATE ;
    PORT
      LAYER met2 ;
        RECT 820.730 61.000 821.010 65.000 ;
    END
  END user_clock
  PIN user_clock2
    DIRECTION OUTPUT TRISTATE ;
    PORT
      LAYER met2 ;
        RECT 822.570 61.000 822.850 65.000 ;
    END
  END user_clock2
  PIN user_reset
    DIRECTION OUTPUT TRISTATE ;
    PORT
      LAYER met2 ;
        RECT 824.410 61.000 824.690 65.000 ;
    END
  END user_reset
  PIN user_resetn
    DIRECTION OUTPUT TRISTATE ;
    PORT
      LAYER met2 ;
        RECT 3.770 0.000 4.050 4.000 ;
    END
  END user_resetn
  PIN VPWR
    DIRECTION INPUT ;
    USE POWER ;
    PORT
      LAYER met1 ;
        RECT 1.840 56.880 847.780 57.360 ;
    END
  END VPWR
  PIN VGND
    DIRECTION INPUT ;
    USE GROUND ;
    PORT
      LAYER met1 ;
        RECT 1.840 59.600 847.780 60.080 ;
    END
  END VGND
  OBS
      LAYER li1 ;
        RECT 1.840 0.085 847.780 64.855 ;
      LAYER met1 ;
        RECT 1.840 60.360 847.780 64.900 ;
        RECT 1.840 57.640 847.780 59.320 ;
        RECT 1.840 0.040 847.780 56.600 ;
      LAYER met2 ;
        RECT 2.860 60.720 3.490 65.125 ;
        RECT 4.330 60.720 5.330 65.125 ;
        RECT 6.170 60.720 7.170 65.125 ;
        RECT 8.010 60.720 9.010 65.125 ;
        RECT 9.850 60.720 10.850 65.125 ;
        RECT 11.690 60.720 12.690 65.125 ;
        RECT 13.530 60.720 14.530 65.125 ;
        RECT 15.370 60.720 16.370 65.125 ;
        RECT 17.210 60.720 18.210 65.125 ;
        RECT 19.050 60.720 20.050 65.125 ;
        RECT 20.890 60.720 21.890 65.125 ;
        RECT 22.730 60.720 23.730 65.125 ;
        RECT 24.570 60.720 25.570 65.125 ;
        RECT 26.410 60.720 27.410 65.125 ;
        RECT 28.250 60.720 29.250 65.125 ;
        RECT 30.090 60.720 31.090 65.125 ;
        RECT 31.930 60.720 32.930 65.125 ;
        RECT 33.770 60.720 34.770 65.125 ;
        RECT 35.610 60.720 36.610 65.125 ;
        RECT 37.450 60.720 38.450 65.125 ;
        RECT 39.290 60.720 40.290 65.125 ;
        RECT 41.130 60.720 42.130 65.125 ;
        RECT 42.970 60.720 43.970 65.125 ;
        RECT 44.810 60.720 45.810 65.125 ;
        RECT 46.650 60.720 47.650 65.125 ;
        RECT 48.490 60.720 49.490 65.125 ;
        RECT 50.330 60.720 51.330 65.125 ;
        RECT 52.170 60.720 53.170 65.125 ;
        RECT 54.010 60.720 55.010 65.125 ;
        RECT 55.850 60.720 56.850 65.125 ;
        RECT 57.690 60.720 58.690 65.125 ;
        RECT 59.530 60.720 60.530 65.125 ;
        RECT 61.370 60.720 62.370 65.125 ;
        RECT 63.210 60.720 64.210 65.125 ;
        RECT 65.050 60.720 66.050 65.125 ;
        RECT 66.890 60.720 67.890 65.125 ;
        RECT 68.730 60.720 69.730 65.125 ;
        RECT 70.570 60.720 71.570 65.125 ;
        RECT 72.410 60.720 73.410 65.125 ;
        RECT 74.250 60.720 75.250 65.125 ;
        RECT 76.090 60.720 77.090 65.125 ;
        RECT 77.930 60.720 78.930 65.125 ;
        RECT 79.770 60.720 80.770 65.125 ;
        RECT 81.610 60.720 82.610 65.125 ;
        RECT 83.450 60.720 84.450 65.125 ;
        RECT 85.290 60.720 86.290 65.125 ;
        RECT 87.130 60.720 88.130 65.125 ;
        RECT 88.970 60.720 89.970 65.125 ;
        RECT 90.810 60.720 91.810 65.125 ;
        RECT 92.650 60.720 93.650 65.125 ;
        RECT 94.490 60.720 95.490 65.125 ;
        RECT 96.330 60.720 97.330 65.125 ;
        RECT 98.170 60.720 99.170 65.125 ;
        RECT 100.010 60.720 101.010 65.125 ;
        RECT 101.850 60.720 102.850 65.125 ;
        RECT 103.690 60.720 104.690 65.125 ;
        RECT 105.530 60.720 106.530 65.125 ;
        RECT 107.370 60.720 108.370 65.125 ;
        RECT 109.210 60.720 110.210 65.125 ;
        RECT 111.050 60.720 112.050 65.125 ;
        RECT 112.890 60.720 113.890 65.125 ;
        RECT 114.730 60.720 115.730 65.125 ;
        RECT 116.570 60.720 117.570 65.125 ;
        RECT 118.410 60.720 119.410 65.125 ;
        RECT 120.250 60.720 121.250 65.125 ;
        RECT 122.090 60.720 123.090 65.125 ;
        RECT 123.930 60.720 124.930 65.125 ;
        RECT 125.770 60.720 126.770 65.125 ;
        RECT 127.610 60.720 128.610 65.125 ;
        RECT 129.450 60.720 130.450 65.125 ;
        RECT 131.290 60.720 132.290 65.125 ;
        RECT 133.130 60.720 134.130 65.125 ;
        RECT 134.970 60.720 135.970 65.125 ;
        RECT 136.810 60.720 137.810 65.125 ;
        RECT 138.650 60.720 139.650 65.125 ;
        RECT 140.490 60.720 141.490 65.125 ;
        RECT 142.330 60.720 143.330 65.125 ;
        RECT 144.170 60.720 145.170 65.125 ;
        RECT 146.010 60.720 147.010 65.125 ;
        RECT 147.850 60.720 148.850 65.125 ;
        RECT 149.690 60.720 150.690 65.125 ;
        RECT 151.530 60.720 152.530 65.125 ;
        RECT 153.370 60.720 154.370 65.125 ;
        RECT 155.210 60.720 156.210 65.125 ;
        RECT 157.050 60.720 158.050 65.125 ;
        RECT 158.890 60.720 159.890 65.125 ;
        RECT 160.730 60.720 161.730 65.125 ;
        RECT 162.570 60.720 163.570 65.125 ;
        RECT 164.410 60.720 165.410 65.125 ;
        RECT 166.250 60.720 167.250 65.125 ;
        RECT 168.090 60.720 169.090 65.125 ;
        RECT 169.930 60.720 170.930 65.125 ;
        RECT 171.770 60.720 172.770 65.125 ;
        RECT 173.610 60.720 174.610 65.125 ;
        RECT 175.450 60.720 176.450 65.125 ;
        RECT 177.290 60.720 178.290 65.125 ;
        RECT 179.130 60.720 180.130 65.125 ;
        RECT 180.970 60.720 181.970 65.125 ;
        RECT 182.810 60.720 183.810 65.125 ;
        RECT 184.650 60.720 185.650 65.125 ;
        RECT 186.490 60.720 187.490 65.125 ;
        RECT 188.330 60.720 189.330 65.125 ;
        RECT 190.170 60.720 191.170 65.125 ;
        RECT 192.010 60.720 193.010 65.125 ;
        RECT 193.850 60.720 194.850 65.125 ;
        RECT 195.690 60.720 196.690 65.125 ;
        RECT 197.530 60.720 198.530 65.125 ;
        RECT 199.370 60.720 200.370 65.125 ;
        RECT 201.210 60.720 202.210 65.125 ;
        RECT 203.050 60.720 204.050 65.125 ;
        RECT 204.890 60.720 205.890 65.125 ;
        RECT 206.730 60.720 207.730 65.125 ;
        RECT 208.570 60.720 209.570 65.125 ;
        RECT 210.410 60.720 211.410 65.125 ;
        RECT 212.250 60.720 213.250 65.125 ;
        RECT 214.090 60.720 215.090 65.125 ;
        RECT 215.930 60.720 216.930 65.125 ;
        RECT 217.770 60.720 218.770 65.125 ;
        RECT 219.610 60.720 220.610 65.125 ;
        RECT 221.450 60.720 222.450 65.125 ;
        RECT 223.290 60.720 224.290 65.125 ;
        RECT 225.130 60.720 226.130 65.125 ;
        RECT 226.970 60.720 227.970 65.125 ;
        RECT 228.810 60.720 229.810 65.125 ;
        RECT 230.650 60.720 231.650 65.125 ;
        RECT 232.490 60.720 233.490 65.125 ;
        RECT 234.330 60.720 235.330 65.125 ;
        RECT 236.170 60.720 237.170 65.125 ;
        RECT 238.010 60.720 239.010 65.125 ;
        RECT 239.850 60.720 240.850 65.125 ;
        RECT 241.690 60.720 242.690 65.125 ;
        RECT 243.530 60.720 244.530 65.125 ;
        RECT 245.370 60.720 246.370 65.125 ;
        RECT 247.210 60.720 248.210 65.125 ;
        RECT 249.050 60.720 250.050 65.125 ;
        RECT 250.890 60.720 251.890 65.125 ;
        RECT 252.730 60.720 253.730 65.125 ;
        RECT 254.570 60.720 255.570 65.125 ;
        RECT 256.410 60.720 257.410 65.125 ;
        RECT 258.250 60.720 259.250 65.125 ;
        RECT 260.090 60.720 261.090 65.125 ;
        RECT 261.930 60.720 262.930 65.125 ;
        RECT 263.770 60.720 264.770 65.125 ;
        RECT 265.610 60.720 266.610 65.125 ;
        RECT 267.450 60.720 268.450 65.125 ;
        RECT 269.290 60.720 270.290 65.125 ;
        RECT 271.130 60.720 272.130 65.125 ;
        RECT 272.970 60.720 273.970 65.125 ;
        RECT 274.810 60.720 275.810 65.125 ;
        RECT 276.650 60.720 277.650 65.125 ;
        RECT 278.490 60.720 279.490 65.125 ;
        RECT 280.330 60.720 281.330 65.125 ;
        RECT 282.170 60.720 283.170 65.125 ;
        RECT 284.010 60.720 285.010 65.125 ;
        RECT 285.850 60.720 286.850 65.125 ;
        RECT 287.690 60.720 288.690 65.125 ;
        RECT 289.530 60.720 290.530 65.125 ;
        RECT 291.370 60.720 292.370 65.125 ;
        RECT 293.210 60.720 294.210 65.125 ;
        RECT 295.050 60.720 296.050 65.125 ;
        RECT 296.890 60.720 297.890 65.125 ;
        RECT 298.730 60.720 299.730 65.125 ;
        RECT 300.570 60.720 301.570 65.125 ;
        RECT 302.410 60.720 303.410 65.125 ;
        RECT 304.250 60.720 305.250 65.125 ;
        RECT 306.090 60.720 307.090 65.125 ;
        RECT 307.930 60.720 308.930 65.125 ;
        RECT 309.770 60.720 310.770 65.125 ;
        RECT 311.610 60.720 312.610 65.125 ;
        RECT 313.450 60.720 314.450 65.125 ;
        RECT 315.290 60.720 316.290 65.125 ;
        RECT 317.130 60.720 318.130 65.125 ;
        RECT 318.970 60.720 319.970 65.125 ;
        RECT 320.810 60.720 321.810 65.125 ;
        RECT 322.650 60.720 323.650 65.125 ;
        RECT 324.490 60.720 325.490 65.125 ;
        RECT 326.330 60.720 327.330 65.125 ;
        RECT 328.170 60.720 329.170 65.125 ;
        RECT 330.010 60.720 331.010 65.125 ;
        RECT 331.850 60.720 332.850 65.125 ;
        RECT 333.690 60.720 334.690 65.125 ;
        RECT 335.530 60.720 336.530 65.125 ;
        RECT 337.370 60.720 338.370 65.125 ;
        RECT 339.210 60.720 340.210 65.125 ;
        RECT 341.050 60.720 342.050 65.125 ;
        RECT 342.890 60.720 343.890 65.125 ;
        RECT 344.730 60.720 345.730 65.125 ;
        RECT 346.570 60.720 347.570 65.125 ;
        RECT 348.410 60.720 349.410 65.125 ;
        RECT 350.250 60.720 351.250 65.125 ;
        RECT 352.090 60.720 353.090 65.125 ;
        RECT 353.930 60.720 354.930 65.125 ;
        RECT 355.770 60.720 356.770 65.125 ;
        RECT 357.610 60.720 358.610 65.125 ;
        RECT 359.450 60.720 360.450 65.125 ;
        RECT 361.290 60.720 362.290 65.125 ;
        RECT 363.130 60.720 364.130 65.125 ;
        RECT 364.970 60.720 365.970 65.125 ;
        RECT 366.810 60.720 367.810 65.125 ;
        RECT 368.650 60.720 369.650 65.125 ;
        RECT 370.490 60.720 371.490 65.125 ;
        RECT 372.330 60.720 373.330 65.125 ;
        RECT 374.170 60.720 375.170 65.125 ;
        RECT 376.010 60.720 377.010 65.125 ;
        RECT 377.850 60.720 378.850 65.125 ;
        RECT 379.690 60.720 380.690 65.125 ;
        RECT 381.530 60.720 382.530 65.125 ;
        RECT 383.370 60.720 384.370 65.125 ;
        RECT 385.210 60.720 386.210 65.125 ;
        RECT 387.050 60.720 388.050 65.125 ;
        RECT 388.890 60.720 389.890 65.125 ;
        RECT 390.730 60.720 391.730 65.125 ;
        RECT 392.570 60.720 393.570 65.125 ;
        RECT 394.410 60.720 395.410 65.125 ;
        RECT 396.250 60.720 397.250 65.125 ;
        RECT 398.090 60.720 399.090 65.125 ;
        RECT 399.930 60.720 400.930 65.125 ;
        RECT 401.770 60.720 402.770 65.125 ;
        RECT 403.610 60.720 404.610 65.125 ;
        RECT 405.450 60.720 406.450 65.125 ;
        RECT 407.290 60.720 408.290 65.125 ;
        RECT 409.130 60.720 410.130 65.125 ;
        RECT 410.970 60.720 411.970 65.125 ;
        RECT 412.810 60.720 413.810 65.125 ;
        RECT 414.650 60.720 415.650 65.125 ;
        RECT 416.490 60.720 417.490 65.125 ;
        RECT 418.330 60.720 419.330 65.125 ;
        RECT 420.170 60.720 421.170 65.125 ;
        RECT 422.010 60.720 423.010 65.125 ;
        RECT 423.850 60.720 424.850 65.125 ;
        RECT 425.690 60.720 426.690 65.125 ;
        RECT 427.530 60.720 428.530 65.125 ;
        RECT 429.370 60.720 430.370 65.125 ;
        RECT 431.210 60.720 432.210 65.125 ;
        RECT 433.050 60.720 434.050 65.125 ;
        RECT 434.890 60.720 435.890 65.125 ;
        RECT 436.730 60.720 437.730 65.125 ;
        RECT 438.570 60.720 439.570 65.125 ;
        RECT 440.410 60.720 441.410 65.125 ;
        RECT 442.250 60.720 443.250 65.125 ;
        RECT 444.090 60.720 445.090 65.125 ;
        RECT 445.930 60.720 446.930 65.125 ;
        RECT 447.770 60.720 448.770 65.125 ;
        RECT 449.610 60.720 450.610 65.125 ;
        RECT 451.450 60.720 452.450 65.125 ;
        RECT 453.290 60.720 454.290 65.125 ;
        RECT 455.130 60.720 456.130 65.125 ;
        RECT 456.970 60.720 457.970 65.125 ;
        RECT 458.810 60.720 459.810 65.125 ;
        RECT 460.650 60.720 461.650 65.125 ;
        RECT 462.490 60.720 463.490 65.125 ;
        RECT 464.330 60.720 465.330 65.125 ;
        RECT 466.170 60.720 467.170 65.125 ;
        RECT 468.010 60.720 469.010 65.125 ;
        RECT 469.850 60.720 470.850 65.125 ;
        RECT 471.690 60.720 472.690 65.125 ;
        RECT 473.530 60.720 474.530 65.125 ;
        RECT 475.370 60.720 476.370 65.125 ;
        RECT 477.210 60.720 478.210 65.125 ;
        RECT 479.050 60.720 480.050 65.125 ;
        RECT 480.890 60.720 481.890 65.125 ;
        RECT 482.730 60.720 483.730 65.125 ;
        RECT 484.570 60.720 485.570 65.125 ;
        RECT 486.410 60.720 487.410 65.125 ;
        RECT 488.250 60.720 489.250 65.125 ;
        RECT 490.090 60.720 491.090 65.125 ;
        RECT 491.930 60.720 492.930 65.125 ;
        RECT 493.770 60.720 494.770 65.125 ;
        RECT 495.610 60.720 496.610 65.125 ;
        RECT 497.450 60.720 498.450 65.125 ;
        RECT 499.290 60.720 500.290 65.125 ;
        RECT 501.130 60.720 502.130 65.125 ;
        RECT 502.970 60.720 503.970 65.125 ;
        RECT 504.810 60.720 505.810 65.125 ;
        RECT 506.650 60.720 507.650 65.125 ;
        RECT 508.490 60.720 509.490 65.125 ;
        RECT 510.330 60.720 511.330 65.125 ;
        RECT 512.170 60.720 513.170 65.125 ;
        RECT 514.010 60.720 515.010 65.125 ;
        RECT 515.850 60.720 516.850 65.125 ;
        RECT 517.690 60.720 518.690 65.125 ;
        RECT 519.530 60.720 520.530 65.125 ;
        RECT 521.370 60.720 522.370 65.125 ;
        RECT 523.210 60.720 524.210 65.125 ;
        RECT 525.050 60.720 526.050 65.125 ;
        RECT 526.890 60.720 527.890 65.125 ;
        RECT 528.730 60.720 529.730 65.125 ;
        RECT 530.570 60.720 531.570 65.125 ;
        RECT 532.410 60.720 533.410 65.125 ;
        RECT 534.250 60.720 535.250 65.125 ;
        RECT 536.090 60.720 537.090 65.125 ;
        RECT 537.930 60.720 538.930 65.125 ;
        RECT 539.770 60.720 540.770 65.125 ;
        RECT 541.610 60.720 542.610 65.125 ;
        RECT 543.450 60.720 544.450 65.125 ;
        RECT 545.290 60.720 546.290 65.125 ;
        RECT 547.130 60.720 548.130 65.125 ;
        RECT 548.970 60.720 549.970 65.125 ;
        RECT 550.810 60.720 551.810 65.125 ;
        RECT 552.650 60.720 553.650 65.125 ;
        RECT 554.490 60.720 555.490 65.125 ;
        RECT 556.330 60.720 557.330 65.125 ;
        RECT 558.170 60.720 559.170 65.125 ;
        RECT 560.010 60.720 561.010 65.125 ;
        RECT 561.850 60.720 562.850 65.125 ;
        RECT 563.690 60.720 564.690 65.125 ;
        RECT 565.530 60.720 566.530 65.125 ;
        RECT 567.370 60.720 568.370 65.125 ;
        RECT 569.210 60.720 570.210 65.125 ;
        RECT 571.050 60.720 572.050 65.125 ;
        RECT 572.890 60.720 573.890 65.125 ;
        RECT 574.730 60.720 575.730 65.125 ;
        RECT 576.570 60.720 577.570 65.125 ;
        RECT 578.410 60.720 579.410 65.125 ;
        RECT 580.250 60.720 581.250 65.125 ;
        RECT 582.090 60.720 583.090 65.125 ;
        RECT 583.930 60.720 584.930 65.125 ;
        RECT 585.770 60.720 586.770 65.125 ;
        RECT 587.610 60.720 588.610 65.125 ;
        RECT 589.450 60.720 590.450 65.125 ;
        RECT 591.290 60.720 592.290 65.125 ;
        RECT 593.130 60.720 594.130 65.125 ;
        RECT 594.970 60.720 595.970 65.125 ;
        RECT 596.810 60.720 597.810 65.125 ;
        RECT 598.650 60.720 599.650 65.125 ;
        RECT 600.490 60.720 601.490 65.125 ;
        RECT 602.330 60.720 603.330 65.125 ;
        RECT 604.170 60.720 605.170 65.125 ;
        RECT 606.010 60.720 607.010 65.125 ;
        RECT 607.850 60.720 608.850 65.125 ;
        RECT 609.690 60.720 610.690 65.125 ;
        RECT 611.530 60.720 612.530 65.125 ;
        RECT 613.370 60.720 614.370 65.125 ;
        RECT 615.210 60.720 616.210 65.125 ;
        RECT 617.050 60.720 618.050 65.125 ;
        RECT 618.890 60.720 619.890 65.125 ;
        RECT 620.730 60.720 621.730 65.125 ;
        RECT 622.570 60.720 623.570 65.125 ;
        RECT 624.410 60.720 625.410 65.125 ;
        RECT 626.250 60.720 627.250 65.125 ;
        RECT 628.090 60.720 629.090 65.125 ;
        RECT 629.930 60.720 630.930 65.125 ;
        RECT 631.770 60.720 632.770 65.125 ;
        RECT 633.610 60.720 634.610 65.125 ;
        RECT 635.450 60.720 636.450 65.125 ;
        RECT 637.290 60.720 638.290 65.125 ;
        RECT 639.130 60.720 640.130 65.125 ;
        RECT 640.970 60.720 641.970 65.125 ;
        RECT 642.810 60.720 643.810 65.125 ;
        RECT 644.650 60.720 645.650 65.125 ;
        RECT 646.490 60.720 647.490 65.125 ;
        RECT 648.330 60.720 649.330 65.125 ;
        RECT 650.170 60.720 651.170 65.125 ;
        RECT 652.010 60.720 653.010 65.125 ;
        RECT 653.850 60.720 654.850 65.125 ;
        RECT 655.690 60.720 656.690 65.125 ;
        RECT 657.530 60.720 658.530 65.125 ;
        RECT 659.370 60.720 660.370 65.125 ;
        RECT 661.210 60.720 662.210 65.125 ;
        RECT 663.050 60.720 664.050 65.125 ;
        RECT 664.890 60.720 665.890 65.125 ;
        RECT 666.730 60.720 667.730 65.125 ;
        RECT 668.570 60.720 669.570 65.125 ;
        RECT 670.410 60.720 671.410 65.125 ;
        RECT 672.250 60.720 673.250 65.125 ;
        RECT 674.090 60.720 675.090 65.125 ;
        RECT 675.930 60.720 676.930 65.125 ;
        RECT 677.770 60.720 678.770 65.125 ;
        RECT 679.610 60.720 680.610 65.125 ;
        RECT 681.450 60.720 682.450 65.125 ;
        RECT 683.290 60.720 684.290 65.125 ;
        RECT 685.130 60.720 686.130 65.125 ;
        RECT 686.970 60.720 687.970 65.125 ;
        RECT 688.810 60.720 689.810 65.125 ;
        RECT 690.650 60.720 691.650 65.125 ;
        RECT 692.490 60.720 693.490 65.125 ;
        RECT 694.330 60.720 695.330 65.125 ;
        RECT 696.170 60.720 697.170 65.125 ;
        RECT 698.010 60.720 699.010 65.125 ;
        RECT 699.850 60.720 700.850 65.125 ;
        RECT 701.690 60.720 702.690 65.125 ;
        RECT 703.530 60.720 704.530 65.125 ;
        RECT 705.370 60.720 706.370 65.125 ;
        RECT 707.210 60.720 708.210 65.125 ;
        RECT 709.050 60.720 710.050 65.125 ;
        RECT 710.890 60.720 711.890 65.125 ;
        RECT 712.730 60.720 713.730 65.125 ;
        RECT 714.570 60.720 715.570 65.125 ;
        RECT 716.410 60.720 717.410 65.125 ;
        RECT 718.250 60.720 719.250 65.125 ;
        RECT 720.090 60.720 721.090 65.125 ;
        RECT 721.930 60.720 722.930 65.125 ;
        RECT 723.770 60.720 724.770 65.125 ;
        RECT 725.610 60.720 726.610 65.125 ;
        RECT 727.450 60.720 728.450 65.125 ;
        RECT 729.290 60.720 730.290 65.125 ;
        RECT 731.130 60.720 732.130 65.125 ;
        RECT 732.970 60.720 733.970 65.125 ;
        RECT 734.810 60.720 735.810 65.125 ;
        RECT 736.650 60.720 737.650 65.125 ;
        RECT 738.490 60.720 739.490 65.125 ;
        RECT 740.330 60.720 741.330 65.125 ;
        RECT 742.170 60.720 743.170 65.125 ;
        RECT 744.010 60.720 745.010 65.125 ;
        RECT 745.850 60.720 746.850 65.125 ;
        RECT 747.690 60.720 748.690 65.125 ;
        RECT 749.530 60.720 750.530 65.125 ;
        RECT 751.370 60.720 752.370 65.125 ;
        RECT 753.210 60.720 754.210 65.125 ;
        RECT 755.050 60.720 756.050 65.125 ;
        RECT 756.890 60.720 757.890 65.125 ;
        RECT 758.730 60.720 759.730 65.125 ;
        RECT 760.570 60.720 761.570 65.125 ;
        RECT 762.410 60.720 763.410 65.125 ;
        RECT 764.250 60.720 765.250 65.125 ;
        RECT 766.090 60.720 767.090 65.125 ;
        RECT 767.930 60.720 768.930 65.125 ;
        RECT 769.770 60.720 770.770 65.125 ;
        RECT 771.610 60.720 772.610 65.125 ;
        RECT 773.450 60.720 774.450 65.125 ;
        RECT 775.290 60.720 776.290 65.125 ;
        RECT 777.130 60.720 778.130 65.125 ;
        RECT 778.970 60.720 779.970 65.125 ;
        RECT 780.810 60.720 781.810 65.125 ;
        RECT 782.650 60.720 783.650 65.125 ;
        RECT 784.490 60.720 785.490 65.125 ;
        RECT 786.330 60.720 787.330 65.125 ;
        RECT 788.170 60.720 789.170 65.125 ;
        RECT 790.010 60.720 791.010 65.125 ;
        RECT 791.850 60.720 792.850 65.125 ;
        RECT 793.690 60.720 794.690 65.125 ;
        RECT 795.530 60.720 796.530 65.125 ;
        RECT 797.370 60.720 798.370 65.125 ;
        RECT 799.210 60.720 800.210 65.125 ;
        RECT 801.050 60.720 802.050 65.125 ;
        RECT 802.890 60.720 803.890 65.125 ;
        RECT 804.730 60.720 805.730 65.125 ;
        RECT 806.570 60.720 807.570 65.125 ;
        RECT 808.410 60.720 809.410 65.125 ;
        RECT 810.250 60.720 811.250 65.125 ;
        RECT 812.090 60.720 813.090 65.125 ;
        RECT 813.930 60.720 814.930 65.125 ;
        RECT 815.770 60.720 816.770 65.125 ;
        RECT 817.610 60.720 818.610 65.125 ;
        RECT 819.450 60.720 820.450 65.125 ;
        RECT 821.290 60.720 822.290 65.125 ;
        RECT 823.130 60.720 824.130 65.125 ;
        RECT 824.970 60.720 836.180 65.125 ;
        RECT 2.860 4.280 836.180 60.720 ;
        RECT 3.410 0.010 3.490 4.280 ;
        RECT 4.330 0.010 4.410 4.280 ;
        RECT 5.250 0.010 6.250 4.280 ;
        RECT 7.090 0.010 8.090 4.280 ;
        RECT 8.930 0.010 9.930 4.280 ;
        RECT 10.770 0.010 11.770 4.280 ;
        RECT 12.610 0.010 13.610 4.280 ;
        RECT 14.450 0.010 15.450 4.280 ;
        RECT 16.290 0.010 17.290 4.280 ;
        RECT 18.130 0.010 19.130 4.280 ;
        RECT 19.970 0.010 20.970 4.280 ;
        RECT 21.810 0.010 22.810 4.280 ;
        RECT 23.650 0.010 24.650 4.280 ;
        RECT 25.490 0.010 26.490 4.280 ;
        RECT 27.330 0.010 28.330 4.280 ;
        RECT 29.170 0.010 30.170 4.280 ;
        RECT 31.010 0.010 32.010 4.280 ;
        RECT 32.850 0.010 33.850 4.280 ;
        RECT 34.690 0.010 35.690 4.280 ;
        RECT 36.530 0.010 37.530 4.280 ;
        RECT 38.370 0.010 39.370 4.280 ;
        RECT 40.210 0.010 41.210 4.280 ;
        RECT 42.050 0.010 43.050 4.280 ;
        RECT 43.890 0.010 44.890 4.280 ;
        RECT 45.730 0.010 46.730 4.280 ;
        RECT 47.570 0.010 48.570 4.280 ;
        RECT 49.410 0.010 50.410 4.280 ;
        RECT 51.250 0.010 52.250 4.280 ;
        RECT 53.090 0.010 54.090 4.280 ;
        RECT 54.930 0.010 55.930 4.280 ;
        RECT 56.770 0.010 57.770 4.280 ;
        RECT 58.610 0.010 59.610 4.280 ;
        RECT 60.450 0.010 61.450 4.280 ;
        RECT 62.290 0.010 63.290 4.280 ;
        RECT 64.130 0.010 65.130 4.280 ;
        RECT 65.970 0.010 66.970 4.280 ;
        RECT 67.810 0.010 68.810 4.280 ;
        RECT 69.650 0.010 70.650 4.280 ;
        RECT 71.490 0.010 72.490 4.280 ;
        RECT 73.330 0.010 74.330 4.280 ;
        RECT 75.170 0.010 76.170 4.280 ;
        RECT 77.010 0.010 78.010 4.280 ;
        RECT 78.850 0.010 79.850 4.280 ;
        RECT 80.690 0.010 81.690 4.280 ;
        RECT 82.530 0.010 83.530 4.280 ;
        RECT 84.370 0.010 85.370 4.280 ;
        RECT 86.210 0.010 87.210 4.280 ;
        RECT 88.050 0.010 89.050 4.280 ;
        RECT 89.890 0.010 90.890 4.280 ;
        RECT 91.730 0.010 92.730 4.280 ;
        RECT 93.570 0.010 94.570 4.280 ;
        RECT 95.410 0.010 96.410 4.280 ;
        RECT 97.250 0.010 98.250 4.280 ;
        RECT 99.090 0.010 100.090 4.280 ;
        RECT 100.930 0.010 101.930 4.280 ;
        RECT 102.770 0.010 103.770 4.280 ;
        RECT 104.610 0.010 105.610 4.280 ;
        RECT 106.450 0.010 107.450 4.280 ;
        RECT 108.290 0.010 109.290 4.280 ;
        RECT 110.130 0.010 111.130 4.280 ;
        RECT 111.970 0.010 112.970 4.280 ;
        RECT 113.810 0.010 114.810 4.280 ;
        RECT 115.650 0.010 116.650 4.280 ;
        RECT 117.490 0.010 118.490 4.280 ;
        RECT 119.330 0.010 120.330 4.280 ;
        RECT 121.170 0.010 122.170 4.280 ;
        RECT 123.010 0.010 124.010 4.280 ;
        RECT 124.850 0.010 125.850 4.280 ;
        RECT 126.690 0.010 127.690 4.280 ;
        RECT 128.530 0.010 129.530 4.280 ;
        RECT 130.370 0.010 131.370 4.280 ;
        RECT 132.210 0.010 133.210 4.280 ;
        RECT 134.050 0.010 135.050 4.280 ;
        RECT 135.890 0.010 136.890 4.280 ;
        RECT 137.730 0.010 138.730 4.280 ;
        RECT 139.570 0.010 140.570 4.280 ;
        RECT 141.410 0.010 142.410 4.280 ;
        RECT 143.250 0.010 144.250 4.280 ;
        RECT 145.090 0.010 146.090 4.280 ;
        RECT 146.930 0.010 147.930 4.280 ;
        RECT 148.770 0.010 149.770 4.280 ;
        RECT 150.610 0.010 151.610 4.280 ;
        RECT 152.450 0.010 153.450 4.280 ;
        RECT 154.290 0.010 155.290 4.280 ;
        RECT 156.130 0.010 157.130 4.280 ;
        RECT 157.970 0.010 158.970 4.280 ;
        RECT 159.810 0.010 160.810 4.280 ;
        RECT 161.650 0.010 162.650 4.280 ;
        RECT 163.490 0.010 164.490 4.280 ;
        RECT 165.330 0.010 166.330 4.280 ;
        RECT 167.170 0.010 168.170 4.280 ;
        RECT 169.010 0.010 170.010 4.280 ;
        RECT 170.850 0.010 171.850 4.280 ;
        RECT 172.690 0.010 173.690 4.280 ;
        RECT 174.530 0.010 175.530 4.280 ;
        RECT 176.370 0.010 177.370 4.280 ;
        RECT 178.210 0.010 179.210 4.280 ;
        RECT 180.050 0.010 181.050 4.280 ;
        RECT 181.890 0.010 182.890 4.280 ;
        RECT 183.730 0.010 184.730 4.280 ;
        RECT 185.570 0.010 186.570 4.280 ;
        RECT 187.410 0.010 188.410 4.280 ;
        RECT 189.250 0.010 190.250 4.280 ;
        RECT 191.090 0.010 192.090 4.280 ;
        RECT 192.930 0.010 193.930 4.280 ;
        RECT 194.770 0.010 195.770 4.280 ;
        RECT 196.610 0.010 197.610 4.280 ;
        RECT 198.450 0.010 199.450 4.280 ;
        RECT 200.290 0.010 201.290 4.280 ;
        RECT 202.130 0.010 203.130 4.280 ;
        RECT 203.970 0.010 204.970 4.280 ;
        RECT 205.810 0.010 206.810 4.280 ;
        RECT 207.650 0.010 208.650 4.280 ;
        RECT 209.490 0.010 210.490 4.280 ;
        RECT 211.330 0.010 212.330 4.280 ;
        RECT 213.170 0.010 214.170 4.280 ;
        RECT 215.010 0.010 216.010 4.280 ;
        RECT 216.850 0.010 217.850 4.280 ;
        RECT 218.690 0.010 219.690 4.280 ;
        RECT 220.530 0.010 221.530 4.280 ;
        RECT 222.370 0.010 223.370 4.280 ;
        RECT 224.210 0.010 225.210 4.280 ;
        RECT 226.050 0.010 227.050 4.280 ;
        RECT 227.890 0.010 228.890 4.280 ;
        RECT 229.730 0.010 230.730 4.280 ;
        RECT 231.570 0.010 232.570 4.280 ;
        RECT 233.410 0.010 234.410 4.280 ;
        RECT 235.250 0.010 236.250 4.280 ;
        RECT 237.090 0.010 238.090 4.280 ;
        RECT 238.930 0.010 239.930 4.280 ;
        RECT 240.770 0.010 241.770 4.280 ;
        RECT 242.610 0.010 243.610 4.280 ;
        RECT 244.450 0.010 245.450 4.280 ;
        RECT 246.290 0.010 247.290 4.280 ;
        RECT 248.130 0.010 249.130 4.280 ;
        RECT 249.970 0.010 250.970 4.280 ;
        RECT 251.810 0.010 252.810 4.280 ;
        RECT 253.650 0.010 254.650 4.280 ;
        RECT 255.490 0.010 256.490 4.280 ;
        RECT 257.330 0.010 258.330 4.280 ;
        RECT 259.170 0.010 260.170 4.280 ;
        RECT 261.010 0.010 262.010 4.280 ;
        RECT 262.850 0.010 263.850 4.280 ;
        RECT 264.690 0.010 265.690 4.280 ;
        RECT 266.530 0.010 267.530 4.280 ;
        RECT 268.370 0.010 269.370 4.280 ;
        RECT 270.210 0.010 271.210 4.280 ;
        RECT 272.050 0.010 273.050 4.280 ;
        RECT 273.890 0.010 274.890 4.280 ;
        RECT 275.730 0.010 276.730 4.280 ;
        RECT 277.570 0.010 278.570 4.280 ;
        RECT 279.410 0.010 280.410 4.280 ;
        RECT 281.250 0.010 282.250 4.280 ;
        RECT 283.090 0.010 284.090 4.280 ;
        RECT 284.930 0.010 285.930 4.280 ;
        RECT 286.770 0.010 287.770 4.280 ;
        RECT 288.610 0.010 289.610 4.280 ;
        RECT 290.450 0.010 291.450 4.280 ;
        RECT 292.290 0.010 293.290 4.280 ;
        RECT 294.130 0.010 295.130 4.280 ;
        RECT 295.970 0.010 296.970 4.280 ;
        RECT 297.810 0.010 298.810 4.280 ;
        RECT 299.650 0.010 300.650 4.280 ;
        RECT 301.490 0.010 302.490 4.280 ;
        RECT 303.330 0.010 304.330 4.280 ;
        RECT 305.170 0.010 306.170 4.280 ;
        RECT 307.010 0.010 308.010 4.280 ;
        RECT 308.850 0.010 309.850 4.280 ;
        RECT 310.690 0.010 311.690 4.280 ;
        RECT 312.530 0.010 313.530 4.280 ;
        RECT 314.370 0.010 315.370 4.280 ;
        RECT 316.210 0.010 317.210 4.280 ;
        RECT 318.050 0.010 319.050 4.280 ;
        RECT 319.890 0.010 320.890 4.280 ;
        RECT 321.730 0.010 322.730 4.280 ;
        RECT 323.570 0.010 324.570 4.280 ;
        RECT 325.410 0.010 326.410 4.280 ;
        RECT 327.250 0.010 328.250 4.280 ;
        RECT 329.090 0.010 330.090 4.280 ;
        RECT 330.930 0.010 331.930 4.280 ;
        RECT 332.770 0.010 333.770 4.280 ;
        RECT 334.610 0.010 335.610 4.280 ;
        RECT 336.450 0.010 337.450 4.280 ;
        RECT 338.290 0.010 339.290 4.280 ;
        RECT 340.130 0.010 341.130 4.280 ;
        RECT 341.970 0.010 342.970 4.280 ;
        RECT 343.810 0.010 344.810 4.280 ;
        RECT 345.650 0.010 346.650 4.280 ;
        RECT 347.490 0.010 348.490 4.280 ;
        RECT 349.330 0.010 350.330 4.280 ;
        RECT 351.170 0.010 352.170 4.280 ;
        RECT 353.010 0.010 354.010 4.280 ;
        RECT 354.850 0.010 355.850 4.280 ;
        RECT 356.690 0.010 357.690 4.280 ;
        RECT 358.530 0.010 359.530 4.280 ;
        RECT 360.370 0.010 361.370 4.280 ;
        RECT 362.210 0.010 363.210 4.280 ;
        RECT 364.050 0.010 365.050 4.280 ;
        RECT 365.890 0.010 366.890 4.280 ;
        RECT 367.730 0.010 368.730 4.280 ;
        RECT 369.570 0.010 370.570 4.280 ;
        RECT 371.410 0.010 372.410 4.280 ;
        RECT 373.250 0.010 374.250 4.280 ;
        RECT 375.090 0.010 376.090 4.280 ;
        RECT 376.930 0.010 377.930 4.280 ;
        RECT 378.770 0.010 379.770 4.280 ;
        RECT 380.610 0.010 381.610 4.280 ;
        RECT 382.450 0.010 383.450 4.280 ;
        RECT 384.290 0.010 385.290 4.280 ;
        RECT 386.130 0.010 387.130 4.280 ;
        RECT 387.970 0.010 388.970 4.280 ;
        RECT 389.810 0.010 390.810 4.280 ;
        RECT 391.650 0.010 392.650 4.280 ;
        RECT 393.490 0.010 394.490 4.280 ;
        RECT 395.330 0.010 396.330 4.280 ;
        RECT 397.170 0.010 398.170 4.280 ;
        RECT 399.010 0.010 400.010 4.280 ;
        RECT 400.850 0.010 401.850 4.280 ;
        RECT 402.690 0.010 403.690 4.280 ;
        RECT 404.530 0.010 405.530 4.280 ;
        RECT 406.370 0.010 407.370 4.280 ;
        RECT 408.210 0.010 409.210 4.280 ;
        RECT 410.050 0.010 411.050 4.280 ;
        RECT 411.890 0.010 412.890 4.280 ;
        RECT 413.730 0.010 414.730 4.280 ;
        RECT 415.570 0.010 416.570 4.280 ;
        RECT 417.410 0.010 418.410 4.280 ;
        RECT 419.250 0.010 420.250 4.280 ;
        RECT 421.090 0.010 422.090 4.280 ;
        RECT 422.930 0.010 423.930 4.280 ;
        RECT 424.770 0.010 425.770 4.280 ;
        RECT 426.610 0.010 427.610 4.280 ;
        RECT 428.450 0.010 429.450 4.280 ;
        RECT 430.290 0.010 431.290 4.280 ;
        RECT 432.130 0.010 433.130 4.280 ;
        RECT 433.970 0.010 434.970 4.280 ;
        RECT 435.810 0.010 436.810 4.280 ;
        RECT 437.650 0.010 438.650 4.280 ;
        RECT 439.490 0.010 440.490 4.280 ;
        RECT 441.330 0.010 442.330 4.280 ;
        RECT 443.170 0.010 444.170 4.280 ;
        RECT 445.010 0.010 446.010 4.280 ;
        RECT 446.850 0.010 447.850 4.280 ;
        RECT 448.690 0.010 449.690 4.280 ;
        RECT 450.530 0.010 451.530 4.280 ;
        RECT 452.370 0.010 453.370 4.280 ;
        RECT 454.210 0.010 455.210 4.280 ;
        RECT 456.050 0.010 457.050 4.280 ;
        RECT 457.890 0.010 458.890 4.280 ;
        RECT 459.730 0.010 460.730 4.280 ;
        RECT 461.570 0.010 462.570 4.280 ;
        RECT 463.410 0.010 464.410 4.280 ;
        RECT 465.250 0.010 466.250 4.280 ;
        RECT 467.090 0.010 468.090 4.280 ;
        RECT 468.930 0.010 469.930 4.280 ;
        RECT 470.770 0.010 471.770 4.280 ;
        RECT 472.610 0.010 473.610 4.280 ;
        RECT 474.450 0.010 475.450 4.280 ;
        RECT 476.290 0.010 477.290 4.280 ;
        RECT 478.130 0.010 479.130 4.280 ;
        RECT 479.970 0.010 480.970 4.280 ;
        RECT 481.810 0.010 482.810 4.280 ;
        RECT 483.650 0.010 484.650 4.280 ;
        RECT 485.490 0.010 486.490 4.280 ;
        RECT 487.330 0.010 488.330 4.280 ;
        RECT 489.170 0.010 490.170 4.280 ;
        RECT 491.010 0.010 492.010 4.280 ;
        RECT 492.850 0.010 493.850 4.280 ;
        RECT 494.690 0.010 495.690 4.280 ;
        RECT 496.530 0.010 497.530 4.280 ;
        RECT 498.370 0.010 499.370 4.280 ;
        RECT 500.210 0.010 501.210 4.280 ;
        RECT 502.050 0.010 503.050 4.280 ;
        RECT 503.890 0.010 504.890 4.280 ;
        RECT 505.730 0.010 506.730 4.280 ;
        RECT 507.570 0.010 508.570 4.280 ;
        RECT 509.410 0.010 510.410 4.280 ;
        RECT 511.250 0.010 512.250 4.280 ;
        RECT 513.090 0.010 514.090 4.280 ;
        RECT 514.930 0.010 515.930 4.280 ;
        RECT 516.770 0.010 517.770 4.280 ;
        RECT 518.610 0.010 519.610 4.280 ;
        RECT 520.450 0.010 521.450 4.280 ;
        RECT 522.290 0.010 523.290 4.280 ;
        RECT 524.130 0.010 525.130 4.280 ;
        RECT 525.970 0.010 526.970 4.280 ;
        RECT 527.810 0.010 528.810 4.280 ;
        RECT 529.650 0.010 530.650 4.280 ;
        RECT 531.490 0.010 532.490 4.280 ;
        RECT 533.330 0.010 534.330 4.280 ;
        RECT 535.170 0.010 536.170 4.280 ;
        RECT 537.010 0.010 538.010 4.280 ;
        RECT 538.850 0.010 539.850 4.280 ;
        RECT 540.690 0.010 541.690 4.280 ;
        RECT 542.530 0.010 543.530 4.280 ;
        RECT 544.370 0.010 545.370 4.280 ;
        RECT 546.210 0.010 547.210 4.280 ;
        RECT 548.050 0.010 549.050 4.280 ;
        RECT 549.890 0.010 550.890 4.280 ;
        RECT 551.730 0.010 552.730 4.280 ;
        RECT 553.570 0.010 554.570 4.280 ;
        RECT 555.410 0.010 556.410 4.280 ;
        RECT 557.250 0.010 558.250 4.280 ;
        RECT 559.090 0.010 560.090 4.280 ;
        RECT 560.930 0.010 561.930 4.280 ;
        RECT 562.770 0.010 563.770 4.280 ;
        RECT 564.610 0.010 565.610 4.280 ;
        RECT 566.450 0.010 567.450 4.280 ;
        RECT 568.290 0.010 569.290 4.280 ;
        RECT 570.130 0.010 571.130 4.280 ;
        RECT 571.970 0.010 572.970 4.280 ;
        RECT 573.810 0.010 574.810 4.280 ;
        RECT 575.650 0.010 576.650 4.280 ;
        RECT 577.490 0.010 578.490 4.280 ;
        RECT 579.330 0.010 580.330 4.280 ;
        RECT 581.170 0.010 582.170 4.280 ;
        RECT 583.010 0.010 584.010 4.280 ;
        RECT 584.850 0.010 585.850 4.280 ;
        RECT 586.690 0.010 587.690 4.280 ;
        RECT 588.530 0.010 589.530 4.280 ;
        RECT 590.370 0.010 591.370 4.280 ;
        RECT 592.210 0.010 593.210 4.280 ;
        RECT 594.050 0.010 595.050 4.280 ;
        RECT 595.890 0.010 596.890 4.280 ;
        RECT 597.730 0.010 598.730 4.280 ;
        RECT 599.570 0.010 600.570 4.280 ;
        RECT 601.410 0.010 602.410 4.280 ;
        RECT 603.250 0.010 604.250 4.280 ;
        RECT 605.090 0.010 606.090 4.280 ;
        RECT 606.930 0.010 607.930 4.280 ;
        RECT 608.770 0.010 609.770 4.280 ;
        RECT 610.610 0.010 611.610 4.280 ;
        RECT 612.450 0.010 613.450 4.280 ;
        RECT 614.290 0.010 615.290 4.280 ;
        RECT 616.130 0.010 617.130 4.280 ;
        RECT 617.970 0.010 618.970 4.280 ;
        RECT 619.810 0.010 620.810 4.280 ;
        RECT 621.650 0.010 622.650 4.280 ;
        RECT 623.490 0.010 624.490 4.280 ;
        RECT 625.330 0.010 626.330 4.280 ;
        RECT 627.170 0.010 628.170 4.280 ;
        RECT 629.010 0.010 630.010 4.280 ;
        RECT 630.850 0.010 631.850 4.280 ;
        RECT 632.690 0.010 633.690 4.280 ;
        RECT 634.530 0.010 635.530 4.280 ;
        RECT 636.370 0.010 637.370 4.280 ;
        RECT 638.210 0.010 639.210 4.280 ;
        RECT 640.050 0.010 641.050 4.280 ;
        RECT 641.890 0.010 642.890 4.280 ;
        RECT 643.730 0.010 644.730 4.280 ;
        RECT 645.570 0.010 646.570 4.280 ;
        RECT 647.410 0.010 648.410 4.280 ;
        RECT 649.250 0.010 650.250 4.280 ;
        RECT 651.090 0.010 652.090 4.280 ;
        RECT 652.930 0.010 653.930 4.280 ;
        RECT 654.770 0.010 655.770 4.280 ;
        RECT 656.610 0.010 657.610 4.280 ;
        RECT 658.450 0.010 659.450 4.280 ;
        RECT 660.290 0.010 661.290 4.280 ;
        RECT 662.130 0.010 663.130 4.280 ;
        RECT 663.970 0.010 664.970 4.280 ;
        RECT 665.810 0.010 666.810 4.280 ;
        RECT 667.650 0.010 668.650 4.280 ;
        RECT 669.490 0.010 670.490 4.280 ;
        RECT 671.330 0.010 672.330 4.280 ;
        RECT 673.170 0.010 674.170 4.280 ;
        RECT 675.010 0.010 676.010 4.280 ;
        RECT 676.850 0.010 677.850 4.280 ;
        RECT 678.690 0.010 679.690 4.280 ;
        RECT 680.530 0.010 681.530 4.280 ;
        RECT 682.370 0.010 683.370 4.280 ;
        RECT 684.210 0.010 685.210 4.280 ;
        RECT 686.050 0.010 687.050 4.280 ;
        RECT 687.890 0.010 688.890 4.280 ;
        RECT 689.730 0.010 690.730 4.280 ;
        RECT 691.570 0.010 692.570 4.280 ;
        RECT 693.410 0.010 694.410 4.280 ;
        RECT 695.250 0.010 696.250 4.280 ;
        RECT 697.090 0.010 698.090 4.280 ;
        RECT 698.930 0.010 699.930 4.280 ;
        RECT 700.770 0.010 701.770 4.280 ;
        RECT 702.610 0.010 703.610 4.280 ;
        RECT 704.450 0.010 705.450 4.280 ;
        RECT 706.290 0.010 707.290 4.280 ;
        RECT 708.130 0.010 709.130 4.280 ;
        RECT 709.970 0.010 710.970 4.280 ;
        RECT 711.810 0.010 712.810 4.280 ;
        RECT 713.650 0.010 714.650 4.280 ;
        RECT 715.490 0.010 716.490 4.280 ;
        RECT 717.330 0.010 718.330 4.280 ;
        RECT 719.170 0.010 720.170 4.280 ;
        RECT 721.010 0.010 722.010 4.280 ;
        RECT 722.850 0.010 723.850 4.280 ;
        RECT 724.690 0.010 725.690 4.280 ;
        RECT 726.530 0.010 727.530 4.280 ;
        RECT 728.370 0.010 729.370 4.280 ;
        RECT 730.210 0.010 731.210 4.280 ;
        RECT 732.050 0.010 733.050 4.280 ;
        RECT 733.890 0.010 734.890 4.280 ;
        RECT 735.730 0.010 736.730 4.280 ;
        RECT 737.570 0.010 738.570 4.280 ;
        RECT 739.410 0.010 740.410 4.280 ;
        RECT 741.250 0.010 742.250 4.280 ;
        RECT 743.090 0.010 744.090 4.280 ;
        RECT 744.930 0.010 745.930 4.280 ;
        RECT 746.770 0.010 747.770 4.280 ;
        RECT 748.610 0.010 749.610 4.280 ;
        RECT 750.450 0.010 751.450 4.280 ;
        RECT 752.290 0.010 753.290 4.280 ;
        RECT 754.130 0.010 755.130 4.280 ;
        RECT 755.970 0.010 756.970 4.280 ;
        RECT 757.810 0.010 758.810 4.280 ;
        RECT 759.650 0.010 760.650 4.280 ;
        RECT 761.490 0.010 762.490 4.280 ;
        RECT 763.330 0.010 764.330 4.280 ;
        RECT 765.170 0.010 766.170 4.280 ;
        RECT 767.010 0.010 768.010 4.280 ;
        RECT 768.850 0.010 769.850 4.280 ;
        RECT 770.690 0.010 771.690 4.280 ;
        RECT 772.530 0.010 773.530 4.280 ;
        RECT 774.370 0.010 775.370 4.280 ;
        RECT 776.210 0.010 777.210 4.280 ;
        RECT 778.050 0.010 779.050 4.280 ;
        RECT 779.890 0.010 780.890 4.280 ;
        RECT 781.730 0.010 782.730 4.280 ;
        RECT 783.570 0.010 784.570 4.280 ;
        RECT 785.410 0.010 786.410 4.280 ;
        RECT 787.250 0.010 788.250 4.280 ;
        RECT 789.090 0.010 790.090 4.280 ;
        RECT 790.930 0.010 791.930 4.280 ;
        RECT 792.770 0.010 793.770 4.280 ;
        RECT 794.610 0.010 795.610 4.280 ;
        RECT 796.450 0.010 797.450 4.280 ;
        RECT 798.290 0.010 799.290 4.280 ;
        RECT 800.130 0.010 801.130 4.280 ;
        RECT 801.970 0.010 802.970 4.280 ;
        RECT 803.810 0.010 804.810 4.280 ;
        RECT 805.650 0.010 806.650 4.280 ;
        RECT 807.490 0.010 808.490 4.280 ;
        RECT 809.330 0.010 810.330 4.280 ;
        RECT 811.170 0.010 812.170 4.280 ;
        RECT 813.010 0.010 814.010 4.280 ;
        RECT 814.850 0.010 815.850 4.280 ;
        RECT 816.690 0.010 817.690 4.280 ;
        RECT 818.530 0.010 819.530 4.280 ;
        RECT 820.370 0.010 821.370 4.280 ;
        RECT 822.210 0.010 823.210 4.280 ;
        RECT 824.050 0.010 825.050 4.280 ;
        RECT 825.890 0.010 826.890 4.280 ;
        RECT 827.730 0.010 828.730 4.280 ;
        RECT 829.570 0.010 830.570 4.280 ;
        RECT 831.410 0.010 832.410 4.280 ;
        RECT 833.250 0.010 836.180 4.280 ;
      LAYER met3 ;
        RECT 4.000 60.880 830.235 65.105 ;
        RECT 4.400 59.480 830.235 60.880 ;
        RECT 4.000 58.160 830.235 59.480 ;
        RECT 4.400 56.760 830.235 58.160 ;
        RECT 4.000 55.440 830.235 56.760 ;
        RECT 4.400 54.040 830.235 55.440 ;
        RECT 4.000 52.720 830.235 54.040 ;
        RECT 4.400 51.320 830.235 52.720 ;
        RECT 4.000 50.000 830.235 51.320 ;
        RECT 4.400 48.600 830.235 50.000 ;
        RECT 4.000 47.280 830.235 48.600 ;
        RECT 4.400 45.880 830.235 47.280 ;
        RECT 4.000 44.560 830.235 45.880 ;
        RECT 4.400 43.160 830.235 44.560 ;
        RECT 4.000 41.840 830.235 43.160 ;
        RECT 4.400 40.440 830.235 41.840 ;
        RECT 4.000 39.120 830.235 40.440 ;
        RECT 4.400 37.720 830.235 39.120 ;
        RECT 4.000 36.400 830.235 37.720 ;
        RECT 4.400 35.000 830.235 36.400 ;
        RECT 4.000 33.680 830.235 35.000 ;
        RECT 4.400 32.280 830.235 33.680 ;
        RECT 4.000 30.960 830.235 32.280 ;
        RECT 4.400 29.560 830.235 30.960 ;
        RECT 4.000 28.240 830.235 29.560 ;
        RECT 4.400 26.840 830.235 28.240 ;
        RECT 4.000 25.520 830.235 26.840 ;
        RECT 4.400 24.120 830.235 25.520 ;
        RECT 4.000 22.800 830.235 24.120 ;
        RECT 4.400 21.400 830.235 22.800 ;
        RECT 4.000 20.080 830.235 21.400 ;
        RECT 4.400 18.680 830.235 20.080 ;
        RECT 4.000 17.360 830.235 18.680 ;
        RECT 4.400 15.960 830.235 17.360 ;
        RECT 4.000 14.640 830.235 15.960 ;
        RECT 4.400 13.240 830.235 14.640 ;
        RECT 4.000 11.920 830.235 13.240 ;
        RECT 4.400 10.520 830.235 11.920 ;
        RECT 4.000 9.200 830.235 10.520 ;
        RECT 4.400 7.800 830.235 9.200 ;
        RECT 4.000 6.480 830.235 7.800 ;
        RECT 4.400 5.080 830.235 6.480 ;
        RECT 4.000 0.175 830.235 5.080 ;
      LAYER met4 ;
        RECT 27.470 0.855 766.065 65.105 ;
      LAYER met5 ;
        RECT 1.840 0.900 847.780 52.910 ;
  END
END mgmt_protect
END LIBRARY

